VERSION 5.7 ;
BUSBITCHARS "[]" ;
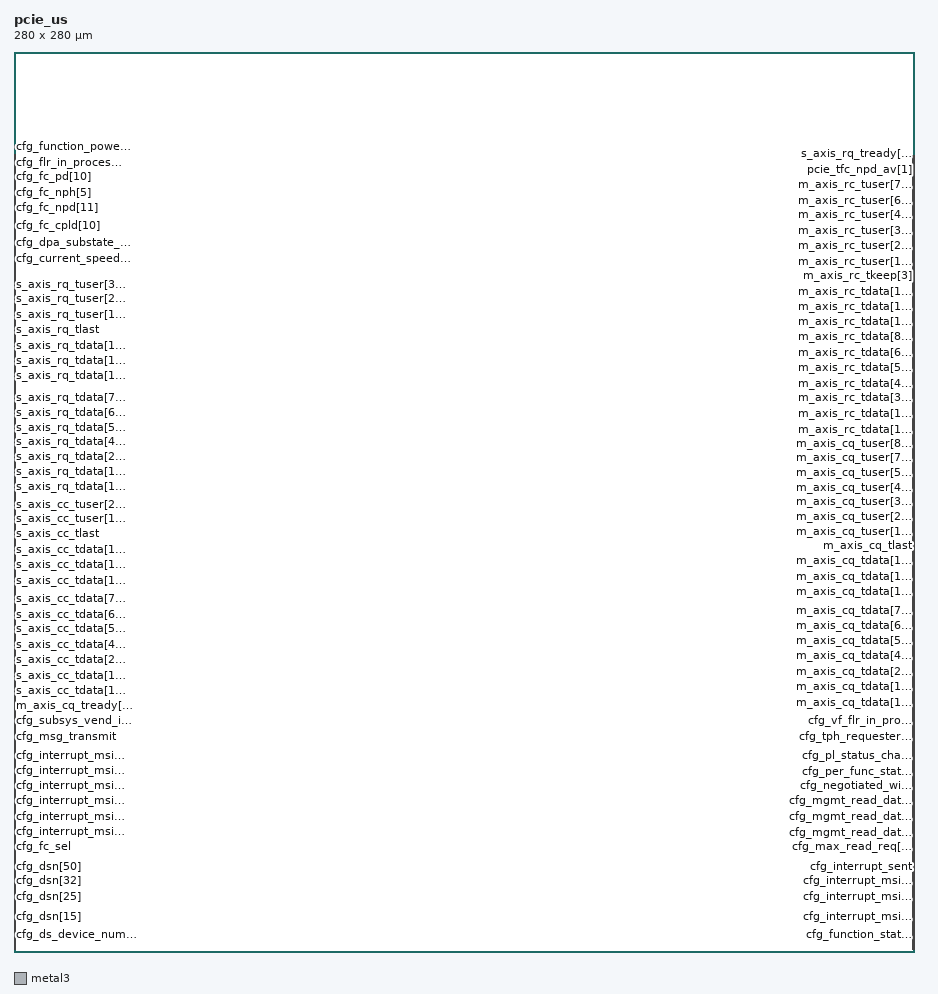
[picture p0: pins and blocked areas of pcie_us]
MACRO pcie_us
  CLASS BLOCK ;
  FOREIGN pcie_us 0 0 ;
  SYMMETRY X Y R90 ;
  SIZE 280.000 BY 280.000 ;
  PIN cfg_config_space_enable
    DIRECTION INPUT ;
    USE SIGNAL ;
    PORT
      LAYER metal3 ;
      RECT 0.000 0.795 0.380 0.865 ;
    END
  END cfg_config_space_enable
  PIN cfg_ds_bus_number[0]
    DIRECTION INPUT ;
    USE SIGNAL ;
    PORT
      LAYER metal3 ;
      RECT 0.000 1.175 0.380 1.245 ;
    END
  END cfg_ds_bus_number[0]
  PIN cfg_ds_bus_number[1]
    DIRECTION INPUT ;
    USE SIGNAL ;
    PORT
      LAYER metal3 ;
      RECT 0.000 1.555 0.380 1.625 ;
    END
  END cfg_ds_bus_number[1]
  PIN cfg_ds_bus_number[2]
    DIRECTION INPUT ;
    USE SIGNAL ;
    PORT
      LAYER metal3 ;
      RECT 0.000 1.935 0.380 2.005 ;
    END
  END cfg_ds_bus_number[2]
  PIN cfg_ds_bus_number[3]
    DIRECTION INPUT ;
    USE SIGNAL ;
    PORT
      LAYER metal3 ;
      RECT 0.000 2.315 0.380 2.385 ;
    END
  END cfg_ds_bus_number[3]
  PIN cfg_ds_bus_number[4]
    DIRECTION INPUT ;
    USE SIGNAL ;
    PORT
      LAYER metal3 ;
      RECT 0.000 2.695 0.380 2.765 ;
    END
  END cfg_ds_bus_number[4]
  PIN cfg_ds_bus_number[5]
    DIRECTION INPUT ;
    USE SIGNAL ;
    PORT
      LAYER metal3 ;
      RECT 0.000 3.075 0.380 3.145 ;
    END
  END cfg_ds_bus_number[5]
  PIN cfg_ds_bus_number[6]
    DIRECTION INPUT ;
    USE SIGNAL ;
    PORT
      LAYER metal3 ;
      RECT 0.000 3.455 0.380 3.525 ;
    END
  END cfg_ds_bus_number[6]
  PIN cfg_ds_bus_number[7]
    DIRECTION INPUT ;
    USE SIGNAL ;
    PORT
      LAYER metal3 ;
      RECT 0.000 3.835 0.380 3.905 ;
    END
  END cfg_ds_bus_number[7]
  PIN cfg_ds_device_number[0]
    DIRECTION INPUT ;
    USE SIGNAL ;
    PORT
      LAYER metal3 ;
      RECT 0.000 4.215 0.380 4.285 ;
    END
  END cfg_ds_device_number[0]
  PIN cfg_ds_device_number[1]
    DIRECTION INPUT ;
    USE SIGNAL ;
    PORT
      LAYER metal3 ;
      RECT 0.000 4.595 0.380 4.665 ;
    END
  END cfg_ds_device_number[1]
  PIN cfg_ds_device_number[2]
    DIRECTION INPUT ;
    USE SIGNAL ;
    PORT
      LAYER metal3 ;
      RECT 0.000 4.975 0.380 5.045 ;
    END
  END cfg_ds_device_number[2]
  PIN cfg_ds_device_number[3]
    DIRECTION INPUT ;
    USE SIGNAL ;
    PORT
      LAYER metal3 ;
      RECT 0.000 5.355 0.380 5.425 ;
    END
  END cfg_ds_device_number[3]
  PIN cfg_ds_device_number[4]
    DIRECTION INPUT ;
    USE SIGNAL ;
    PORT
      LAYER metal3 ;
      RECT 0.000 5.735 0.380 5.805 ;
    END
  END cfg_ds_device_number[4]
  PIN cfg_ds_function_number[0]
    DIRECTION INPUT ;
    USE SIGNAL ;
    PORT
      LAYER metal3 ;
      RECT 0.000 6.115 0.380 6.185 ;
    END
  END cfg_ds_function_number[0]
  PIN cfg_ds_function_number[1]
    DIRECTION INPUT ;
    USE SIGNAL ;
    PORT
      LAYER metal3 ;
      RECT 0.000 6.495 0.380 6.565 ;
    END
  END cfg_ds_function_number[1]
  PIN cfg_ds_function_number[2]
    DIRECTION INPUT ;
    USE SIGNAL ;
    PORT
      LAYER metal3 ;
      RECT 0.000 6.875 0.380 6.945 ;
    END
  END cfg_ds_function_number[2]
  PIN cfg_ds_port_number
    DIRECTION INPUT ;
    USE SIGNAL ;
    PORT
      LAYER metal3 ;
      RECT 0.000 7.255 0.380 7.325 ;
    END
  END cfg_ds_port_number
  PIN cfg_dsn[0]
    DIRECTION INPUT ;
    USE SIGNAL ;
    PORT
      LAYER metal3 ;
      RECT 0.000 7.635 0.380 7.705 ;
    END
  END cfg_dsn[0]
  PIN cfg_dsn[1]
    DIRECTION INPUT ;
    USE SIGNAL ;
    PORT
      LAYER metal3 ;
      RECT 0.000 8.015 0.380 8.085 ;
    END
  END cfg_dsn[1]
  PIN cfg_dsn[2]
    DIRECTION INPUT ;
    USE SIGNAL ;
    PORT
      LAYER metal3 ;
      RECT 0.000 8.395 0.380 8.465 ;
    END
  END cfg_dsn[2]
  PIN cfg_dsn[3]
    DIRECTION INPUT ;
    USE SIGNAL ;
    PORT
      LAYER metal3 ;
      RECT 0.000 8.775 0.380 8.845 ;
    END
  END cfg_dsn[3]
  PIN cfg_dsn[4]
    DIRECTION INPUT ;
    USE SIGNAL ;
    PORT
      LAYER metal3 ;
      RECT 0.000 9.155 0.380 9.225 ;
    END
  END cfg_dsn[4]
  PIN cfg_dsn[5]
    DIRECTION INPUT ;
    USE SIGNAL ;
    PORT
      LAYER metal3 ;
      RECT 0.000 9.535 0.380 9.605 ;
    END
  END cfg_dsn[5]
  PIN cfg_dsn[6]
    DIRECTION INPUT ;
    USE SIGNAL ;
    PORT
      LAYER metal3 ;
      RECT 0.000 9.915 0.380 9.985 ;
    END
  END cfg_dsn[6]
  PIN cfg_dsn[7]
    DIRECTION INPUT ;
    USE SIGNAL ;
    PORT
      LAYER metal3 ;
      RECT 0.000 10.295 0.380 10.365 ;
    END
  END cfg_dsn[7]
  PIN cfg_dsn[8]
    DIRECTION INPUT ;
    USE SIGNAL ;
    PORT
      LAYER metal3 ;
      RECT 0.000 10.675 0.380 10.745 ;
    END
  END cfg_dsn[8]
  PIN cfg_dsn[9]
    DIRECTION INPUT ;
    USE SIGNAL ;
    PORT
      LAYER metal3 ;
      RECT 0.000 11.055 0.380 11.125 ;
    END
  END cfg_dsn[9]
  PIN cfg_dsn[10]
    DIRECTION INPUT ;
    USE SIGNAL ;
    PORT
      LAYER metal3 ;
      RECT 0.000 11.435 0.380 11.505 ;
    END
  END cfg_dsn[10]
  PIN cfg_dsn[11]
    DIRECTION INPUT ;
    USE SIGNAL ;
    PORT
      LAYER metal3 ;
      RECT 0.000 11.815 0.380 11.885 ;
    END
  END cfg_dsn[11]
  PIN cfg_dsn[12]
    DIRECTION INPUT ;
    USE SIGNAL ;
    PORT
      LAYER metal3 ;
      RECT 0.000 12.195 0.380 12.265 ;
    END
  END cfg_dsn[12]
  PIN cfg_dsn[13]
    DIRECTION INPUT ;
    USE SIGNAL ;
    PORT
      LAYER metal3 ;
      RECT 0.000 12.575 0.380 12.645 ;
    END
  END cfg_dsn[13]
  PIN cfg_dsn[14]
    DIRECTION INPUT ;
    USE SIGNAL ;
    PORT
      LAYER metal3 ;
      RECT 0.000 12.955 0.380 13.025 ;
    END
  END cfg_dsn[14]
  PIN cfg_dsn[15]
    DIRECTION INPUT ;
    USE SIGNAL ;
    PORT
      LAYER metal3 ;
      RECT 0.000 13.335 0.380 13.405 ;
    END
  END cfg_dsn[15]
  PIN cfg_dsn[16]
    DIRECTION INPUT ;
    USE SIGNAL ;
    PORT
      LAYER metal3 ;
      RECT 0.000 13.715 0.380 13.785 ;
    END
  END cfg_dsn[16]
  PIN cfg_dsn[17]
    DIRECTION INPUT ;
    USE SIGNAL ;
    PORT
      LAYER metal3 ;
      RECT 0.000 14.095 0.380 14.165 ;
    END
  END cfg_dsn[17]
  PIN cfg_dsn[18]
    DIRECTION INPUT ;
    USE SIGNAL ;
    PORT
      LAYER metal3 ;
      RECT 0.000 14.475 0.380 14.545 ;
    END
  END cfg_dsn[18]
  PIN cfg_dsn[19]
    DIRECTION INPUT ;
    USE SIGNAL ;
    PORT
      LAYER metal3 ;
      RECT 0.000 14.855 0.380 14.925 ;
    END
  END cfg_dsn[19]
  PIN cfg_dsn[20]
    DIRECTION INPUT ;
    USE SIGNAL ;
    PORT
      LAYER metal3 ;
      RECT 0.000 15.235 0.380 15.305 ;
    END
  END cfg_dsn[20]
  PIN cfg_dsn[21]
    DIRECTION INPUT ;
    USE SIGNAL ;
    PORT
      LAYER metal3 ;
      RECT 0.000 15.615 0.380 15.685 ;
    END
  END cfg_dsn[21]
  PIN cfg_dsn[22]
    DIRECTION INPUT ;
    USE SIGNAL ;
    PORT
      LAYER metal3 ;
      RECT 0.000 15.995 0.380 16.065 ;
    END
  END cfg_dsn[22]
  PIN cfg_dsn[23]
    DIRECTION INPUT ;
    USE SIGNAL ;
    PORT
      LAYER metal3 ;
      RECT 0.000 16.375 0.380 16.445 ;
    END
  END cfg_dsn[23]
  PIN cfg_dsn[24]
    DIRECTION INPUT ;
    USE SIGNAL ;
    PORT
      LAYER metal3 ;
      RECT 0.000 16.755 0.380 16.825 ;
    END
  END cfg_dsn[24]
  PIN cfg_dsn[25]
    DIRECTION INPUT ;
    USE SIGNAL ;
    PORT
      LAYER metal3 ;
      RECT 0.000 17.135 0.380 17.205 ;
    END
  END cfg_dsn[25]
  PIN cfg_dsn[26]
    DIRECTION INPUT ;
    USE SIGNAL ;
    PORT
      LAYER metal3 ;
      RECT 0.000 17.515 0.380 17.585 ;
    END
  END cfg_dsn[26]
  PIN cfg_dsn[27]
    DIRECTION INPUT ;
    USE SIGNAL ;
    PORT
      LAYER metal3 ;
      RECT 0.000 17.895 0.380 17.965 ;
    END
  END cfg_dsn[27]
  PIN cfg_dsn[28]
    DIRECTION INPUT ;
    USE SIGNAL ;
    PORT
      LAYER metal3 ;
      RECT 0.000 18.275 0.380 18.345 ;
    END
  END cfg_dsn[28]
  PIN cfg_dsn[29]
    DIRECTION INPUT ;
    USE SIGNAL ;
    PORT
      LAYER metal3 ;
      RECT 0.000 18.655 0.380 18.725 ;
    END
  END cfg_dsn[29]
  PIN cfg_dsn[30]
    DIRECTION INPUT ;
    USE SIGNAL ;
    PORT
      LAYER metal3 ;
      RECT 0.000 19.035 0.380 19.105 ;
    END
  END cfg_dsn[30]
  PIN cfg_dsn[31]
    DIRECTION INPUT ;
    USE SIGNAL ;
    PORT
      LAYER metal3 ;
      RECT 0.000 19.415 0.380 19.485 ;
    END
  END cfg_dsn[31]
  PIN cfg_dsn[32]
    DIRECTION INPUT ;
    USE SIGNAL ;
    PORT
      LAYER metal3 ;
      RECT 0.000 19.795 0.380 19.865 ;
    END
  END cfg_dsn[32]
  PIN cfg_dsn[33]
    DIRECTION INPUT ;
    USE SIGNAL ;
    PORT
      LAYER metal3 ;
      RECT 0.000 20.175 0.380 20.245 ;
    END
  END cfg_dsn[33]
  PIN cfg_dsn[34]
    DIRECTION INPUT ;
    USE SIGNAL ;
    PORT
      LAYER metal3 ;
      RECT 0.000 20.555 0.380 20.625 ;
    END
  END cfg_dsn[34]
  PIN cfg_dsn[35]
    DIRECTION INPUT ;
    USE SIGNAL ;
    PORT
      LAYER metal3 ;
      RECT 0.000 20.935 0.380 21.005 ;
    END
  END cfg_dsn[35]
  PIN cfg_dsn[36]
    DIRECTION INPUT ;
    USE SIGNAL ;
    PORT
      LAYER metal3 ;
      RECT 0.000 21.315 0.380 21.385 ;
    END
  END cfg_dsn[36]
  PIN cfg_dsn[37]
    DIRECTION INPUT ;
    USE SIGNAL ;
    PORT
      LAYER metal3 ;
      RECT 0.000 21.695 0.380 21.765 ;
    END
  END cfg_dsn[37]
  PIN cfg_dsn[38]
    DIRECTION INPUT ;
    USE SIGNAL ;
    PORT
      LAYER metal3 ;
      RECT 0.000 22.075 0.380 22.145 ;
    END
  END cfg_dsn[38]
  PIN cfg_dsn[39]
    DIRECTION INPUT ;
    USE SIGNAL ;
    PORT
      LAYER metal3 ;
      RECT 0.000 22.455 0.380 22.525 ;
    END
  END cfg_dsn[39]
  PIN cfg_dsn[40]
    DIRECTION INPUT ;
    USE SIGNAL ;
    PORT
      LAYER metal3 ;
      RECT 0.000 22.835 0.380 22.905 ;
    END
  END cfg_dsn[40]
  PIN cfg_dsn[41]
    DIRECTION INPUT ;
    USE SIGNAL ;
    PORT
      LAYER metal3 ;
      RECT 0.000 23.215 0.380 23.285 ;
    END
  END cfg_dsn[41]
  PIN cfg_dsn[42]
    DIRECTION INPUT ;
    USE SIGNAL ;
    PORT
      LAYER metal3 ;
      RECT 0.000 23.595 0.380 23.665 ;
    END
  END cfg_dsn[42]
  PIN cfg_dsn[43]
    DIRECTION INPUT ;
    USE SIGNAL ;
    PORT
      LAYER metal3 ;
      RECT 0.000 23.975 0.380 24.045 ;
    END
  END cfg_dsn[43]
  PIN cfg_dsn[44]
    DIRECTION INPUT ;
    USE SIGNAL ;
    PORT
      LAYER metal3 ;
      RECT 0.000 24.355 0.380 24.425 ;
    END
  END cfg_dsn[44]
  PIN cfg_dsn[45]
    DIRECTION INPUT ;
    USE SIGNAL ;
    PORT
      LAYER metal3 ;
      RECT 0.000 24.735 0.380 24.805 ;
    END
  END cfg_dsn[45]
  PIN cfg_dsn[46]
    DIRECTION INPUT ;
    USE SIGNAL ;
    PORT
      LAYER metal3 ;
      RECT 0.000 25.115 0.380 25.185 ;
    END
  END cfg_dsn[46]
  PIN cfg_dsn[47]
    DIRECTION INPUT ;
    USE SIGNAL ;
    PORT
      LAYER metal3 ;
      RECT 0.000 25.495 0.380 25.565 ;
    END
  END cfg_dsn[47]
  PIN cfg_dsn[48]
    DIRECTION INPUT ;
    USE SIGNAL ;
    PORT
      LAYER metal3 ;
      RECT 0.000 25.875 0.380 25.945 ;
    END
  END cfg_dsn[48]
  PIN cfg_dsn[49]
    DIRECTION INPUT ;
    USE SIGNAL ;
    PORT
      LAYER metal3 ;
      RECT 0.000 26.255 0.380 26.325 ;
    END
  END cfg_dsn[49]
  PIN cfg_dsn[50]
    DIRECTION INPUT ;
    USE SIGNAL ;
    PORT
      LAYER metal3 ;
      RECT 0.000 26.635 0.380 26.705 ;
    END
  END cfg_dsn[50]
  PIN cfg_dsn[51]
    DIRECTION INPUT ;
    USE SIGNAL ;
    PORT
      LAYER metal3 ;
      RECT 0.000 27.015 0.380 27.085 ;
    END
  END cfg_dsn[51]
  PIN cfg_dsn[52]
    DIRECTION INPUT ;
    USE SIGNAL ;
    PORT
      LAYER metal3 ;
      RECT 0.000 27.395 0.380 27.465 ;
    END
  END cfg_dsn[52]
  PIN cfg_dsn[53]
    DIRECTION INPUT ;
    USE SIGNAL ;
    PORT
      LAYER metal3 ;
      RECT 0.000 27.775 0.380 27.845 ;
    END
  END cfg_dsn[53]
  PIN cfg_dsn[54]
    DIRECTION INPUT ;
    USE SIGNAL ;
    PORT
      LAYER metal3 ;
      RECT 0.000 28.155 0.380 28.225 ;
    END
  END cfg_dsn[54]
  PIN cfg_dsn[55]
    DIRECTION INPUT ;
    USE SIGNAL ;
    PORT
      LAYER metal3 ;
      RECT 0.000 28.535 0.380 28.605 ;
    END
  END cfg_dsn[55]
  PIN cfg_dsn[56]
    DIRECTION INPUT ;
    USE SIGNAL ;
    PORT
      LAYER metal3 ;
      RECT 0.000 28.915 0.380 28.985 ;
    END
  END cfg_dsn[56]
  PIN cfg_dsn[57]
    DIRECTION INPUT ;
    USE SIGNAL ;
    PORT
      LAYER metal3 ;
      RECT 0.000 29.295 0.380 29.365 ;
    END
  END cfg_dsn[57]
  PIN cfg_dsn[58]
    DIRECTION INPUT ;
    USE SIGNAL ;
    PORT
      LAYER metal3 ;
      RECT 0.000 29.675 0.380 29.745 ;
    END
  END cfg_dsn[58]
  PIN cfg_dsn[59]
    DIRECTION INPUT ;
    USE SIGNAL ;
    PORT
      LAYER metal3 ;
      RECT 0.000 30.055 0.380 30.125 ;
    END
  END cfg_dsn[59]
  PIN cfg_dsn[60]
    DIRECTION INPUT ;
    USE SIGNAL ;
    PORT
      LAYER metal3 ;
      RECT 0.000 30.435 0.380 30.505 ;
    END
  END cfg_dsn[60]
  PIN cfg_dsn[61]
    DIRECTION INPUT ;
    USE SIGNAL ;
    PORT
      LAYER metal3 ;
      RECT 0.000 30.815 0.380 30.885 ;
    END
  END cfg_dsn[61]
  PIN cfg_dsn[62]
    DIRECTION INPUT ;
    USE SIGNAL ;
    PORT
      LAYER metal3 ;
      RECT 0.000 31.195 0.380 31.265 ;
    END
  END cfg_dsn[62]
  PIN cfg_dsn[63]
    DIRECTION INPUT ;
    USE SIGNAL ;
    PORT
      LAYER metal3 ;
      RECT 0.000 31.575 0.380 31.645 ;
    END
  END cfg_dsn[63]
  PIN cfg_err_cor_in
    DIRECTION INPUT ;
    USE SIGNAL ;
    PORT
      LAYER metal3 ;
      RECT 0.000 31.955 0.380 32.025 ;
    END
  END cfg_err_cor_in
  PIN cfg_err_uncor_in
    DIRECTION INPUT ;
    USE SIGNAL ;
    PORT
      LAYER metal3 ;
      RECT 0.000 32.335 0.380 32.405 ;
    END
  END cfg_err_uncor_in
  PIN cfg_fc_sel
    DIRECTION INPUT ;
    USE SIGNAL ;
    PORT
      LAYER metal3 ;
      RECT 0.000 32.715 0.380 32.785 ;
    END
  END cfg_fc_sel
  PIN cfg_flr_done
    DIRECTION INPUT ;
    USE SIGNAL ;
    PORT
      LAYER metal3 ;
      RECT 0.000 33.095 0.380 33.165 ;
    END
  END cfg_flr_done
  PIN cfg_hot_reset_in
    DIRECTION INPUT ;
    USE SIGNAL ;
    PORT
      LAYER metal3 ;
      RECT 0.000 33.475 0.380 33.545 ;
    END
  END cfg_hot_reset_in
  PIN cfg_interrupt_int
    DIRECTION INPUT ;
    USE SIGNAL ;
    PORT
      LAYER metal3 ;
      RECT 0.000 33.855 0.380 33.925 ;
    END
  END cfg_interrupt_int
  PIN cfg_interrupt_msi_attr
    DIRECTION INPUT ;
    USE SIGNAL ;
    PORT
      LAYER metal3 ;
      RECT 0.000 34.235 0.380 34.305 ;
    END
  END cfg_interrupt_msi_attr
  PIN cfg_interrupt_msi_function_number
    DIRECTION INPUT ;
    USE SIGNAL ;
    PORT
      LAYER metal3 ;
      RECT 0.000 34.615 0.380 34.685 ;
    END
  END cfg_interrupt_msi_function_number
  PIN cfg_interrupt_msi_int[0]
    DIRECTION INPUT ;
    USE SIGNAL ;
    PORT
      LAYER metal3 ;
      RECT 0.000 34.995 0.380 35.065 ;
    END
  END cfg_interrupt_msi_int[0]
  PIN cfg_interrupt_msi_int[1]
    DIRECTION INPUT ;
    USE SIGNAL ;
    PORT
      LAYER metal3 ;
      RECT 0.000 35.375 0.380 35.445 ;
    END
  END cfg_interrupt_msi_int[1]
  PIN cfg_interrupt_msi_int[2]
    DIRECTION INPUT ;
    USE SIGNAL ;
    PORT
      LAYER metal3 ;
      RECT 0.000 35.755 0.380 35.825 ;
    END
  END cfg_interrupt_msi_int[2]
  PIN cfg_interrupt_msi_int[3]
    DIRECTION INPUT ;
    USE SIGNAL ;
    PORT
      LAYER metal3 ;
      RECT 0.000 36.135 0.380 36.205 ;
    END
  END cfg_interrupt_msi_int[3]
  PIN cfg_interrupt_msi_int[4]
    DIRECTION INPUT ;
    USE SIGNAL ;
    PORT
      LAYER metal3 ;
      RECT 0.000 36.515 0.380 36.585 ;
    END
  END cfg_interrupt_msi_int[4]
  PIN cfg_interrupt_msi_int[5]
    DIRECTION INPUT ;
    USE SIGNAL ;
    PORT
      LAYER metal3 ;
      RECT 0.000 36.895 0.380 36.965 ;
    END
  END cfg_interrupt_msi_int[5]
  PIN cfg_interrupt_msi_int[6]
    DIRECTION INPUT ;
    USE SIGNAL ;
    PORT
      LAYER metal3 ;
      RECT 0.000 37.275 0.380 37.345 ;
    END
  END cfg_interrupt_msi_int[6]
  PIN cfg_interrupt_msi_int[7]
    DIRECTION INPUT ;
    USE SIGNAL ;
    PORT
      LAYER metal3 ;
      RECT 0.000 37.655 0.380 37.725 ;
    END
  END cfg_interrupt_msi_int[7]
  PIN cfg_interrupt_msi_int[8]
    DIRECTION INPUT ;
    USE SIGNAL ;
    PORT
      LAYER metal3 ;
      RECT 0.000 38.035 0.380 38.105 ;
    END
  END cfg_interrupt_msi_int[8]
  PIN cfg_interrupt_msi_int[9]
    DIRECTION INPUT ;
    USE SIGNAL ;
    PORT
      LAYER metal3 ;
      RECT 0.000 38.415 0.380 38.485 ;
    END
  END cfg_interrupt_msi_int[9]
  PIN cfg_interrupt_msi_int[10]
    DIRECTION INPUT ;
    USE SIGNAL ;
    PORT
      LAYER metal3 ;
      RECT 0.000 38.795 0.380 38.865 ;
    END
  END cfg_interrupt_msi_int[10]
  PIN cfg_interrupt_msi_int[11]
    DIRECTION INPUT ;
    USE SIGNAL ;
    PORT
      LAYER metal3 ;
      RECT 0.000 39.175 0.380 39.245 ;
    END
  END cfg_interrupt_msi_int[11]
  PIN cfg_interrupt_msi_int[12]
    DIRECTION INPUT ;
    USE SIGNAL ;
    PORT
      LAYER metal3 ;
      RECT 0.000 39.555 0.380 39.625 ;
    END
  END cfg_interrupt_msi_int[12]
  PIN cfg_interrupt_msi_int[13]
    DIRECTION INPUT ;
    USE SIGNAL ;
    PORT
      LAYER metal3 ;
      RECT 0.000 39.935 0.380 40.005 ;
    END
  END cfg_interrupt_msi_int[13]
  PIN cfg_interrupt_msi_int[14]
    DIRECTION INPUT ;
    USE SIGNAL ;
    PORT
      LAYER metal3 ;
      RECT 0.000 40.315 0.380 40.385 ;
    END
  END cfg_interrupt_msi_int[14]
  PIN cfg_interrupt_msi_int[15]
    DIRECTION INPUT ;
    USE SIGNAL ;
    PORT
      LAYER metal3 ;
      RECT 0.000 40.695 0.380 40.765 ;
    END
  END cfg_interrupt_msi_int[15]
  PIN cfg_interrupt_msi_int[16]
    DIRECTION INPUT ;
    USE SIGNAL ;
    PORT
      LAYER metal3 ;
      RECT 0.000 41.075 0.380 41.145 ;
    END
  END cfg_interrupt_msi_int[16]
  PIN cfg_interrupt_msi_int[17]
    DIRECTION INPUT ;
    USE SIGNAL ;
    PORT
      LAYER metal3 ;
      RECT 0.000 41.455 0.380 41.525 ;
    END
  END cfg_interrupt_msi_int[17]
  PIN cfg_interrupt_msi_int[18]
    DIRECTION INPUT ;
    USE SIGNAL ;
    PORT
      LAYER metal3 ;
      RECT 0.000 41.835 0.380 41.905 ;
    END
  END cfg_interrupt_msi_int[18]
  PIN cfg_interrupt_msi_int[19]
    DIRECTION INPUT ;
    USE SIGNAL ;
    PORT
      LAYER metal3 ;
      RECT 0.000 42.215 0.380 42.285 ;
    END
  END cfg_interrupt_msi_int[19]
  PIN cfg_interrupt_msi_int[20]
    DIRECTION INPUT ;
    USE SIGNAL ;
    PORT
      LAYER metal3 ;
      RECT 0.000 42.595 0.380 42.665 ;
    END
  END cfg_interrupt_msi_int[20]
  PIN cfg_interrupt_msi_int[21]
    DIRECTION INPUT ;
    USE SIGNAL ;
    PORT
      LAYER metal3 ;
      RECT 0.000 42.975 0.380 43.045 ;
    END
  END cfg_interrupt_msi_int[21]
  PIN cfg_interrupt_msi_int[22]
    DIRECTION INPUT ;
    USE SIGNAL ;
    PORT
      LAYER metal3 ;
      RECT 0.000 43.355 0.380 43.425 ;
    END
  END cfg_interrupt_msi_int[22]
  PIN cfg_interrupt_msi_int[23]
    DIRECTION INPUT ;
    USE SIGNAL ;
    PORT
      LAYER metal3 ;
      RECT 0.000 43.735 0.380 43.805 ;
    END
  END cfg_interrupt_msi_int[23]
  PIN cfg_interrupt_msi_int[24]
    DIRECTION INPUT ;
    USE SIGNAL ;
    PORT
      LAYER metal3 ;
      RECT 0.000 44.115 0.380 44.185 ;
    END
  END cfg_interrupt_msi_int[24]
  PIN cfg_interrupt_msi_int[25]
    DIRECTION INPUT ;
    USE SIGNAL ;
    PORT
      LAYER metal3 ;
      RECT 0.000 44.495 0.380 44.565 ;
    END
  END cfg_interrupt_msi_int[25]
  PIN cfg_interrupt_msi_int[26]
    DIRECTION INPUT ;
    USE SIGNAL ;
    PORT
      LAYER metal3 ;
      RECT 0.000 44.875 0.380 44.945 ;
    END
  END cfg_interrupt_msi_int[26]
  PIN cfg_interrupt_msi_int[27]
    DIRECTION INPUT ;
    USE SIGNAL ;
    PORT
      LAYER metal3 ;
      RECT 0.000 45.255 0.380 45.325 ;
    END
  END cfg_interrupt_msi_int[27]
  PIN cfg_interrupt_msi_int[28]
    DIRECTION INPUT ;
    USE SIGNAL ;
    PORT
      LAYER metal3 ;
      RECT 0.000 45.635 0.380 45.705 ;
    END
  END cfg_interrupt_msi_int[28]
  PIN cfg_interrupt_msi_int[29]
    DIRECTION INPUT ;
    USE SIGNAL ;
    PORT
      LAYER metal3 ;
      RECT 0.000 46.015 0.380 46.085 ;
    END
  END cfg_interrupt_msi_int[29]
  PIN cfg_interrupt_msi_int[30]
    DIRECTION INPUT ;
    USE SIGNAL ;
    PORT
      LAYER metal3 ;
      RECT 0.000 46.395 0.380 46.465 ;
    END
  END cfg_interrupt_msi_int[30]
  PIN cfg_interrupt_msi_int[31]
    DIRECTION INPUT ;
    USE SIGNAL ;
    PORT
      LAYER metal3 ;
      RECT 0.000 46.775 0.380 46.845 ;
    END
  END cfg_interrupt_msi_int[31]
  PIN cfg_interrupt_msi_pending_status[0]
    DIRECTION INPUT ;
    USE SIGNAL ;
    PORT
      LAYER metal3 ;
      RECT 0.000 47.155 0.380 47.225 ;
    END
  END cfg_interrupt_msi_pending_status[0]
  PIN cfg_interrupt_msi_pending_status[1]
    DIRECTION INPUT ;
    USE SIGNAL ;
    PORT
      LAYER metal3 ;
      RECT 0.000 47.535 0.380 47.605 ;
    END
  END cfg_interrupt_msi_pending_status[1]
  PIN cfg_interrupt_msi_pending_status[2]
    DIRECTION INPUT ;
    USE SIGNAL ;
    PORT
      LAYER metal3 ;
      RECT 0.000 47.915 0.380 47.985 ;
    END
  END cfg_interrupt_msi_pending_status[2]
  PIN cfg_interrupt_msi_pending_status[3]
    DIRECTION INPUT ;
    USE SIGNAL ;
    PORT
      LAYER metal3 ;
      RECT 0.000 48.295 0.380 48.365 ;
    END
  END cfg_interrupt_msi_pending_status[3]
  PIN cfg_interrupt_msi_pending_status[4]
    DIRECTION INPUT ;
    USE SIGNAL ;
    PORT
      LAYER metal3 ;
      RECT 0.000 48.675 0.380 48.745 ;
    END
  END cfg_interrupt_msi_pending_status[4]
  PIN cfg_interrupt_msi_pending_status[5]
    DIRECTION INPUT ;
    USE SIGNAL ;
    PORT
      LAYER metal3 ;
      RECT 0.000 49.055 0.380 49.125 ;
    END
  END cfg_interrupt_msi_pending_status[5]
  PIN cfg_interrupt_msi_pending_status[6]
    DIRECTION INPUT ;
    USE SIGNAL ;
    PORT
      LAYER metal3 ;
      RECT 0.000 49.435 0.380 49.505 ;
    END
  END cfg_interrupt_msi_pending_status[6]
  PIN cfg_interrupt_msi_pending_status[7]
    DIRECTION INPUT ;
    USE SIGNAL ;
    PORT
      LAYER metal3 ;
      RECT 0.000 49.815 0.380 49.885 ;
    END
  END cfg_interrupt_msi_pending_status[7]
  PIN cfg_interrupt_msi_pending_status[8]
    DIRECTION INPUT ;
    USE SIGNAL ;
    PORT
      LAYER metal3 ;
      RECT 0.000 50.195 0.380 50.265 ;
    END
  END cfg_interrupt_msi_pending_status[8]
  PIN cfg_interrupt_msi_pending_status[9]
    DIRECTION INPUT ;
    USE SIGNAL ;
    PORT
      LAYER metal3 ;
      RECT 0.000 50.575 0.380 50.645 ;
    END
  END cfg_interrupt_msi_pending_status[9]
  PIN cfg_interrupt_msi_pending_status[10]
    DIRECTION INPUT ;
    USE SIGNAL ;
    PORT
      LAYER metal3 ;
      RECT 0.000 50.955 0.380 51.025 ;
    END
  END cfg_interrupt_msi_pending_status[10]
  PIN cfg_interrupt_msi_pending_status[11]
    DIRECTION INPUT ;
    USE SIGNAL ;
    PORT
      LAYER metal3 ;
      RECT 0.000 51.335 0.380 51.405 ;
    END
  END cfg_interrupt_msi_pending_status[11]
  PIN cfg_interrupt_msi_pending_status[12]
    DIRECTION INPUT ;
    USE SIGNAL ;
    PORT
      LAYER metal3 ;
      RECT 0.000 51.715 0.380 51.785 ;
    END
  END cfg_interrupt_msi_pending_status[12]
  PIN cfg_interrupt_msi_pending_status[13]
    DIRECTION INPUT ;
    USE SIGNAL ;
    PORT
      LAYER metal3 ;
      RECT 0.000 52.095 0.380 52.165 ;
    END
  END cfg_interrupt_msi_pending_status[13]
  PIN cfg_interrupt_msi_pending_status[14]
    DIRECTION INPUT ;
    USE SIGNAL ;
    PORT
      LAYER metal3 ;
      RECT 0.000 52.475 0.380 52.545 ;
    END
  END cfg_interrupt_msi_pending_status[14]
  PIN cfg_interrupt_msi_pending_status[15]
    DIRECTION INPUT ;
    USE SIGNAL ;
    PORT
      LAYER metal3 ;
      RECT 0.000 52.855 0.380 52.925 ;
    END
  END cfg_interrupt_msi_pending_status[15]
  PIN cfg_interrupt_msi_pending_status[16]
    DIRECTION INPUT ;
    USE SIGNAL ;
    PORT
      LAYER metal3 ;
      RECT 0.000 53.235 0.380 53.305 ;
    END
  END cfg_interrupt_msi_pending_status[16]
  PIN cfg_interrupt_msi_pending_status[17]
    DIRECTION INPUT ;
    USE SIGNAL ;
    PORT
      LAYER metal3 ;
      RECT 0.000 53.615 0.380 53.685 ;
    END
  END cfg_interrupt_msi_pending_status[17]
  PIN cfg_interrupt_msi_pending_status[18]
    DIRECTION INPUT ;
    USE SIGNAL ;
    PORT
      LAYER metal3 ;
      RECT 0.000 53.995 0.380 54.065 ;
    END
  END cfg_interrupt_msi_pending_status[18]
  PIN cfg_interrupt_msi_pending_status[19]
    DIRECTION INPUT ;
    USE SIGNAL ;
    PORT
      LAYER metal3 ;
      RECT 0.000 54.375 0.380 54.445 ;
    END
  END cfg_interrupt_msi_pending_status[19]
  PIN cfg_interrupt_msi_pending_status[20]
    DIRECTION INPUT ;
    USE SIGNAL ;
    PORT
      LAYER metal3 ;
      RECT 0.000 54.755 0.380 54.825 ;
    END
  END cfg_interrupt_msi_pending_status[20]
  PIN cfg_interrupt_msi_pending_status[21]
    DIRECTION INPUT ;
    USE SIGNAL ;
    PORT
      LAYER metal3 ;
      RECT 0.000 55.135 0.380 55.205 ;
    END
  END cfg_interrupt_msi_pending_status[21]
  PIN cfg_interrupt_msi_pending_status[22]
    DIRECTION INPUT ;
    USE SIGNAL ;
    PORT
      LAYER metal3 ;
      RECT 0.000 55.515 0.380 55.585 ;
    END
  END cfg_interrupt_msi_pending_status[22]
  PIN cfg_interrupt_msi_pending_status[23]
    DIRECTION INPUT ;
    USE SIGNAL ;
    PORT
      LAYER metal3 ;
      RECT 0.000 55.895 0.380 55.965 ;
    END
  END cfg_interrupt_msi_pending_status[23]
  PIN cfg_interrupt_msi_pending_status[24]
    DIRECTION INPUT ;
    USE SIGNAL ;
    PORT
      LAYER metal3 ;
      RECT 0.000 56.275 0.380 56.345 ;
    END
  END cfg_interrupt_msi_pending_status[24]
  PIN cfg_interrupt_msi_pending_status[25]
    DIRECTION INPUT ;
    USE SIGNAL ;
    PORT
      LAYER metal3 ;
      RECT 0.000 56.655 0.380 56.725 ;
    END
  END cfg_interrupt_msi_pending_status[25]
  PIN cfg_interrupt_msi_pending_status[26]
    DIRECTION INPUT ;
    USE SIGNAL ;
    PORT
      LAYER metal3 ;
      RECT 0.000 57.035 0.380 57.105 ;
    END
  END cfg_interrupt_msi_pending_status[26]
  PIN cfg_interrupt_msi_pending_status[27]
    DIRECTION INPUT ;
    USE SIGNAL ;
    PORT
      LAYER metal3 ;
      RECT 0.000 57.415 0.380 57.485 ;
    END
  END cfg_interrupt_msi_pending_status[27]
  PIN cfg_interrupt_msi_pending_status[28]
    DIRECTION INPUT ;
    USE SIGNAL ;
    PORT
      LAYER metal3 ;
      RECT 0.000 57.795 0.380 57.865 ;
    END
  END cfg_interrupt_msi_pending_status[28]
  PIN cfg_interrupt_msi_pending_status[29]
    DIRECTION INPUT ;
    USE SIGNAL ;
    PORT
      LAYER metal3 ;
      RECT 0.000 58.175 0.380 58.245 ;
    END
  END cfg_interrupt_msi_pending_status[29]
  PIN cfg_interrupt_msi_pending_status[30]
    DIRECTION INPUT ;
    USE SIGNAL ;
    PORT
      LAYER metal3 ;
      RECT 0.000 58.555 0.380 58.625 ;
    END
  END cfg_interrupt_msi_pending_status[30]
  PIN cfg_interrupt_msi_pending_status[31]
    DIRECTION INPUT ;
    USE SIGNAL ;
    PORT
      LAYER metal3 ;
      RECT 0.000 58.935 0.380 59.005 ;
    END
  END cfg_interrupt_msi_pending_status[31]
  PIN cfg_interrupt_msi_pending_status_data_enable
    DIRECTION INPUT ;
    USE SIGNAL ;
    PORT
      LAYER metal3 ;
      RECT 0.000 59.315 0.380 59.385 ;
    END
  END cfg_interrupt_msi_pending_status_data_enable
  PIN cfg_interrupt_msi_pending_status_function_num
    DIRECTION INPUT ;
    USE SIGNAL ;
    PORT
      LAYER metal3 ;
      RECT 0.000 59.695 0.380 59.765 ;
    END
  END cfg_interrupt_msi_pending_status_function_num
  PIN cfg_interrupt_msi_select
    DIRECTION INPUT ;
    USE SIGNAL ;
    PORT
      LAYER metal3 ;
      RECT 0.000 60.075 0.380 60.145 ;
    END
  END cfg_interrupt_msi_select
  PIN cfg_interrupt_msi_tph_present
    DIRECTION INPUT ;
    USE SIGNAL ;
    PORT
      LAYER metal3 ;
      RECT 0.000 60.455 0.380 60.525 ;
    END
  END cfg_interrupt_msi_tph_present
  PIN cfg_interrupt_msi_tph_st_tag
    DIRECTION INPUT ;
    USE SIGNAL ;
    PORT
      LAYER metal3 ;
      RECT 0.000 60.835 0.380 60.905 ;
    END
  END cfg_interrupt_msi_tph_st_tag
  PIN cfg_interrupt_msi_tph_type
    DIRECTION INPUT ;
    USE SIGNAL ;
    PORT
      LAYER metal3 ;
      RECT 0.000 61.215 0.380 61.285 ;
    END
  END cfg_interrupt_msi_tph_type
  PIN cfg_interrupt_pending
    DIRECTION INPUT ;
    USE SIGNAL ;
    PORT
      LAYER metal3 ;
      RECT 0.000 61.595 0.380 61.665 ;
    END
  END cfg_interrupt_pending
  PIN cfg_link_training_enable
    DIRECTION INPUT ;
    USE SIGNAL ;
    PORT
      LAYER metal3 ;
      RECT 0.000 61.975 0.380 62.045 ;
    END
  END cfg_link_training_enable
  PIN cfg_mgmt_addr
    DIRECTION INPUT ;
    USE SIGNAL ;
    PORT
      LAYER metal3 ;
      RECT 0.000 62.355 0.380 62.425 ;
    END
  END cfg_mgmt_addr
  PIN cfg_mgmt_byte_enable
    DIRECTION INPUT ;
    USE SIGNAL ;
    PORT
      LAYER metal3 ;
      RECT 0.000 62.735 0.380 62.805 ;
    END
  END cfg_mgmt_byte_enable
  PIN cfg_mgmt_read
    DIRECTION INPUT ;
    USE SIGNAL ;
    PORT
      LAYER metal3 ;
      RECT 0.000 63.115 0.380 63.185 ;
    END
  END cfg_mgmt_read
  PIN cfg_mgmt_type1_cfg_reg_access
    DIRECTION INPUT ;
    USE SIGNAL ;
    PORT
      LAYER metal3 ;
      RECT 0.000 63.495 0.380 63.565 ;
    END
  END cfg_mgmt_type1_cfg_reg_access
  PIN cfg_mgmt_write
    DIRECTION INPUT ;
    USE SIGNAL ;
    PORT
      LAYER metal3 ;
      RECT 0.000 63.875 0.380 63.945 ;
    END
  END cfg_mgmt_write
  PIN cfg_mgmt_write_data
    DIRECTION INPUT ;
    USE SIGNAL ;
    PORT
      LAYER metal3 ;
      RECT 0.000 64.255 0.380 64.325 ;
    END
  END cfg_mgmt_write_data
  PIN cfg_msg_transmit
    DIRECTION INPUT ;
    USE SIGNAL ;
    PORT
      LAYER metal3 ;
      RECT 0.000 64.635 0.380 64.705 ;
    END
  END cfg_msg_transmit
  PIN cfg_msg_transmit_data
    DIRECTION INPUT ;
    USE SIGNAL ;
    PORT
      LAYER metal3 ;
      RECT 0.000 65.015 0.380 65.085 ;
    END
  END cfg_msg_transmit_data
  PIN cfg_msg_transmit_type
    DIRECTION INPUT ;
    USE SIGNAL ;
    PORT
      LAYER metal3 ;
      RECT 0.000 65.395 0.380 65.465 ;
    END
  END cfg_msg_transmit_type
  PIN cfg_per_func_status_control
    DIRECTION INPUT ;
    USE SIGNAL ;
    PORT
      LAYER metal3 ;
      RECT 0.000 65.775 0.380 65.845 ;
    END
  END cfg_per_func_status_control
  PIN cfg_per_function_number
    DIRECTION INPUT ;
    USE SIGNAL ;
    PORT
      LAYER metal3 ;
      RECT 0.000 66.155 0.380 66.225 ;
    END
  END cfg_per_function_number
  PIN cfg_per_function_output_request
    DIRECTION INPUT ;
    USE SIGNAL ;
    PORT
      LAYER metal3 ;
      RECT 0.000 66.535 0.380 66.605 ;
    END
  END cfg_per_function_output_request
  PIN cfg_power_state_change_ack
    DIRECTION INPUT ;
    USE SIGNAL ;
    PORT
      LAYER metal3 ;
      RECT 0.000 66.915 0.380 66.985 ;
    END
  END cfg_power_state_change_ack
  PIN cfg_req_pm_transition_l23_ready
    DIRECTION INPUT ;
    USE SIGNAL ;
    PORT
      LAYER metal3 ;
      RECT 0.000 67.295 0.380 67.365 ;
    END
  END cfg_req_pm_transition_l23_ready
  PIN cfg_subsys_vend_id[0]
    DIRECTION INPUT ;
    USE SIGNAL ;
    PORT
      LAYER metal3 ;
      RECT 0.000 67.675 0.380 67.745 ;
    END
  END cfg_subsys_vend_id[0]
  PIN cfg_subsys_vend_id[1]
    DIRECTION INPUT ;
    USE SIGNAL ;
    PORT
      LAYER metal3 ;
      RECT 0.000 68.055 0.380 68.125 ;
    END
  END cfg_subsys_vend_id[1]
  PIN cfg_subsys_vend_id[2]
    DIRECTION INPUT ;
    USE SIGNAL ;
    PORT
      LAYER metal3 ;
      RECT 0.000 68.435 0.380 68.505 ;
    END
  END cfg_subsys_vend_id[2]
  PIN cfg_subsys_vend_id[3]
    DIRECTION INPUT ;
    USE SIGNAL ;
    PORT
      LAYER metal3 ;
      RECT 0.000 68.815 0.380 68.885 ;
    END
  END cfg_subsys_vend_id[3]
  PIN cfg_subsys_vend_id[4]
    DIRECTION INPUT ;
    USE SIGNAL ;
    PORT
      LAYER metal3 ;
      RECT 0.000 69.195 0.380 69.265 ;
    END
  END cfg_subsys_vend_id[4]
  PIN cfg_subsys_vend_id[5]
    DIRECTION INPUT ;
    USE SIGNAL ;
    PORT
      LAYER metal3 ;
      RECT 0.000 69.575 0.380 69.645 ;
    END
  END cfg_subsys_vend_id[5]
  PIN cfg_subsys_vend_id[6]
    DIRECTION INPUT ;
    USE SIGNAL ;
    PORT
      LAYER metal3 ;
      RECT 0.000 69.955 0.380 70.025 ;
    END
  END cfg_subsys_vend_id[6]
  PIN cfg_subsys_vend_id[7]
    DIRECTION INPUT ;
    USE SIGNAL ;
    PORT
      LAYER metal3 ;
      RECT 0.000 70.335 0.380 70.405 ;
    END
  END cfg_subsys_vend_id[7]
  PIN cfg_subsys_vend_id[8]
    DIRECTION INPUT ;
    USE SIGNAL ;
    PORT
      LAYER metal3 ;
      RECT 0.000 70.715 0.380 70.785 ;
    END
  END cfg_subsys_vend_id[8]
  PIN cfg_subsys_vend_id[9]
    DIRECTION INPUT ;
    USE SIGNAL ;
    PORT
      LAYER metal3 ;
      RECT 0.000 71.095 0.380 71.165 ;
    END
  END cfg_subsys_vend_id[9]
  PIN cfg_subsys_vend_id[10]
    DIRECTION INPUT ;
    USE SIGNAL ;
    PORT
      LAYER metal3 ;
      RECT 0.000 71.475 0.380 71.545 ;
    END
  END cfg_subsys_vend_id[10]
  PIN cfg_subsys_vend_id[11]
    DIRECTION INPUT ;
    USE SIGNAL ;
    PORT
      LAYER metal3 ;
      RECT 0.000 71.855 0.380 71.925 ;
    END
  END cfg_subsys_vend_id[11]
  PIN cfg_subsys_vend_id[12]
    DIRECTION INPUT ;
    USE SIGNAL ;
    PORT
      LAYER metal3 ;
      RECT 0.000 72.235 0.380 72.305 ;
    END
  END cfg_subsys_vend_id[12]
  PIN cfg_vf_flr_done
    DIRECTION INPUT ;
    USE SIGNAL ;
    PORT
      LAYER metal3 ;
      RECT 0.000 72.615 0.380 72.685 ;
    END
  END cfg_vf_flr_done
  PIN m_axis_cq_tready[0]
    DIRECTION INPUT ;
    USE SIGNAL ;
    PORT
      LAYER metal3 ;
      RECT 0.000 72.995 0.380 73.065 ;
    END
  END m_axis_cq_tready[0]
  PIN m_axis_cq_tready[1]
    DIRECTION INPUT ;
    USE SIGNAL ;
    PORT
      LAYER metal3 ;
      RECT 0.000 73.375 0.380 73.445 ;
    END
  END m_axis_cq_tready[1]
  PIN m_axis_cq_tready[2]
    DIRECTION INPUT ;
    USE SIGNAL ;
    PORT
      LAYER metal3 ;
      RECT 0.000 73.755 0.380 73.825 ;
    END
  END m_axis_cq_tready[2]
  PIN m_axis_cq_tready[3]
    DIRECTION INPUT ;
    USE SIGNAL ;
    PORT
      LAYER metal3 ;
      RECT 0.000 74.135 0.380 74.205 ;
    END
  END m_axis_cq_tready[3]
  PIN m_axis_rc_tready[0]
    DIRECTION INPUT ;
    USE SIGNAL ;
    PORT
      LAYER metal3 ;
      RECT 0.000 74.515 0.380 74.585 ;
    END
  END m_axis_rc_tready[0]
  PIN m_axis_rc_tready[1]
    DIRECTION INPUT ;
    USE SIGNAL ;
    PORT
      LAYER metal3 ;
      RECT 0.000 74.895 0.380 74.965 ;
    END
  END m_axis_rc_tready[1]
  PIN m_axis_rc_tready[2]
    DIRECTION INPUT ;
    USE SIGNAL ;
    PORT
      LAYER metal3 ;
      RECT 0.000 75.275 0.380 75.345 ;
    END
  END m_axis_rc_tready[2]
  PIN m_axis_rc_tready[3]
    DIRECTION INPUT ;
    USE SIGNAL ;
    PORT
      LAYER metal3 ;
      RECT 0.000 75.655 0.380 75.725 ;
    END
  END m_axis_rc_tready[3]
  PIN pci_exp_rxn
    DIRECTION INPUT ;
    USE SIGNAL ;
    PORT
      LAYER metal3 ;
      RECT 0.000 76.035 0.380 76.105 ;
    END
  END pci_exp_rxn
  PIN pci_exp_rxp
    DIRECTION INPUT ;
    USE SIGNAL ;
    PORT
      LAYER metal3 ;
      RECT 0.000 76.415 0.380 76.485 ;
    END
  END pci_exp_rxp
  PIN pcie_cq_np_req
    DIRECTION INPUT ;
    USE SIGNAL ;
    PORT
      LAYER metal3 ;
      RECT 0.000 76.795 0.380 76.865 ;
    END
  END pcie_cq_np_req
  PIN pcie_perstn1_in
    DIRECTION INPUT ;
    USE SIGNAL ;
    PORT
      LAYER metal3 ;
      RECT 0.000 77.175 0.380 77.245 ;
    END
  END pcie_perstn1_in
  PIN s_axis_cc_tdata[0]
    DIRECTION INPUT ;
    USE SIGNAL ;
    PORT
      LAYER metal3 ;
      RECT 0.000 77.555 0.380 77.625 ;
    END
  END s_axis_cc_tdata[0]
  PIN s_axis_cc_tdata[1]
    DIRECTION INPUT ;
    USE SIGNAL ;
    PORT
      LAYER metal3 ;
      RECT 0.000 77.935 0.380 78.005 ;
    END
  END s_axis_cc_tdata[1]
  PIN s_axis_cc_tdata[2]
    DIRECTION INPUT ;
    USE SIGNAL ;
    PORT
      LAYER metal3 ;
      RECT 0.000 78.315 0.380 78.385 ;
    END
  END s_axis_cc_tdata[2]
  PIN s_axis_cc_tdata[3]
    DIRECTION INPUT ;
    USE SIGNAL ;
    PORT
      LAYER metal3 ;
      RECT 0.000 78.695 0.380 78.765 ;
    END
  END s_axis_cc_tdata[3]
  PIN s_axis_cc_tdata[4]
    DIRECTION INPUT ;
    USE SIGNAL ;
    PORT
      LAYER metal3 ;
      RECT 0.000 79.075 0.380 79.145 ;
    END
  END s_axis_cc_tdata[4]
  PIN s_axis_cc_tdata[5]
    DIRECTION INPUT ;
    USE SIGNAL ;
    PORT
      LAYER metal3 ;
      RECT 0.000 79.455 0.380 79.525 ;
    END
  END s_axis_cc_tdata[5]
  PIN s_axis_cc_tdata[6]
    DIRECTION INPUT ;
    USE SIGNAL ;
    PORT
      LAYER metal3 ;
      RECT 0.000 79.835 0.380 79.905 ;
    END
  END s_axis_cc_tdata[6]
  PIN s_axis_cc_tdata[7]
    DIRECTION INPUT ;
    USE SIGNAL ;
    PORT
      LAYER metal3 ;
      RECT 0.000 80.215 0.380 80.285 ;
    END
  END s_axis_cc_tdata[7]
  PIN s_axis_cc_tdata[8]
    DIRECTION INPUT ;
    USE SIGNAL ;
    PORT
      LAYER metal3 ;
      RECT 0.000 80.595 0.380 80.665 ;
    END
  END s_axis_cc_tdata[8]
  PIN s_axis_cc_tdata[9]
    DIRECTION INPUT ;
    USE SIGNAL ;
    PORT
      LAYER metal3 ;
      RECT 0.000 80.975 0.380 81.045 ;
    END
  END s_axis_cc_tdata[9]
  PIN s_axis_cc_tdata[10]
    DIRECTION INPUT ;
    USE SIGNAL ;
    PORT
      LAYER metal3 ;
      RECT 0.000 81.355 0.380 81.425 ;
    END
  END s_axis_cc_tdata[10]
  PIN s_axis_cc_tdata[11]
    DIRECTION INPUT ;
    USE SIGNAL ;
    PORT
      LAYER metal3 ;
      RECT 0.000 81.735 0.380 81.805 ;
    END
  END s_axis_cc_tdata[11]
  PIN s_axis_cc_tdata[12]
    DIRECTION INPUT ;
    USE SIGNAL ;
    PORT
      LAYER metal3 ;
      RECT 0.000 82.115 0.380 82.185 ;
    END
  END s_axis_cc_tdata[12]
  PIN s_axis_cc_tdata[13]
    DIRECTION INPUT ;
    USE SIGNAL ;
    PORT
      LAYER metal3 ;
      RECT 0.000 82.495 0.380 82.565 ;
    END
  END s_axis_cc_tdata[13]
  PIN s_axis_cc_tdata[14]
    DIRECTION INPUT ;
    USE SIGNAL ;
    PORT
      LAYER metal3 ;
      RECT 0.000 82.875 0.380 82.945 ;
    END
  END s_axis_cc_tdata[14]
  PIN s_axis_cc_tdata[15]
    DIRECTION INPUT ;
    USE SIGNAL ;
    PORT
      LAYER metal3 ;
      RECT 0.000 83.255 0.380 83.325 ;
    END
  END s_axis_cc_tdata[15]
  PIN s_axis_cc_tdata[16]
    DIRECTION INPUT ;
    USE SIGNAL ;
    PORT
      LAYER metal3 ;
      RECT 0.000 83.635 0.380 83.705 ;
    END
  END s_axis_cc_tdata[16]
  PIN s_axis_cc_tdata[17]
    DIRECTION INPUT ;
    USE SIGNAL ;
    PORT
      LAYER metal3 ;
      RECT 0.000 84.015 0.380 84.085 ;
    END
  END s_axis_cc_tdata[17]
  PIN s_axis_cc_tdata[18]
    DIRECTION INPUT ;
    USE SIGNAL ;
    PORT
      LAYER metal3 ;
      RECT 0.000 84.395 0.380 84.465 ;
    END
  END s_axis_cc_tdata[18]
  PIN s_axis_cc_tdata[19]
    DIRECTION INPUT ;
    USE SIGNAL ;
    PORT
      LAYER metal3 ;
      RECT 0.000 84.775 0.380 84.845 ;
    END
  END s_axis_cc_tdata[19]
  PIN s_axis_cc_tdata[20]
    DIRECTION INPUT ;
    USE SIGNAL ;
    PORT
      LAYER metal3 ;
      RECT 0.000 85.155 0.380 85.225 ;
    END
  END s_axis_cc_tdata[20]
  PIN s_axis_cc_tdata[21]
    DIRECTION INPUT ;
    USE SIGNAL ;
    PORT
      LAYER metal3 ;
      RECT 0.000 85.535 0.380 85.605 ;
    END
  END s_axis_cc_tdata[21]
  PIN s_axis_cc_tdata[22]
    DIRECTION INPUT ;
    USE SIGNAL ;
    PORT
      LAYER metal3 ;
      RECT 0.000 85.915 0.380 85.985 ;
    END
  END s_axis_cc_tdata[22]
  PIN s_axis_cc_tdata[23]
    DIRECTION INPUT ;
    USE SIGNAL ;
    PORT
      LAYER metal3 ;
      RECT 0.000 86.295 0.380 86.365 ;
    END
  END s_axis_cc_tdata[23]
  PIN s_axis_cc_tdata[24]
    DIRECTION INPUT ;
    USE SIGNAL ;
    PORT
      LAYER metal3 ;
      RECT 0.000 86.675 0.380 86.745 ;
    END
  END s_axis_cc_tdata[24]
  PIN s_axis_cc_tdata[25]
    DIRECTION INPUT ;
    USE SIGNAL ;
    PORT
      LAYER metal3 ;
      RECT 0.000 87.055 0.380 87.125 ;
    END
  END s_axis_cc_tdata[25]
  PIN s_axis_cc_tdata[26]
    DIRECTION INPUT ;
    USE SIGNAL ;
    PORT
      LAYER metal3 ;
      RECT 0.000 87.435 0.380 87.505 ;
    END
  END s_axis_cc_tdata[26]
  PIN s_axis_cc_tdata[27]
    DIRECTION INPUT ;
    USE SIGNAL ;
    PORT
      LAYER metal3 ;
      RECT 0.000 87.815 0.380 87.885 ;
    END
  END s_axis_cc_tdata[27]
  PIN s_axis_cc_tdata[28]
    DIRECTION INPUT ;
    USE SIGNAL ;
    PORT
      LAYER metal3 ;
      RECT 0.000 88.195 0.380 88.265 ;
    END
  END s_axis_cc_tdata[28]
  PIN s_axis_cc_tdata[29]
    DIRECTION INPUT ;
    USE SIGNAL ;
    PORT
      LAYER metal3 ;
      RECT 0.000 88.575 0.380 88.645 ;
    END
  END s_axis_cc_tdata[29]
  PIN s_axis_cc_tdata[30]
    DIRECTION INPUT ;
    USE SIGNAL ;
    PORT
      LAYER metal3 ;
      RECT 0.000 88.955 0.380 89.025 ;
    END
  END s_axis_cc_tdata[30]
  PIN s_axis_cc_tdata[31]
    DIRECTION INPUT ;
    USE SIGNAL ;
    PORT
      LAYER metal3 ;
      RECT 0.000 89.335 0.380 89.405 ;
    END
  END s_axis_cc_tdata[31]
  PIN s_axis_cc_tdata[32]
    DIRECTION INPUT ;
    USE SIGNAL ;
    PORT
      LAYER metal3 ;
      RECT 0.000 89.715 0.380 89.785 ;
    END
  END s_axis_cc_tdata[32]
  PIN s_axis_cc_tdata[33]
    DIRECTION INPUT ;
    USE SIGNAL ;
    PORT
      LAYER metal3 ;
      RECT 0.000 90.095 0.380 90.165 ;
    END
  END s_axis_cc_tdata[33]
  PIN s_axis_cc_tdata[34]
    DIRECTION INPUT ;
    USE SIGNAL ;
    PORT
      LAYER metal3 ;
      RECT 0.000 90.475 0.380 90.545 ;
    END
  END s_axis_cc_tdata[34]
  PIN s_axis_cc_tdata[35]
    DIRECTION INPUT ;
    USE SIGNAL ;
    PORT
      LAYER metal3 ;
      RECT 0.000 90.855 0.380 90.925 ;
    END
  END s_axis_cc_tdata[35]
  PIN s_axis_cc_tdata[36]
    DIRECTION INPUT ;
    USE SIGNAL ;
    PORT
      LAYER metal3 ;
      RECT 0.000 91.235 0.380 91.305 ;
    END
  END s_axis_cc_tdata[36]
  PIN s_axis_cc_tdata[37]
    DIRECTION INPUT ;
    USE SIGNAL ;
    PORT
      LAYER metal3 ;
      RECT 0.000 91.615 0.380 91.685 ;
    END
  END s_axis_cc_tdata[37]
  PIN s_axis_cc_tdata[38]
    DIRECTION INPUT ;
    USE SIGNAL ;
    PORT
      LAYER metal3 ;
      RECT 0.000 91.995 0.380 92.065 ;
    END
  END s_axis_cc_tdata[38]
  PIN s_axis_cc_tdata[39]
    DIRECTION INPUT ;
    USE SIGNAL ;
    PORT
      LAYER metal3 ;
      RECT 0.000 92.375 0.380 92.445 ;
    END
  END s_axis_cc_tdata[39]
  PIN s_axis_cc_tdata[40]
    DIRECTION INPUT ;
    USE SIGNAL ;
    PORT
      LAYER metal3 ;
      RECT 0.000 92.755 0.380 92.825 ;
    END
  END s_axis_cc_tdata[40]
  PIN s_axis_cc_tdata[41]
    DIRECTION INPUT ;
    USE SIGNAL ;
    PORT
      LAYER metal3 ;
      RECT 0.000 93.135 0.380 93.205 ;
    END
  END s_axis_cc_tdata[41]
  PIN s_axis_cc_tdata[42]
    DIRECTION INPUT ;
    USE SIGNAL ;
    PORT
      LAYER metal3 ;
      RECT 0.000 93.515 0.380 93.585 ;
    END
  END s_axis_cc_tdata[42]
  PIN s_axis_cc_tdata[43]
    DIRECTION INPUT ;
    USE SIGNAL ;
    PORT
      LAYER metal3 ;
      RECT 0.000 93.895 0.380 93.965 ;
    END
  END s_axis_cc_tdata[43]
  PIN s_axis_cc_tdata[44]
    DIRECTION INPUT ;
    USE SIGNAL ;
    PORT
      LAYER metal3 ;
      RECT 0.000 94.275 0.380 94.345 ;
    END
  END s_axis_cc_tdata[44]
  PIN s_axis_cc_tdata[45]
    DIRECTION INPUT ;
    USE SIGNAL ;
    PORT
      LAYER metal3 ;
      RECT 0.000 94.655 0.380 94.725 ;
    END
  END s_axis_cc_tdata[45]
  PIN s_axis_cc_tdata[46]
    DIRECTION INPUT ;
    USE SIGNAL ;
    PORT
      LAYER metal3 ;
      RECT 0.000 95.035 0.380 95.105 ;
    END
  END s_axis_cc_tdata[46]
  PIN s_axis_cc_tdata[47]
    DIRECTION INPUT ;
    USE SIGNAL ;
    PORT
      LAYER metal3 ;
      RECT 0.000 95.415 0.380 95.485 ;
    END
  END s_axis_cc_tdata[47]
  PIN s_axis_cc_tdata[48]
    DIRECTION INPUT ;
    USE SIGNAL ;
    PORT
      LAYER metal3 ;
      RECT 0.000 95.795 0.380 95.865 ;
    END
  END s_axis_cc_tdata[48]
  PIN s_axis_cc_tdata[49]
    DIRECTION INPUT ;
    USE SIGNAL ;
    PORT
      LAYER metal3 ;
      RECT 0.000 96.175 0.380 96.245 ;
    END
  END s_axis_cc_tdata[49]
  PIN s_axis_cc_tdata[50]
    DIRECTION INPUT ;
    USE SIGNAL ;
    PORT
      LAYER metal3 ;
      RECT 0.000 96.555 0.380 96.625 ;
    END
  END s_axis_cc_tdata[50]
  PIN s_axis_cc_tdata[51]
    DIRECTION INPUT ;
    USE SIGNAL ;
    PORT
      LAYER metal3 ;
      RECT 0.000 96.935 0.380 97.005 ;
    END
  END s_axis_cc_tdata[51]
  PIN s_axis_cc_tdata[52]
    DIRECTION INPUT ;
    USE SIGNAL ;
    PORT
      LAYER metal3 ;
      RECT 0.000 97.315 0.380 97.385 ;
    END
  END s_axis_cc_tdata[52]
  PIN s_axis_cc_tdata[53]
    DIRECTION INPUT ;
    USE SIGNAL ;
    PORT
      LAYER metal3 ;
      RECT 0.000 97.695 0.380 97.765 ;
    END
  END s_axis_cc_tdata[53]
  PIN s_axis_cc_tdata[54]
    DIRECTION INPUT ;
    USE SIGNAL ;
    PORT
      LAYER metal3 ;
      RECT 0.000 98.075 0.380 98.145 ;
    END
  END s_axis_cc_tdata[54]
  PIN s_axis_cc_tdata[55]
    DIRECTION INPUT ;
    USE SIGNAL ;
    PORT
      LAYER metal3 ;
      RECT 0.000 98.455 0.380 98.525 ;
    END
  END s_axis_cc_tdata[55]
  PIN s_axis_cc_tdata[56]
    DIRECTION INPUT ;
    USE SIGNAL ;
    PORT
      LAYER metal3 ;
      RECT 0.000 98.835 0.380 98.905 ;
    END
  END s_axis_cc_tdata[56]
  PIN s_axis_cc_tdata[57]
    DIRECTION INPUT ;
    USE SIGNAL ;
    PORT
      LAYER metal3 ;
      RECT 0.000 99.215 0.380 99.285 ;
    END
  END s_axis_cc_tdata[57]
  PIN s_axis_cc_tdata[58]
    DIRECTION INPUT ;
    USE SIGNAL ;
    PORT
      LAYER metal3 ;
      RECT 0.000 99.595 0.380 99.665 ;
    END
  END s_axis_cc_tdata[58]
  PIN s_axis_cc_tdata[59]
    DIRECTION INPUT ;
    USE SIGNAL ;
    PORT
      LAYER metal3 ;
      RECT 0.000 99.975 0.380 100.045 ;
    END
  END s_axis_cc_tdata[59]
  PIN s_axis_cc_tdata[60]
    DIRECTION INPUT ;
    USE SIGNAL ;
    PORT
      LAYER metal3 ;
      RECT 0.000 100.355 0.380 100.425 ;
    END
  END s_axis_cc_tdata[60]
  PIN s_axis_cc_tdata[61]
    DIRECTION INPUT ;
    USE SIGNAL ;
    PORT
      LAYER metal3 ;
      RECT 0.000 100.735 0.380 100.805 ;
    END
  END s_axis_cc_tdata[61]
  PIN s_axis_cc_tdata[62]
    DIRECTION INPUT ;
    USE SIGNAL ;
    PORT
      LAYER metal3 ;
      RECT 0.000 101.115 0.380 101.185 ;
    END
  END s_axis_cc_tdata[62]
  PIN s_axis_cc_tdata[63]
    DIRECTION INPUT ;
    USE SIGNAL ;
    PORT
      LAYER metal3 ;
      RECT 0.000 101.495 0.380 101.565 ;
    END
  END s_axis_cc_tdata[63]
  PIN s_axis_cc_tdata[64]
    DIRECTION INPUT ;
    USE SIGNAL ;
    PORT
      LAYER metal3 ;
      RECT 0.000 101.875 0.380 101.945 ;
    END
  END s_axis_cc_tdata[64]
  PIN s_axis_cc_tdata[65]
    DIRECTION INPUT ;
    USE SIGNAL ;
    PORT
      LAYER metal3 ;
      RECT 0.000 102.255 0.380 102.325 ;
    END
  END s_axis_cc_tdata[65]
  PIN s_axis_cc_tdata[66]
    DIRECTION INPUT ;
    USE SIGNAL ;
    PORT
      LAYER metal3 ;
      RECT 0.000 102.635 0.380 102.705 ;
    END
  END s_axis_cc_tdata[66]
  PIN s_axis_cc_tdata[67]
    DIRECTION INPUT ;
    USE SIGNAL ;
    PORT
      LAYER metal3 ;
      RECT 0.000 103.015 0.380 103.085 ;
    END
  END s_axis_cc_tdata[67]
  PIN s_axis_cc_tdata[68]
    DIRECTION INPUT ;
    USE SIGNAL ;
    PORT
      LAYER metal3 ;
      RECT 0.000 103.395 0.380 103.465 ;
    END
  END s_axis_cc_tdata[68]
  PIN s_axis_cc_tdata[69]
    DIRECTION INPUT ;
    USE SIGNAL ;
    PORT
      LAYER metal3 ;
      RECT 0.000 103.775 0.380 103.845 ;
    END
  END s_axis_cc_tdata[69]
  PIN s_axis_cc_tdata[70]
    DIRECTION INPUT ;
    USE SIGNAL ;
    PORT
      LAYER metal3 ;
      RECT 0.000 104.155 0.380 104.225 ;
    END
  END s_axis_cc_tdata[70]
  PIN s_axis_cc_tdata[71]
    DIRECTION INPUT ;
    USE SIGNAL ;
    PORT
      LAYER metal3 ;
      RECT 0.000 104.535 0.380 104.605 ;
    END
  END s_axis_cc_tdata[71]
  PIN s_axis_cc_tdata[72]
    DIRECTION INPUT ;
    USE SIGNAL ;
    PORT
      LAYER metal3 ;
      RECT 0.000 104.915 0.380 104.985 ;
    END
  END s_axis_cc_tdata[72]
  PIN s_axis_cc_tdata[73]
    DIRECTION INPUT ;
    USE SIGNAL ;
    PORT
      LAYER metal3 ;
      RECT 0.000 105.295 0.380 105.365 ;
    END
  END s_axis_cc_tdata[73]
  PIN s_axis_cc_tdata[74]
    DIRECTION INPUT ;
    USE SIGNAL ;
    PORT
      LAYER metal3 ;
      RECT 0.000 105.675 0.380 105.745 ;
    END
  END s_axis_cc_tdata[74]
  PIN s_axis_cc_tdata[75]
    DIRECTION INPUT ;
    USE SIGNAL ;
    PORT
      LAYER metal3 ;
      RECT 0.000 106.055 0.380 106.125 ;
    END
  END s_axis_cc_tdata[75]
  PIN s_axis_cc_tdata[76]
    DIRECTION INPUT ;
    USE SIGNAL ;
    PORT
      LAYER metal3 ;
      RECT 0.000 106.435 0.380 106.505 ;
    END
  END s_axis_cc_tdata[76]
  PIN s_axis_cc_tdata[77]
    DIRECTION INPUT ;
    USE SIGNAL ;
    PORT
      LAYER metal3 ;
      RECT 0.000 106.815 0.380 106.885 ;
    END
  END s_axis_cc_tdata[77]
  PIN s_axis_cc_tdata[78]
    DIRECTION INPUT ;
    USE SIGNAL ;
    PORT
      LAYER metal3 ;
      RECT 0.000 107.195 0.380 107.265 ;
    END
  END s_axis_cc_tdata[78]
  PIN s_axis_cc_tdata[79]
    DIRECTION INPUT ;
    USE SIGNAL ;
    PORT
      LAYER metal3 ;
      RECT 0.000 107.575 0.380 107.645 ;
    END
  END s_axis_cc_tdata[79]
  PIN s_axis_cc_tdata[80]
    DIRECTION INPUT ;
    USE SIGNAL ;
    PORT
      LAYER metal3 ;
      RECT 0.000 107.955 0.380 108.025 ;
    END
  END s_axis_cc_tdata[80]
  PIN s_axis_cc_tdata[81]
    DIRECTION INPUT ;
    USE SIGNAL ;
    PORT
      LAYER metal3 ;
      RECT 0.000 108.335 0.380 108.405 ;
    END
  END s_axis_cc_tdata[81]
  PIN s_axis_cc_tdata[82]
    DIRECTION INPUT ;
    USE SIGNAL ;
    PORT
      LAYER metal3 ;
      RECT 0.000 108.715 0.380 108.785 ;
    END
  END s_axis_cc_tdata[82]
  PIN s_axis_cc_tdata[83]
    DIRECTION INPUT ;
    USE SIGNAL ;
    PORT
      LAYER metal3 ;
      RECT 0.000 109.095 0.380 109.165 ;
    END
  END s_axis_cc_tdata[83]
  PIN s_axis_cc_tdata[84]
    DIRECTION INPUT ;
    USE SIGNAL ;
    PORT
      LAYER metal3 ;
      RECT 0.000 109.475 0.380 109.545 ;
    END
  END s_axis_cc_tdata[84]
  PIN s_axis_cc_tdata[85]
    DIRECTION INPUT ;
    USE SIGNAL ;
    PORT
      LAYER metal3 ;
      RECT 0.000 109.855 0.380 109.925 ;
    END
  END s_axis_cc_tdata[85]
  PIN s_axis_cc_tdata[86]
    DIRECTION INPUT ;
    USE SIGNAL ;
    PORT
      LAYER metal3 ;
      RECT 0.000 110.235 0.380 110.305 ;
    END
  END s_axis_cc_tdata[86]
  PIN s_axis_cc_tdata[87]
    DIRECTION INPUT ;
    USE SIGNAL ;
    PORT
      LAYER metal3 ;
      RECT 0.000 110.615 0.380 110.685 ;
    END
  END s_axis_cc_tdata[87]
  PIN s_axis_cc_tdata[88]
    DIRECTION INPUT ;
    USE SIGNAL ;
    PORT
      LAYER metal3 ;
      RECT 0.000 110.995 0.380 111.065 ;
    END
  END s_axis_cc_tdata[88]
  PIN s_axis_cc_tdata[89]
    DIRECTION INPUT ;
    USE SIGNAL ;
    PORT
      LAYER metal3 ;
      RECT 0.000 111.375 0.380 111.445 ;
    END
  END s_axis_cc_tdata[89]
  PIN s_axis_cc_tdata[90]
    DIRECTION INPUT ;
    USE SIGNAL ;
    PORT
      LAYER metal3 ;
      RECT 0.000 111.755 0.380 111.825 ;
    END
  END s_axis_cc_tdata[90]
  PIN s_axis_cc_tdata[91]
    DIRECTION INPUT ;
    USE SIGNAL ;
    PORT
      LAYER metal3 ;
      RECT 0.000 112.135 0.380 112.205 ;
    END
  END s_axis_cc_tdata[91]
  PIN s_axis_cc_tdata[92]
    DIRECTION INPUT ;
    USE SIGNAL ;
    PORT
      LAYER metal3 ;
      RECT 0.000 112.515 0.380 112.585 ;
    END
  END s_axis_cc_tdata[92]
  PIN s_axis_cc_tdata[93]
    DIRECTION INPUT ;
    USE SIGNAL ;
    PORT
      LAYER metal3 ;
      RECT 0.000 112.895 0.380 112.965 ;
    END
  END s_axis_cc_tdata[93]
  PIN s_axis_cc_tdata[94]
    DIRECTION INPUT ;
    USE SIGNAL ;
    PORT
      LAYER metal3 ;
      RECT 0.000 113.275 0.380 113.345 ;
    END
  END s_axis_cc_tdata[94]
  PIN s_axis_cc_tdata[95]
    DIRECTION INPUT ;
    USE SIGNAL ;
    PORT
      LAYER metal3 ;
      RECT 0.000 113.655 0.380 113.725 ;
    END
  END s_axis_cc_tdata[95]
  PIN s_axis_cc_tdata[96]
    DIRECTION INPUT ;
    USE SIGNAL ;
    PORT
      LAYER metal3 ;
      RECT 0.000 114.035 0.380 114.105 ;
    END
  END s_axis_cc_tdata[96]
  PIN s_axis_cc_tdata[97]
    DIRECTION INPUT ;
    USE SIGNAL ;
    PORT
      LAYER metal3 ;
      RECT 0.000 114.415 0.380 114.485 ;
    END
  END s_axis_cc_tdata[97]
  PIN s_axis_cc_tdata[98]
    DIRECTION INPUT ;
    USE SIGNAL ;
    PORT
      LAYER metal3 ;
      RECT 0.000 114.795 0.380 114.865 ;
    END
  END s_axis_cc_tdata[98]
  PIN s_axis_cc_tdata[99]
    DIRECTION INPUT ;
    USE SIGNAL ;
    PORT
      LAYER metal3 ;
      RECT 0.000 115.175 0.380 115.245 ;
    END
  END s_axis_cc_tdata[99]
  PIN s_axis_cc_tdata[100]
    DIRECTION INPUT ;
    USE SIGNAL ;
    PORT
      LAYER metal3 ;
      RECT 0.000 115.555 0.380 115.625 ;
    END
  END s_axis_cc_tdata[100]
  PIN s_axis_cc_tdata[101]
    DIRECTION INPUT ;
    USE SIGNAL ;
    PORT
      LAYER metal3 ;
      RECT 0.000 115.935 0.380 116.005 ;
    END
  END s_axis_cc_tdata[101]
  PIN s_axis_cc_tdata[102]
    DIRECTION INPUT ;
    USE SIGNAL ;
    PORT
      LAYER metal3 ;
      RECT 0.000 116.315 0.380 116.385 ;
    END
  END s_axis_cc_tdata[102]
  PIN s_axis_cc_tdata[103]
    DIRECTION INPUT ;
    USE SIGNAL ;
    PORT
      LAYER metal3 ;
      RECT 0.000 116.695 0.380 116.765 ;
    END
  END s_axis_cc_tdata[103]
  PIN s_axis_cc_tdata[104]
    DIRECTION INPUT ;
    USE SIGNAL ;
    PORT
      LAYER metal3 ;
      RECT 0.000 117.075 0.380 117.145 ;
    END
  END s_axis_cc_tdata[104]
  PIN s_axis_cc_tdata[105]
    DIRECTION INPUT ;
    USE SIGNAL ;
    PORT
      LAYER metal3 ;
      RECT 0.000 117.455 0.380 117.525 ;
    END
  END s_axis_cc_tdata[105]
  PIN s_axis_cc_tdata[106]
    DIRECTION INPUT ;
    USE SIGNAL ;
    PORT
      LAYER metal3 ;
      RECT 0.000 117.835 0.380 117.905 ;
    END
  END s_axis_cc_tdata[106]
  PIN s_axis_cc_tdata[107]
    DIRECTION INPUT ;
    USE SIGNAL ;
    PORT
      LAYER metal3 ;
      RECT 0.000 118.215 0.380 118.285 ;
    END
  END s_axis_cc_tdata[107]
  PIN s_axis_cc_tdata[108]
    DIRECTION INPUT ;
    USE SIGNAL ;
    PORT
      LAYER metal3 ;
      RECT 0.000 118.595 0.380 118.665 ;
    END
  END s_axis_cc_tdata[108]
  PIN s_axis_cc_tdata[109]
    DIRECTION INPUT ;
    USE SIGNAL ;
    PORT
      LAYER metal3 ;
      RECT 0.000 118.975 0.380 119.045 ;
    END
  END s_axis_cc_tdata[109]
  PIN s_axis_cc_tdata[110]
    DIRECTION INPUT ;
    USE SIGNAL ;
    PORT
      LAYER metal3 ;
      RECT 0.000 119.355 0.380 119.425 ;
    END
  END s_axis_cc_tdata[110]
  PIN s_axis_cc_tdata[111]
    DIRECTION INPUT ;
    USE SIGNAL ;
    PORT
      LAYER metal3 ;
      RECT 0.000 119.735 0.380 119.805 ;
    END
  END s_axis_cc_tdata[111]
  PIN s_axis_cc_tdata[112]
    DIRECTION INPUT ;
    USE SIGNAL ;
    PORT
      LAYER metal3 ;
      RECT 0.000 120.115 0.380 120.185 ;
    END
  END s_axis_cc_tdata[112]
  PIN s_axis_cc_tdata[113]
    DIRECTION INPUT ;
    USE SIGNAL ;
    PORT
      LAYER metal3 ;
      RECT 0.000 120.495 0.380 120.565 ;
    END
  END s_axis_cc_tdata[113]
  PIN s_axis_cc_tdata[114]
    DIRECTION INPUT ;
    USE SIGNAL ;
    PORT
      LAYER metal3 ;
      RECT 0.000 120.875 0.380 120.945 ;
    END
  END s_axis_cc_tdata[114]
  PIN s_axis_cc_tdata[115]
    DIRECTION INPUT ;
    USE SIGNAL ;
    PORT
      LAYER metal3 ;
      RECT 0.000 121.255 0.380 121.325 ;
    END
  END s_axis_cc_tdata[115]
  PIN s_axis_cc_tdata[116]
    DIRECTION INPUT ;
    USE SIGNAL ;
    PORT
      LAYER metal3 ;
      RECT 0.000 121.635 0.380 121.705 ;
    END
  END s_axis_cc_tdata[116]
  PIN s_axis_cc_tdata[117]
    DIRECTION INPUT ;
    USE SIGNAL ;
    PORT
      LAYER metal3 ;
      RECT 0.000 122.015 0.380 122.085 ;
    END
  END s_axis_cc_tdata[117]
  PIN s_axis_cc_tdata[118]
    DIRECTION INPUT ;
    USE SIGNAL ;
    PORT
      LAYER metal3 ;
      RECT 0.000 122.395 0.380 122.465 ;
    END
  END s_axis_cc_tdata[118]
  PIN s_axis_cc_tdata[119]
    DIRECTION INPUT ;
    USE SIGNAL ;
    PORT
      LAYER metal3 ;
      RECT 0.000 122.775 0.380 122.845 ;
    END
  END s_axis_cc_tdata[119]
  PIN s_axis_cc_tdata[120]
    DIRECTION INPUT ;
    USE SIGNAL ;
    PORT
      LAYER metal3 ;
      RECT 0.000 123.155 0.380 123.225 ;
    END
  END s_axis_cc_tdata[120]
  PIN s_axis_cc_tdata[121]
    DIRECTION INPUT ;
    USE SIGNAL ;
    PORT
      LAYER metal3 ;
      RECT 0.000 123.535 0.380 123.605 ;
    END
  END s_axis_cc_tdata[121]
  PIN s_axis_cc_tdata[122]
    DIRECTION INPUT ;
    USE SIGNAL ;
    PORT
      LAYER metal3 ;
      RECT 0.000 123.915 0.380 123.985 ;
    END
  END s_axis_cc_tdata[122]
  PIN s_axis_cc_tdata[123]
    DIRECTION INPUT ;
    USE SIGNAL ;
    PORT
      LAYER metal3 ;
      RECT 0.000 124.295 0.380 124.365 ;
    END
  END s_axis_cc_tdata[123]
  PIN s_axis_cc_tdata[124]
    DIRECTION INPUT ;
    USE SIGNAL ;
    PORT
      LAYER metal3 ;
      RECT 0.000 124.675 0.380 124.745 ;
    END
  END s_axis_cc_tdata[124]
  PIN s_axis_cc_tdata[125]
    DIRECTION INPUT ;
    USE SIGNAL ;
    PORT
      LAYER metal3 ;
      RECT 0.000 125.055 0.380 125.125 ;
    END
  END s_axis_cc_tdata[125]
  PIN s_axis_cc_tdata[126]
    DIRECTION INPUT ;
    USE SIGNAL ;
    PORT
      LAYER metal3 ;
      RECT 0.000 125.435 0.380 125.505 ;
    END
  END s_axis_cc_tdata[126]
  PIN s_axis_cc_tdata[127]
    DIRECTION INPUT ;
    USE SIGNAL ;
    PORT
      LAYER metal3 ;
      RECT 0.000 125.815 0.380 125.885 ;
    END
  END s_axis_cc_tdata[127]
  PIN s_axis_cc_tkeep[0]
    DIRECTION INPUT ;
    USE SIGNAL ;
    PORT
      LAYER metal3 ;
      RECT 0.000 126.195 0.380 126.265 ;
    END
  END s_axis_cc_tkeep[0]
  PIN s_axis_cc_tkeep[1]
    DIRECTION INPUT ;
    USE SIGNAL ;
    PORT
      LAYER metal3 ;
      RECT 0.000 126.575 0.380 126.645 ;
    END
  END s_axis_cc_tkeep[1]
  PIN s_axis_cc_tkeep[2]
    DIRECTION INPUT ;
    USE SIGNAL ;
    PORT
      LAYER metal3 ;
      RECT 0.000 126.955 0.380 127.025 ;
    END
  END s_axis_cc_tkeep[2]
  PIN s_axis_cc_tkeep[3]
    DIRECTION INPUT ;
    USE SIGNAL ;
    PORT
      LAYER metal3 ;
      RECT 0.000 127.335 0.380 127.405 ;
    END
  END s_axis_cc_tkeep[3]
  PIN s_axis_cc_tlast
    DIRECTION INPUT ;
    USE SIGNAL ;
    PORT
      LAYER metal3 ;
      RECT 0.000 127.715 0.380 127.785 ;
    END
  END s_axis_cc_tlast
  PIN s_axis_cc_tuser[0]
    DIRECTION INPUT ;
    USE SIGNAL ;
    PORT
      LAYER metal3 ;
      RECT 0.000 128.095 0.380 128.165 ;
    END
  END s_axis_cc_tuser[0]
  PIN s_axis_cc_tuser[1]
    DIRECTION INPUT ;
    USE SIGNAL ;
    PORT
      LAYER metal3 ;
      RECT 0.000 128.475 0.380 128.545 ;
    END
  END s_axis_cc_tuser[1]
  PIN s_axis_cc_tuser[2]
    DIRECTION INPUT ;
    USE SIGNAL ;
    PORT
      LAYER metal3 ;
      RECT 0.000 128.855 0.380 128.925 ;
    END
  END s_axis_cc_tuser[2]
  PIN s_axis_cc_tuser[3]
    DIRECTION INPUT ;
    USE SIGNAL ;
    PORT
      LAYER metal3 ;
      RECT 0.000 129.235 0.380 129.305 ;
    END
  END s_axis_cc_tuser[3]
  PIN s_axis_cc_tuser[4]
    DIRECTION INPUT ;
    USE SIGNAL ;
    PORT
      LAYER metal3 ;
      RECT 0.000 129.615 0.380 129.685 ;
    END
  END s_axis_cc_tuser[4]
  PIN s_axis_cc_tuser[5]
    DIRECTION INPUT ;
    USE SIGNAL ;
    PORT
      LAYER metal3 ;
      RECT 0.000 129.995 0.380 130.065 ;
    END
  END s_axis_cc_tuser[5]
  PIN s_axis_cc_tuser[6]
    DIRECTION INPUT ;
    USE SIGNAL ;
    PORT
      LAYER metal3 ;
      RECT 0.000 130.375 0.380 130.445 ;
    END
  END s_axis_cc_tuser[6]
  PIN s_axis_cc_tuser[7]
    DIRECTION INPUT ;
    USE SIGNAL ;
    PORT
      LAYER metal3 ;
      RECT 0.000 130.755 0.380 130.825 ;
    END
  END s_axis_cc_tuser[7]
  PIN s_axis_cc_tuser[8]
    DIRECTION INPUT ;
    USE SIGNAL ;
    PORT
      LAYER metal3 ;
      RECT 0.000 131.135 0.380 131.205 ;
    END
  END s_axis_cc_tuser[8]
  PIN s_axis_cc_tuser[9]
    DIRECTION INPUT ;
    USE SIGNAL ;
    PORT
      LAYER metal3 ;
      RECT 0.000 131.515 0.380 131.585 ;
    END
  END s_axis_cc_tuser[9]
  PIN s_axis_cc_tuser[10]
    DIRECTION INPUT ;
    USE SIGNAL ;
    PORT
      LAYER metal3 ;
      RECT 0.000 131.895 0.380 131.965 ;
    END
  END s_axis_cc_tuser[10]
  PIN s_axis_cc_tuser[11]
    DIRECTION INPUT ;
    USE SIGNAL ;
    PORT
      LAYER metal3 ;
      RECT 0.000 132.275 0.380 132.345 ;
    END
  END s_axis_cc_tuser[11]
  PIN s_axis_cc_tuser[12]
    DIRECTION INPUT ;
    USE SIGNAL ;
    PORT
      LAYER metal3 ;
      RECT 0.000 132.655 0.380 132.725 ;
    END
  END s_axis_cc_tuser[12]
  PIN s_axis_cc_tuser[13]
    DIRECTION INPUT ;
    USE SIGNAL ;
    PORT
      LAYER metal3 ;
      RECT 0.000 133.035 0.380 133.105 ;
    END
  END s_axis_cc_tuser[13]
  PIN s_axis_cc_tuser[14]
    DIRECTION INPUT ;
    USE SIGNAL ;
    PORT
      LAYER metal3 ;
      RECT 0.000 133.415 0.380 133.485 ;
    END
  END s_axis_cc_tuser[14]
  PIN s_axis_cc_tuser[15]
    DIRECTION INPUT ;
    USE SIGNAL ;
    PORT
      LAYER metal3 ;
      RECT 0.000 133.795 0.380 133.865 ;
    END
  END s_axis_cc_tuser[15]
  PIN s_axis_cc_tuser[16]
    DIRECTION INPUT ;
    USE SIGNAL ;
    PORT
      LAYER metal3 ;
      RECT 0.000 134.175 0.380 134.245 ;
    END
  END s_axis_cc_tuser[16]
  PIN s_axis_cc_tuser[17]
    DIRECTION INPUT ;
    USE SIGNAL ;
    PORT
      LAYER metal3 ;
      RECT 0.000 134.555 0.380 134.625 ;
    END
  END s_axis_cc_tuser[17]
  PIN s_axis_cc_tuser[18]
    DIRECTION INPUT ;
    USE SIGNAL ;
    PORT
      LAYER metal3 ;
      RECT 0.000 134.935 0.380 135.005 ;
    END
  END s_axis_cc_tuser[18]
  PIN s_axis_cc_tuser[19]
    DIRECTION INPUT ;
    USE SIGNAL ;
    PORT
      LAYER metal3 ;
      RECT 0.000 135.315 0.380 135.385 ;
    END
  END s_axis_cc_tuser[19]
  PIN s_axis_cc_tuser[20]
    DIRECTION INPUT ;
    USE SIGNAL ;
    PORT
      LAYER metal3 ;
      RECT 0.000 135.695 0.380 135.765 ;
    END
  END s_axis_cc_tuser[20]
  PIN s_axis_cc_tuser[21]
    DIRECTION INPUT ;
    USE SIGNAL ;
    PORT
      LAYER metal3 ;
      RECT 0.000 136.075 0.380 136.145 ;
    END
  END s_axis_cc_tuser[21]
  PIN s_axis_cc_tuser[22]
    DIRECTION INPUT ;
    USE SIGNAL ;
    PORT
      LAYER metal3 ;
      RECT 0.000 136.455 0.380 136.525 ;
    END
  END s_axis_cc_tuser[22]
  PIN s_axis_cc_tuser[23]
    DIRECTION INPUT ;
    USE SIGNAL ;
    PORT
      LAYER metal3 ;
      RECT 0.000 136.835 0.380 136.905 ;
    END
  END s_axis_cc_tuser[23]
  PIN s_axis_cc_tuser[24]
    DIRECTION INPUT ;
    USE SIGNAL ;
    PORT
      LAYER metal3 ;
      RECT 0.000 137.215 0.380 137.285 ;
    END
  END s_axis_cc_tuser[24]
  PIN s_axis_cc_tuser[25]
    DIRECTION INPUT ;
    USE SIGNAL ;
    PORT
      LAYER metal3 ;
      RECT 0.000 137.595 0.380 137.665 ;
    END
  END s_axis_cc_tuser[25]
  PIN s_axis_cc_tuser[26]
    DIRECTION INPUT ;
    USE SIGNAL ;
    PORT
      LAYER metal3 ;
      RECT 0.000 137.975 0.380 138.045 ;
    END
  END s_axis_cc_tuser[26]
  PIN s_axis_cc_tuser[27]
    DIRECTION INPUT ;
    USE SIGNAL ;
    PORT
      LAYER metal3 ;
      RECT 0.000 138.355 0.380 138.425 ;
    END
  END s_axis_cc_tuser[27]
  PIN s_axis_cc_tuser[28]
    DIRECTION INPUT ;
    USE SIGNAL ;
    PORT
      LAYER metal3 ;
      RECT 0.000 138.735 0.380 138.805 ;
    END
  END s_axis_cc_tuser[28]
  PIN s_axis_cc_tuser[29]
    DIRECTION INPUT ;
    USE SIGNAL ;
    PORT
      LAYER metal3 ;
      RECT 0.000 139.115 0.380 139.185 ;
    END
  END s_axis_cc_tuser[29]
  PIN s_axis_cc_tuser[30]
    DIRECTION INPUT ;
    USE SIGNAL ;
    PORT
      LAYER metal3 ;
      RECT 0.000 139.495 0.380 139.565 ;
    END
  END s_axis_cc_tuser[30]
  PIN s_axis_cc_tuser[31]
    DIRECTION INPUT ;
    USE SIGNAL ;
    PORT
      LAYER metal3 ;
      RECT 0.000 139.875 0.380 139.945 ;
    END
  END s_axis_cc_tuser[31]
  PIN s_axis_cc_tuser[32]
    DIRECTION INPUT ;
    USE SIGNAL ;
    PORT
      LAYER metal3 ;
      RECT 0.000 140.255 0.380 140.325 ;
    END
  END s_axis_cc_tuser[32]
  PIN s_axis_cc_tvalid
    DIRECTION INPUT ;
    USE SIGNAL ;
    PORT
      LAYER metal3 ;
      RECT 0.000 140.635 0.380 140.705 ;
    END
  END s_axis_cc_tvalid
  PIN s_axis_rq_tdata[0]
    DIRECTION INPUT ;
    USE SIGNAL ;
    PORT
      LAYER metal3 ;
      RECT 0.000 141.015 0.380 141.085 ;
    END
  END s_axis_rq_tdata[0]
  PIN s_axis_rq_tdata[1]
    DIRECTION INPUT ;
    USE SIGNAL ;
    PORT
      LAYER metal3 ;
      RECT 0.000 141.395 0.380 141.465 ;
    END
  END s_axis_rq_tdata[1]
  PIN s_axis_rq_tdata[2]
    DIRECTION INPUT ;
    USE SIGNAL ;
    PORT
      LAYER metal3 ;
      RECT 0.000 141.775 0.380 141.845 ;
    END
  END s_axis_rq_tdata[2]
  PIN s_axis_rq_tdata[3]
    DIRECTION INPUT ;
    USE SIGNAL ;
    PORT
      LAYER metal3 ;
      RECT 0.000 142.155 0.380 142.225 ;
    END
  END s_axis_rq_tdata[3]
  PIN s_axis_rq_tdata[4]
    DIRECTION INPUT ;
    USE SIGNAL ;
    PORT
      LAYER metal3 ;
      RECT 0.000 142.535 0.380 142.605 ;
    END
  END s_axis_rq_tdata[4]
  PIN s_axis_rq_tdata[5]
    DIRECTION INPUT ;
    USE SIGNAL ;
    PORT
      LAYER metal3 ;
      RECT 0.000 142.915 0.380 142.985 ;
    END
  END s_axis_rq_tdata[5]
  PIN s_axis_rq_tdata[6]
    DIRECTION INPUT ;
    USE SIGNAL ;
    PORT
      LAYER metal3 ;
      RECT 0.000 143.295 0.380 143.365 ;
    END
  END s_axis_rq_tdata[6]
  PIN s_axis_rq_tdata[7]
    DIRECTION INPUT ;
    USE SIGNAL ;
    PORT
      LAYER metal3 ;
      RECT 0.000 143.675 0.380 143.745 ;
    END
  END s_axis_rq_tdata[7]
  PIN s_axis_rq_tdata[8]
    DIRECTION INPUT ;
    USE SIGNAL ;
    PORT
      LAYER metal3 ;
      RECT 0.000 144.055 0.380 144.125 ;
    END
  END s_axis_rq_tdata[8]
  PIN s_axis_rq_tdata[9]
    DIRECTION INPUT ;
    USE SIGNAL ;
    PORT
      LAYER metal3 ;
      RECT 0.000 144.435 0.380 144.505 ;
    END
  END s_axis_rq_tdata[9]
  PIN s_axis_rq_tdata[10]
    DIRECTION INPUT ;
    USE SIGNAL ;
    PORT
      LAYER metal3 ;
      RECT 0.000 144.815 0.380 144.885 ;
    END
  END s_axis_rq_tdata[10]
  PIN s_axis_rq_tdata[11]
    DIRECTION INPUT ;
    USE SIGNAL ;
    PORT
      LAYER metal3 ;
      RECT 0.000 145.195 0.380 145.265 ;
    END
  END s_axis_rq_tdata[11]
  PIN s_axis_rq_tdata[12]
    DIRECTION INPUT ;
    USE SIGNAL ;
    PORT
      LAYER metal3 ;
      RECT 0.000 145.575 0.380 145.645 ;
    END
  END s_axis_rq_tdata[12]
  PIN s_axis_rq_tdata[13]
    DIRECTION INPUT ;
    USE SIGNAL ;
    PORT
      LAYER metal3 ;
      RECT 0.000 145.955 0.380 146.025 ;
    END
  END s_axis_rq_tdata[13]
  PIN s_axis_rq_tdata[14]
    DIRECTION INPUT ;
    USE SIGNAL ;
    PORT
      LAYER metal3 ;
      RECT 0.000 146.335 0.380 146.405 ;
    END
  END s_axis_rq_tdata[14]
  PIN s_axis_rq_tdata[15]
    DIRECTION INPUT ;
    USE SIGNAL ;
    PORT
      LAYER metal3 ;
      RECT 0.000 146.715 0.380 146.785 ;
    END
  END s_axis_rq_tdata[15]
  PIN s_axis_rq_tdata[16]
    DIRECTION INPUT ;
    USE SIGNAL ;
    PORT
      LAYER metal3 ;
      RECT 0.000 147.095 0.380 147.165 ;
    END
  END s_axis_rq_tdata[16]
  PIN s_axis_rq_tdata[17]
    DIRECTION INPUT ;
    USE SIGNAL ;
    PORT
      LAYER metal3 ;
      RECT 0.000 147.475 0.380 147.545 ;
    END
  END s_axis_rq_tdata[17]
  PIN s_axis_rq_tdata[18]
    DIRECTION INPUT ;
    USE SIGNAL ;
    PORT
      LAYER metal3 ;
      RECT 0.000 147.855 0.380 147.925 ;
    END
  END s_axis_rq_tdata[18]
  PIN s_axis_rq_tdata[19]
    DIRECTION INPUT ;
    USE SIGNAL ;
    PORT
      LAYER metal3 ;
      RECT 0.000 148.235 0.380 148.305 ;
    END
  END s_axis_rq_tdata[19]
  PIN s_axis_rq_tdata[20]
    DIRECTION INPUT ;
    USE SIGNAL ;
    PORT
      LAYER metal3 ;
      RECT 0.000 148.615 0.380 148.685 ;
    END
  END s_axis_rq_tdata[20]
  PIN s_axis_rq_tdata[21]
    DIRECTION INPUT ;
    USE SIGNAL ;
    PORT
      LAYER metal3 ;
      RECT 0.000 148.995 0.380 149.065 ;
    END
  END s_axis_rq_tdata[21]
  PIN s_axis_rq_tdata[22]
    DIRECTION INPUT ;
    USE SIGNAL ;
    PORT
      LAYER metal3 ;
      RECT 0.000 149.375 0.380 149.445 ;
    END
  END s_axis_rq_tdata[22]
  PIN s_axis_rq_tdata[23]
    DIRECTION INPUT ;
    USE SIGNAL ;
    PORT
      LAYER metal3 ;
      RECT 0.000 149.755 0.380 149.825 ;
    END
  END s_axis_rq_tdata[23]
  PIN s_axis_rq_tdata[24]
    DIRECTION INPUT ;
    USE SIGNAL ;
    PORT
      LAYER metal3 ;
      RECT 0.000 150.135 0.380 150.205 ;
    END
  END s_axis_rq_tdata[24]
  PIN s_axis_rq_tdata[25]
    DIRECTION INPUT ;
    USE SIGNAL ;
    PORT
      LAYER metal3 ;
      RECT 0.000 150.515 0.380 150.585 ;
    END
  END s_axis_rq_tdata[25]
  PIN s_axis_rq_tdata[26]
    DIRECTION INPUT ;
    USE SIGNAL ;
    PORT
      LAYER metal3 ;
      RECT 0.000 150.895 0.380 150.965 ;
    END
  END s_axis_rq_tdata[26]
  PIN s_axis_rq_tdata[27]
    DIRECTION INPUT ;
    USE SIGNAL ;
    PORT
      LAYER metal3 ;
      RECT 0.000 151.275 0.380 151.345 ;
    END
  END s_axis_rq_tdata[27]
  PIN s_axis_rq_tdata[28]
    DIRECTION INPUT ;
    USE SIGNAL ;
    PORT
      LAYER metal3 ;
      RECT 0.000 151.655 0.380 151.725 ;
    END
  END s_axis_rq_tdata[28]
  PIN s_axis_rq_tdata[29]
    DIRECTION INPUT ;
    USE SIGNAL ;
    PORT
      LAYER metal3 ;
      RECT 0.000 152.035 0.380 152.105 ;
    END
  END s_axis_rq_tdata[29]
  PIN s_axis_rq_tdata[30]
    DIRECTION INPUT ;
    USE SIGNAL ;
    PORT
      LAYER metal3 ;
      RECT 0.000 152.415 0.380 152.485 ;
    END
  END s_axis_rq_tdata[30]
  PIN s_axis_rq_tdata[31]
    DIRECTION INPUT ;
    USE SIGNAL ;
    PORT
      LAYER metal3 ;
      RECT 0.000 152.795 0.380 152.865 ;
    END
  END s_axis_rq_tdata[31]
  PIN s_axis_rq_tdata[32]
    DIRECTION INPUT ;
    USE SIGNAL ;
    PORT
      LAYER metal3 ;
      RECT 0.000 153.175 0.380 153.245 ;
    END
  END s_axis_rq_tdata[32]
  PIN s_axis_rq_tdata[33]
    DIRECTION INPUT ;
    USE SIGNAL ;
    PORT
      LAYER metal3 ;
      RECT 0.000 153.555 0.380 153.625 ;
    END
  END s_axis_rq_tdata[33]
  PIN s_axis_rq_tdata[34]
    DIRECTION INPUT ;
    USE SIGNAL ;
    PORT
      LAYER metal3 ;
      RECT 0.000 153.935 0.380 154.005 ;
    END
  END s_axis_rq_tdata[34]
  PIN s_axis_rq_tdata[35]
    DIRECTION INPUT ;
    USE SIGNAL ;
    PORT
      LAYER metal3 ;
      RECT 0.000 154.315 0.380 154.385 ;
    END
  END s_axis_rq_tdata[35]
  PIN s_axis_rq_tdata[36]
    DIRECTION INPUT ;
    USE SIGNAL ;
    PORT
      LAYER metal3 ;
      RECT 0.000 154.695 0.380 154.765 ;
    END
  END s_axis_rq_tdata[36]
  PIN s_axis_rq_tdata[37]
    DIRECTION INPUT ;
    USE SIGNAL ;
    PORT
      LAYER metal3 ;
      RECT 0.000 155.075 0.380 155.145 ;
    END
  END s_axis_rq_tdata[37]
  PIN s_axis_rq_tdata[38]
    DIRECTION INPUT ;
    USE SIGNAL ;
    PORT
      LAYER metal3 ;
      RECT 0.000 155.455 0.380 155.525 ;
    END
  END s_axis_rq_tdata[38]
  PIN s_axis_rq_tdata[39]
    DIRECTION INPUT ;
    USE SIGNAL ;
    PORT
      LAYER metal3 ;
      RECT 0.000 155.835 0.380 155.905 ;
    END
  END s_axis_rq_tdata[39]
  PIN s_axis_rq_tdata[40]
    DIRECTION INPUT ;
    USE SIGNAL ;
    PORT
      LAYER metal3 ;
      RECT 0.000 156.215 0.380 156.285 ;
    END
  END s_axis_rq_tdata[40]
  PIN s_axis_rq_tdata[41]
    DIRECTION INPUT ;
    USE SIGNAL ;
    PORT
      LAYER metal3 ;
      RECT 0.000 156.595 0.380 156.665 ;
    END
  END s_axis_rq_tdata[41]
  PIN s_axis_rq_tdata[42]
    DIRECTION INPUT ;
    USE SIGNAL ;
    PORT
      LAYER metal3 ;
      RECT 0.000 156.975 0.380 157.045 ;
    END
  END s_axis_rq_tdata[42]
  PIN s_axis_rq_tdata[43]
    DIRECTION INPUT ;
    USE SIGNAL ;
    PORT
      LAYER metal3 ;
      RECT 0.000 157.355 0.380 157.425 ;
    END
  END s_axis_rq_tdata[43]
  PIN s_axis_rq_tdata[44]
    DIRECTION INPUT ;
    USE SIGNAL ;
    PORT
      LAYER metal3 ;
      RECT 0.000 157.735 0.380 157.805 ;
    END
  END s_axis_rq_tdata[44]
  PIN s_axis_rq_tdata[45]
    DIRECTION INPUT ;
    USE SIGNAL ;
    PORT
      LAYER metal3 ;
      RECT 0.000 158.115 0.380 158.185 ;
    END
  END s_axis_rq_tdata[45]
  PIN s_axis_rq_tdata[46]
    DIRECTION INPUT ;
    USE SIGNAL ;
    PORT
      LAYER metal3 ;
      RECT 0.000 158.495 0.380 158.565 ;
    END
  END s_axis_rq_tdata[46]
  PIN s_axis_rq_tdata[47]
    DIRECTION INPUT ;
    USE SIGNAL ;
    PORT
      LAYER metal3 ;
      RECT 0.000 158.875 0.380 158.945 ;
    END
  END s_axis_rq_tdata[47]
  PIN s_axis_rq_tdata[48]
    DIRECTION INPUT ;
    USE SIGNAL ;
    PORT
      LAYER metal3 ;
      RECT 0.000 159.255 0.380 159.325 ;
    END
  END s_axis_rq_tdata[48]
  PIN s_axis_rq_tdata[49]
    DIRECTION INPUT ;
    USE SIGNAL ;
    PORT
      LAYER metal3 ;
      RECT 0.000 159.635 0.380 159.705 ;
    END
  END s_axis_rq_tdata[49]
  PIN s_axis_rq_tdata[50]
    DIRECTION INPUT ;
    USE SIGNAL ;
    PORT
      LAYER metal3 ;
      RECT 0.000 160.015 0.380 160.085 ;
    END
  END s_axis_rq_tdata[50]
  PIN s_axis_rq_tdata[51]
    DIRECTION INPUT ;
    USE SIGNAL ;
    PORT
      LAYER metal3 ;
      RECT 0.000 160.395 0.380 160.465 ;
    END
  END s_axis_rq_tdata[51]
  PIN s_axis_rq_tdata[52]
    DIRECTION INPUT ;
    USE SIGNAL ;
    PORT
      LAYER metal3 ;
      RECT 0.000 160.775 0.380 160.845 ;
    END
  END s_axis_rq_tdata[52]
  PIN s_axis_rq_tdata[53]
    DIRECTION INPUT ;
    USE SIGNAL ;
    PORT
      LAYER metal3 ;
      RECT 0.000 161.155 0.380 161.225 ;
    END
  END s_axis_rq_tdata[53]
  PIN s_axis_rq_tdata[54]
    DIRECTION INPUT ;
    USE SIGNAL ;
    PORT
      LAYER metal3 ;
      RECT 0.000 161.535 0.380 161.605 ;
    END
  END s_axis_rq_tdata[54]
  PIN s_axis_rq_tdata[55]
    DIRECTION INPUT ;
    USE SIGNAL ;
    PORT
      LAYER metal3 ;
      RECT 0.000 161.915 0.380 161.985 ;
    END
  END s_axis_rq_tdata[55]
  PIN s_axis_rq_tdata[56]
    DIRECTION INPUT ;
    USE SIGNAL ;
    PORT
      LAYER metal3 ;
      RECT 0.000 162.295 0.380 162.365 ;
    END
  END s_axis_rq_tdata[56]
  PIN s_axis_rq_tdata[57]
    DIRECTION INPUT ;
    USE SIGNAL ;
    PORT
      LAYER metal3 ;
      RECT 0.000 162.675 0.380 162.745 ;
    END
  END s_axis_rq_tdata[57]
  PIN s_axis_rq_tdata[58]
    DIRECTION INPUT ;
    USE SIGNAL ;
    PORT
      LAYER metal3 ;
      RECT 0.000 163.055 0.380 163.125 ;
    END
  END s_axis_rq_tdata[58]
  PIN s_axis_rq_tdata[59]
    DIRECTION INPUT ;
    USE SIGNAL ;
    PORT
      LAYER metal3 ;
      RECT 0.000 163.435 0.380 163.505 ;
    END
  END s_axis_rq_tdata[59]
  PIN s_axis_rq_tdata[60]
    DIRECTION INPUT ;
    USE SIGNAL ;
    PORT
      LAYER metal3 ;
      RECT 0.000 163.815 0.380 163.885 ;
    END
  END s_axis_rq_tdata[60]
  PIN s_axis_rq_tdata[61]
    DIRECTION INPUT ;
    USE SIGNAL ;
    PORT
      LAYER metal3 ;
      RECT 0.000 164.195 0.380 164.265 ;
    END
  END s_axis_rq_tdata[61]
  PIN s_axis_rq_tdata[62]
    DIRECTION INPUT ;
    USE SIGNAL ;
    PORT
      LAYER metal3 ;
      RECT 0.000 164.575 0.380 164.645 ;
    END
  END s_axis_rq_tdata[62]
  PIN s_axis_rq_tdata[63]
    DIRECTION INPUT ;
    USE SIGNAL ;
    PORT
      LAYER metal3 ;
      RECT 0.000 164.955 0.380 165.025 ;
    END
  END s_axis_rq_tdata[63]
  PIN s_axis_rq_tdata[64]
    DIRECTION INPUT ;
    USE SIGNAL ;
    PORT
      LAYER metal3 ;
      RECT 0.000 165.335 0.380 165.405 ;
    END
  END s_axis_rq_tdata[64]
  PIN s_axis_rq_tdata[65]
    DIRECTION INPUT ;
    USE SIGNAL ;
    PORT
      LAYER metal3 ;
      RECT 0.000 165.715 0.380 165.785 ;
    END
  END s_axis_rq_tdata[65]
  PIN s_axis_rq_tdata[66]
    DIRECTION INPUT ;
    USE SIGNAL ;
    PORT
      LAYER metal3 ;
      RECT 0.000 166.095 0.380 166.165 ;
    END
  END s_axis_rq_tdata[66]
  PIN s_axis_rq_tdata[67]
    DIRECTION INPUT ;
    USE SIGNAL ;
    PORT
      LAYER metal3 ;
      RECT 0.000 166.475 0.380 166.545 ;
    END
  END s_axis_rq_tdata[67]
  PIN s_axis_rq_tdata[68]
    DIRECTION INPUT ;
    USE SIGNAL ;
    PORT
      LAYER metal3 ;
      RECT 0.000 166.855 0.380 166.925 ;
    END
  END s_axis_rq_tdata[68]
  PIN s_axis_rq_tdata[69]
    DIRECTION INPUT ;
    USE SIGNAL ;
    PORT
      LAYER metal3 ;
      RECT 0.000 167.235 0.380 167.305 ;
    END
  END s_axis_rq_tdata[69]
  PIN s_axis_rq_tdata[70]
    DIRECTION INPUT ;
    USE SIGNAL ;
    PORT
      LAYER metal3 ;
      RECT 0.000 167.615 0.380 167.685 ;
    END
  END s_axis_rq_tdata[70]
  PIN s_axis_rq_tdata[71]
    DIRECTION INPUT ;
    USE SIGNAL ;
    PORT
      LAYER metal3 ;
      RECT 0.000 167.995 0.380 168.065 ;
    END
  END s_axis_rq_tdata[71]
  PIN s_axis_rq_tdata[72]
    DIRECTION INPUT ;
    USE SIGNAL ;
    PORT
      LAYER metal3 ;
      RECT 0.000 168.375 0.380 168.445 ;
    END
  END s_axis_rq_tdata[72]
  PIN s_axis_rq_tdata[73]
    DIRECTION INPUT ;
    USE SIGNAL ;
    PORT
      LAYER metal3 ;
      RECT 0.000 168.755 0.380 168.825 ;
    END
  END s_axis_rq_tdata[73]
  PIN s_axis_rq_tdata[74]
    DIRECTION INPUT ;
    USE SIGNAL ;
    PORT
      LAYER metal3 ;
      RECT 0.000 169.135 0.380 169.205 ;
    END
  END s_axis_rq_tdata[74]
  PIN s_axis_rq_tdata[75]
    DIRECTION INPUT ;
    USE SIGNAL ;
    PORT
      LAYER metal3 ;
      RECT 0.000 169.515 0.380 169.585 ;
    END
  END s_axis_rq_tdata[75]
  PIN s_axis_rq_tdata[76]
    DIRECTION INPUT ;
    USE SIGNAL ;
    PORT
      LAYER metal3 ;
      RECT 0.000 169.895 0.380 169.965 ;
    END
  END s_axis_rq_tdata[76]
  PIN s_axis_rq_tdata[77]
    DIRECTION INPUT ;
    USE SIGNAL ;
    PORT
      LAYER metal3 ;
      RECT 0.000 170.275 0.380 170.345 ;
    END
  END s_axis_rq_tdata[77]
  PIN s_axis_rq_tdata[78]
    DIRECTION INPUT ;
    USE SIGNAL ;
    PORT
      LAYER metal3 ;
      RECT 0.000 170.655 0.380 170.725 ;
    END
  END s_axis_rq_tdata[78]
  PIN s_axis_rq_tdata[79]
    DIRECTION INPUT ;
    USE SIGNAL ;
    PORT
      LAYER metal3 ;
      RECT 0.000 171.035 0.380 171.105 ;
    END
  END s_axis_rq_tdata[79]
  PIN s_axis_rq_tdata[80]
    DIRECTION INPUT ;
    USE SIGNAL ;
    PORT
      LAYER metal3 ;
      RECT 0.000 171.415 0.380 171.485 ;
    END
  END s_axis_rq_tdata[80]
  PIN s_axis_rq_tdata[81]
    DIRECTION INPUT ;
    USE SIGNAL ;
    PORT
      LAYER metal3 ;
      RECT 0.000 171.795 0.380 171.865 ;
    END
  END s_axis_rq_tdata[81]
  PIN s_axis_rq_tdata[82]
    DIRECTION INPUT ;
    USE SIGNAL ;
    PORT
      LAYER metal3 ;
      RECT 0.000 172.175 0.380 172.245 ;
    END
  END s_axis_rq_tdata[82]
  PIN s_axis_rq_tdata[83]
    DIRECTION INPUT ;
    USE SIGNAL ;
    PORT
      LAYER metal3 ;
      RECT 0.000 172.555 0.380 172.625 ;
    END
  END s_axis_rq_tdata[83]
  PIN s_axis_rq_tdata[84]
    DIRECTION INPUT ;
    USE SIGNAL ;
    PORT
      LAYER metal3 ;
      RECT 0.000 172.935 0.380 173.005 ;
    END
  END s_axis_rq_tdata[84]
  PIN s_axis_rq_tdata[85]
    DIRECTION INPUT ;
    USE SIGNAL ;
    PORT
      LAYER metal3 ;
      RECT 0.000 173.315 0.380 173.385 ;
    END
  END s_axis_rq_tdata[85]
  PIN s_axis_rq_tdata[86]
    DIRECTION INPUT ;
    USE SIGNAL ;
    PORT
      LAYER metal3 ;
      RECT 0.000 173.695 0.380 173.765 ;
    END
  END s_axis_rq_tdata[86]
  PIN s_axis_rq_tdata[87]
    DIRECTION INPUT ;
    USE SIGNAL ;
    PORT
      LAYER metal3 ;
      RECT 0.000 174.075 0.380 174.145 ;
    END
  END s_axis_rq_tdata[87]
  PIN s_axis_rq_tdata[88]
    DIRECTION INPUT ;
    USE SIGNAL ;
    PORT
      LAYER metal3 ;
      RECT 0.000 174.455 0.380 174.525 ;
    END
  END s_axis_rq_tdata[88]
  PIN s_axis_rq_tdata[89]
    DIRECTION INPUT ;
    USE SIGNAL ;
    PORT
      LAYER metal3 ;
      RECT 0.000 174.835 0.380 174.905 ;
    END
  END s_axis_rq_tdata[89]
  PIN s_axis_rq_tdata[90]
    DIRECTION INPUT ;
    USE SIGNAL ;
    PORT
      LAYER metal3 ;
      RECT 0.000 175.215 0.380 175.285 ;
    END
  END s_axis_rq_tdata[90]
  PIN s_axis_rq_tdata[91]
    DIRECTION INPUT ;
    USE SIGNAL ;
    PORT
      LAYER metal3 ;
      RECT 0.000 175.595 0.380 175.665 ;
    END
  END s_axis_rq_tdata[91]
  PIN s_axis_rq_tdata[92]
    DIRECTION INPUT ;
    USE SIGNAL ;
    PORT
      LAYER metal3 ;
      RECT 0.000 175.975 0.380 176.045 ;
    END
  END s_axis_rq_tdata[92]
  PIN s_axis_rq_tdata[93]
    DIRECTION INPUT ;
    USE SIGNAL ;
    PORT
      LAYER metal3 ;
      RECT 0.000 176.355 0.380 176.425 ;
    END
  END s_axis_rq_tdata[93]
  PIN s_axis_rq_tdata[94]
    DIRECTION INPUT ;
    USE SIGNAL ;
    PORT
      LAYER metal3 ;
      RECT 0.000 176.735 0.380 176.805 ;
    END
  END s_axis_rq_tdata[94]
  PIN s_axis_rq_tdata[95]
    DIRECTION INPUT ;
    USE SIGNAL ;
    PORT
      LAYER metal3 ;
      RECT 0.000 177.115 0.380 177.185 ;
    END
  END s_axis_rq_tdata[95]
  PIN s_axis_rq_tdata[96]
    DIRECTION INPUT ;
    USE SIGNAL ;
    PORT
      LAYER metal3 ;
      RECT 0.000 177.495 0.380 177.565 ;
    END
  END s_axis_rq_tdata[96]
  PIN s_axis_rq_tdata[97]
    DIRECTION INPUT ;
    USE SIGNAL ;
    PORT
      LAYER metal3 ;
      RECT 0.000 177.875 0.380 177.945 ;
    END
  END s_axis_rq_tdata[97]
  PIN s_axis_rq_tdata[98]
    DIRECTION INPUT ;
    USE SIGNAL ;
    PORT
      LAYER metal3 ;
      RECT 0.000 178.255 0.380 178.325 ;
    END
  END s_axis_rq_tdata[98]
  PIN s_axis_rq_tdata[99]
    DIRECTION INPUT ;
    USE SIGNAL ;
    PORT
      LAYER metal3 ;
      RECT 0.000 178.635 0.380 178.705 ;
    END
  END s_axis_rq_tdata[99]
  PIN s_axis_rq_tdata[100]
    DIRECTION INPUT ;
    USE SIGNAL ;
    PORT
      LAYER metal3 ;
      RECT 0.000 179.015 0.380 179.085 ;
    END
  END s_axis_rq_tdata[100]
  PIN s_axis_rq_tdata[101]
    DIRECTION INPUT ;
    USE SIGNAL ;
    PORT
      LAYER metal3 ;
      RECT 0.000 179.395 0.380 179.465 ;
    END
  END s_axis_rq_tdata[101]
  PIN s_axis_rq_tdata[102]
    DIRECTION INPUT ;
    USE SIGNAL ;
    PORT
      LAYER metal3 ;
      RECT 0.000 179.775 0.380 179.845 ;
    END
  END s_axis_rq_tdata[102]
  PIN s_axis_rq_tdata[103]
    DIRECTION INPUT ;
    USE SIGNAL ;
    PORT
      LAYER metal3 ;
      RECT 0.000 180.155 0.380 180.225 ;
    END
  END s_axis_rq_tdata[103]
  PIN s_axis_rq_tdata[104]
    DIRECTION INPUT ;
    USE SIGNAL ;
    PORT
      LAYER metal3 ;
      RECT 0.000 180.535 0.380 180.605 ;
    END
  END s_axis_rq_tdata[104]
  PIN s_axis_rq_tdata[105]
    DIRECTION INPUT ;
    USE SIGNAL ;
    PORT
      LAYER metal3 ;
      RECT 0.000 180.915 0.380 180.985 ;
    END
  END s_axis_rq_tdata[105]
  PIN s_axis_rq_tdata[106]
    DIRECTION INPUT ;
    USE SIGNAL ;
    PORT
      LAYER metal3 ;
      RECT 0.000 181.295 0.380 181.365 ;
    END
  END s_axis_rq_tdata[106]
  PIN s_axis_rq_tdata[107]
    DIRECTION INPUT ;
    USE SIGNAL ;
    PORT
      LAYER metal3 ;
      RECT 0.000 181.675 0.380 181.745 ;
    END
  END s_axis_rq_tdata[107]
  PIN s_axis_rq_tdata[108]
    DIRECTION INPUT ;
    USE SIGNAL ;
    PORT
      LAYER metal3 ;
      RECT 0.000 182.055 0.380 182.125 ;
    END
  END s_axis_rq_tdata[108]
  PIN s_axis_rq_tdata[109]
    DIRECTION INPUT ;
    USE SIGNAL ;
    PORT
      LAYER metal3 ;
      RECT 0.000 182.435 0.380 182.505 ;
    END
  END s_axis_rq_tdata[109]
  PIN s_axis_rq_tdata[110]
    DIRECTION INPUT ;
    USE SIGNAL ;
    PORT
      LAYER metal3 ;
      RECT 0.000 182.815 0.380 182.885 ;
    END
  END s_axis_rq_tdata[110]
  PIN s_axis_rq_tdata[111]
    DIRECTION INPUT ;
    USE SIGNAL ;
    PORT
      LAYER metal3 ;
      RECT 0.000 183.195 0.380 183.265 ;
    END
  END s_axis_rq_tdata[111]
  PIN s_axis_rq_tdata[112]
    DIRECTION INPUT ;
    USE SIGNAL ;
    PORT
      LAYER metal3 ;
      RECT 0.000 183.575 0.380 183.645 ;
    END
  END s_axis_rq_tdata[112]
  PIN s_axis_rq_tdata[113]
    DIRECTION INPUT ;
    USE SIGNAL ;
    PORT
      LAYER metal3 ;
      RECT 0.000 183.955 0.380 184.025 ;
    END
  END s_axis_rq_tdata[113]
  PIN s_axis_rq_tdata[114]
    DIRECTION INPUT ;
    USE SIGNAL ;
    PORT
      LAYER metal3 ;
      RECT 0.000 184.335 0.380 184.405 ;
    END
  END s_axis_rq_tdata[114]
  PIN s_axis_rq_tdata[115]
    DIRECTION INPUT ;
    USE SIGNAL ;
    PORT
      LAYER metal3 ;
      RECT 0.000 184.715 0.380 184.785 ;
    END
  END s_axis_rq_tdata[115]
  PIN s_axis_rq_tdata[116]
    DIRECTION INPUT ;
    USE SIGNAL ;
    PORT
      LAYER metal3 ;
      RECT 0.000 185.095 0.380 185.165 ;
    END
  END s_axis_rq_tdata[116]
  PIN s_axis_rq_tdata[117]
    DIRECTION INPUT ;
    USE SIGNAL ;
    PORT
      LAYER metal3 ;
      RECT 0.000 185.475 0.380 185.545 ;
    END
  END s_axis_rq_tdata[117]
  PIN s_axis_rq_tdata[118]
    DIRECTION INPUT ;
    USE SIGNAL ;
    PORT
      LAYER metal3 ;
      RECT 0.000 185.855 0.380 185.925 ;
    END
  END s_axis_rq_tdata[118]
  PIN s_axis_rq_tdata[119]
    DIRECTION INPUT ;
    USE SIGNAL ;
    PORT
      LAYER metal3 ;
      RECT 0.000 186.235 0.380 186.305 ;
    END
  END s_axis_rq_tdata[119]
  PIN s_axis_rq_tdata[120]
    DIRECTION INPUT ;
    USE SIGNAL ;
    PORT
      LAYER metal3 ;
      RECT 0.000 186.615 0.380 186.685 ;
    END
  END s_axis_rq_tdata[120]
  PIN s_axis_rq_tdata[121]
    DIRECTION INPUT ;
    USE SIGNAL ;
    PORT
      LAYER metal3 ;
      RECT 0.000 186.995 0.380 187.065 ;
    END
  END s_axis_rq_tdata[121]
  PIN s_axis_rq_tdata[122]
    DIRECTION INPUT ;
    USE SIGNAL ;
    PORT
      LAYER metal3 ;
      RECT 0.000 187.375 0.380 187.445 ;
    END
  END s_axis_rq_tdata[122]
  PIN s_axis_rq_tdata[123]
    DIRECTION INPUT ;
    USE SIGNAL ;
    PORT
      LAYER metal3 ;
      RECT 0.000 187.755 0.380 187.825 ;
    END
  END s_axis_rq_tdata[123]
  PIN s_axis_rq_tdata[124]
    DIRECTION INPUT ;
    USE SIGNAL ;
    PORT
      LAYER metal3 ;
      RECT 0.000 188.135 0.380 188.205 ;
    END
  END s_axis_rq_tdata[124]
  PIN s_axis_rq_tdata[125]
    DIRECTION INPUT ;
    USE SIGNAL ;
    PORT
      LAYER metal3 ;
      RECT 0.000 188.515 0.380 188.585 ;
    END
  END s_axis_rq_tdata[125]
  PIN s_axis_rq_tdata[126]
    DIRECTION INPUT ;
    USE SIGNAL ;
    PORT
      LAYER metal3 ;
      RECT 0.000 188.895 0.380 188.965 ;
    END
  END s_axis_rq_tdata[126]
  PIN s_axis_rq_tdata[127]
    DIRECTION INPUT ;
    USE SIGNAL ;
    PORT
      LAYER metal3 ;
      RECT 0.000 189.275 0.380 189.345 ;
    END
  END s_axis_rq_tdata[127]
  PIN s_axis_rq_tkeep[0]
    DIRECTION INPUT ;
    USE SIGNAL ;
    PORT
      LAYER metal3 ;
      RECT 0.000 189.655 0.380 189.725 ;
    END
  END s_axis_rq_tkeep[0]
  PIN s_axis_rq_tkeep[1]
    DIRECTION INPUT ;
    USE SIGNAL ;
    PORT
      LAYER metal3 ;
      RECT 0.000 190.035 0.380 190.105 ;
    END
  END s_axis_rq_tkeep[1]
  PIN s_axis_rq_tkeep[2]
    DIRECTION INPUT ;
    USE SIGNAL ;
    PORT
      LAYER metal3 ;
      RECT 0.000 190.415 0.380 190.485 ;
    END
  END s_axis_rq_tkeep[2]
  PIN s_axis_rq_tkeep[3]
    DIRECTION INPUT ;
    USE SIGNAL ;
    PORT
      LAYER metal3 ;
      RECT 0.000 190.795 0.380 190.865 ;
    END
  END s_axis_rq_tkeep[3]
  PIN s_axis_rq_tlast
    DIRECTION INPUT ;
    USE SIGNAL ;
    PORT
      LAYER metal3 ;
      RECT 0.000 191.175 0.380 191.245 ;
    END
  END s_axis_rq_tlast
  PIN s_axis_rq_tuser[0]
    DIRECTION INPUT ;
    USE SIGNAL ;
    PORT
      LAYER metal3 ;
      RECT 0.000 191.555 0.380 191.625 ;
    END
  END s_axis_rq_tuser[0]
  PIN s_axis_rq_tuser[1]
    DIRECTION INPUT ;
    USE SIGNAL ;
    PORT
      LAYER metal3 ;
      RECT 0.000 191.935 0.380 192.005 ;
    END
  END s_axis_rq_tuser[1]
  PIN s_axis_rq_tuser[2]
    DIRECTION INPUT ;
    USE SIGNAL ;
    PORT
      LAYER metal3 ;
      RECT 0.000 192.315 0.380 192.385 ;
    END
  END s_axis_rq_tuser[2]
  PIN s_axis_rq_tuser[3]
    DIRECTION INPUT ;
    USE SIGNAL ;
    PORT
      LAYER metal3 ;
      RECT 0.000 192.695 0.380 192.765 ;
    END
  END s_axis_rq_tuser[3]
  PIN s_axis_rq_tuser[4]
    DIRECTION INPUT ;
    USE SIGNAL ;
    PORT
      LAYER metal3 ;
      RECT 0.000 193.075 0.380 193.145 ;
    END
  END s_axis_rq_tuser[4]
  PIN s_axis_rq_tuser[5]
    DIRECTION INPUT ;
    USE SIGNAL ;
    PORT
      LAYER metal3 ;
      RECT 0.000 193.455 0.380 193.525 ;
    END
  END s_axis_rq_tuser[5]
  PIN s_axis_rq_tuser[6]
    DIRECTION INPUT ;
    USE SIGNAL ;
    PORT
      LAYER metal3 ;
      RECT 0.000 193.835 0.380 193.905 ;
    END
  END s_axis_rq_tuser[6]
  PIN s_axis_rq_tuser[7]
    DIRECTION INPUT ;
    USE SIGNAL ;
    PORT
      LAYER metal3 ;
      RECT 0.000 194.215 0.380 194.285 ;
    END
  END s_axis_rq_tuser[7]
  PIN s_axis_rq_tuser[8]
    DIRECTION INPUT ;
    USE SIGNAL ;
    PORT
      LAYER metal3 ;
      RECT 0.000 194.595 0.380 194.665 ;
    END
  END s_axis_rq_tuser[8]
  PIN s_axis_rq_tuser[9]
    DIRECTION INPUT ;
    USE SIGNAL ;
    PORT
      LAYER metal3 ;
      RECT 0.000 194.975 0.380 195.045 ;
    END
  END s_axis_rq_tuser[9]
  PIN s_axis_rq_tuser[10]
    DIRECTION INPUT ;
    USE SIGNAL ;
    PORT
      LAYER metal3 ;
      RECT 0.000 195.355 0.380 195.425 ;
    END
  END s_axis_rq_tuser[10]
  PIN s_axis_rq_tuser[11]
    DIRECTION INPUT ;
    USE SIGNAL ;
    PORT
      LAYER metal3 ;
      RECT 0.000 195.735 0.380 195.805 ;
    END
  END s_axis_rq_tuser[11]
  PIN s_axis_rq_tuser[12]
    DIRECTION INPUT ;
    USE SIGNAL ;
    PORT
      LAYER metal3 ;
      RECT 0.000 196.115 0.380 196.185 ;
    END
  END s_axis_rq_tuser[12]
  PIN s_axis_rq_tuser[13]
    DIRECTION INPUT ;
    USE SIGNAL ;
    PORT
      LAYER metal3 ;
      RECT 0.000 196.495 0.380 196.565 ;
    END
  END s_axis_rq_tuser[13]
  PIN s_axis_rq_tuser[14]
    DIRECTION INPUT ;
    USE SIGNAL ;
    PORT
      LAYER metal3 ;
      RECT 0.000 196.875 0.380 196.945 ;
    END
  END s_axis_rq_tuser[14]
  PIN s_axis_rq_tuser[15]
    DIRECTION INPUT ;
    USE SIGNAL ;
    PORT
      LAYER metal3 ;
      RECT 0.000 197.255 0.380 197.325 ;
    END
  END s_axis_rq_tuser[15]
  PIN s_axis_rq_tuser[16]
    DIRECTION INPUT ;
    USE SIGNAL ;
    PORT
      LAYER metal3 ;
      RECT 0.000 197.635 0.380 197.705 ;
    END
  END s_axis_rq_tuser[16]
  PIN s_axis_rq_tuser[17]
    DIRECTION INPUT ;
    USE SIGNAL ;
    PORT
      LAYER metal3 ;
      RECT 0.000 198.015 0.380 198.085 ;
    END
  END s_axis_rq_tuser[17]
  PIN s_axis_rq_tuser[18]
    DIRECTION INPUT ;
    USE SIGNAL ;
    PORT
      LAYER metal3 ;
      RECT 0.000 198.395 0.380 198.465 ;
    END
  END s_axis_rq_tuser[18]
  PIN s_axis_rq_tuser[19]
    DIRECTION INPUT ;
    USE SIGNAL ;
    PORT
      LAYER metal3 ;
      RECT 0.000 198.775 0.380 198.845 ;
    END
  END s_axis_rq_tuser[19]
  PIN s_axis_rq_tuser[20]
    DIRECTION INPUT ;
    USE SIGNAL ;
    PORT
      LAYER metal3 ;
      RECT 0.000 199.155 0.380 199.225 ;
    END
  END s_axis_rq_tuser[20]
  PIN s_axis_rq_tuser[21]
    DIRECTION INPUT ;
    USE SIGNAL ;
    PORT
      LAYER metal3 ;
      RECT 0.000 199.535 0.380 199.605 ;
    END
  END s_axis_rq_tuser[21]
  PIN s_axis_rq_tuser[22]
    DIRECTION INPUT ;
    USE SIGNAL ;
    PORT
      LAYER metal3 ;
      RECT 0.000 199.915 0.380 199.985 ;
    END
  END s_axis_rq_tuser[22]
  PIN s_axis_rq_tuser[23]
    DIRECTION INPUT ;
    USE SIGNAL ;
    PORT
      LAYER metal3 ;
      RECT 0.000 200.295 0.380 200.365 ;
    END
  END s_axis_rq_tuser[23]
  PIN s_axis_rq_tuser[24]
    DIRECTION INPUT ;
    USE SIGNAL ;
    PORT
      LAYER metal3 ;
      RECT 0.000 200.675 0.380 200.745 ;
    END
  END s_axis_rq_tuser[24]
  PIN s_axis_rq_tuser[25]
    DIRECTION INPUT ;
    USE SIGNAL ;
    PORT
      LAYER metal3 ;
      RECT 0.000 201.055 0.380 201.125 ;
    END
  END s_axis_rq_tuser[25]
  PIN s_axis_rq_tuser[26]
    DIRECTION INPUT ;
    USE SIGNAL ;
    PORT
      LAYER metal3 ;
      RECT 0.000 201.435 0.380 201.505 ;
    END
  END s_axis_rq_tuser[26]
  PIN s_axis_rq_tuser[27]
    DIRECTION INPUT ;
    USE SIGNAL ;
    PORT
      LAYER metal3 ;
      RECT 0.000 201.815 0.380 201.885 ;
    END
  END s_axis_rq_tuser[27]
  PIN s_axis_rq_tuser[28]
    DIRECTION INPUT ;
    USE SIGNAL ;
    PORT
      LAYER metal3 ;
      RECT 0.000 202.195 0.380 202.265 ;
    END
  END s_axis_rq_tuser[28]
  PIN s_axis_rq_tuser[29]
    DIRECTION INPUT ;
    USE SIGNAL ;
    PORT
      LAYER metal3 ;
      RECT 0.000 202.575 0.380 202.645 ;
    END
  END s_axis_rq_tuser[29]
  PIN s_axis_rq_tuser[30]
    DIRECTION INPUT ;
    USE SIGNAL ;
    PORT
      LAYER metal3 ;
      RECT 0.000 202.955 0.380 203.025 ;
    END
  END s_axis_rq_tuser[30]
  PIN s_axis_rq_tuser[31]
    DIRECTION INPUT ;
    USE SIGNAL ;
    PORT
      LAYER metal3 ;
      RECT 0.000 203.335 0.380 203.405 ;
    END
  END s_axis_rq_tuser[31]
  PIN s_axis_rq_tuser[32]
    DIRECTION INPUT ;
    USE SIGNAL ;
    PORT
      LAYER metal3 ;
      RECT 0.000 203.715 0.380 203.785 ;
    END
  END s_axis_rq_tuser[32]
  PIN s_axis_rq_tuser[33]
    DIRECTION INPUT ;
    USE SIGNAL ;
    PORT
      LAYER metal3 ;
      RECT 0.000 204.095 0.380 204.165 ;
    END
  END s_axis_rq_tuser[33]
  PIN s_axis_rq_tuser[34]
    DIRECTION INPUT ;
    USE SIGNAL ;
    PORT
      LAYER metal3 ;
      RECT 0.000 204.475 0.380 204.545 ;
    END
  END s_axis_rq_tuser[34]
  PIN s_axis_rq_tuser[35]
    DIRECTION INPUT ;
    USE SIGNAL ;
    PORT
      LAYER metal3 ;
      RECT 0.000 204.855 0.380 204.925 ;
    END
  END s_axis_rq_tuser[35]
  PIN s_axis_rq_tuser[36]
    DIRECTION INPUT ;
    USE SIGNAL ;
    PORT
      LAYER metal3 ;
      RECT 0.000 205.235 0.380 205.305 ;
    END
  END s_axis_rq_tuser[36]
  PIN s_axis_rq_tuser[37]
    DIRECTION INPUT ;
    USE SIGNAL ;
    PORT
      LAYER metal3 ;
      RECT 0.000 205.615 0.380 205.685 ;
    END
  END s_axis_rq_tuser[37]
  PIN s_axis_rq_tuser[38]
    DIRECTION INPUT ;
    USE SIGNAL ;
    PORT
      LAYER metal3 ;
      RECT 0.000 205.995 0.380 206.065 ;
    END
  END s_axis_rq_tuser[38]
  PIN s_axis_rq_tuser[39]
    DIRECTION INPUT ;
    USE SIGNAL ;
    PORT
      LAYER metal3 ;
      RECT 0.000 206.375 0.380 206.445 ;
    END
  END s_axis_rq_tuser[39]
  PIN s_axis_rq_tuser[40]
    DIRECTION INPUT ;
    USE SIGNAL ;
    PORT
      LAYER metal3 ;
      RECT 0.000 206.755 0.380 206.825 ;
    END
  END s_axis_rq_tuser[40]
  PIN s_axis_rq_tuser[41]
    DIRECTION INPUT ;
    USE SIGNAL ;
    PORT
      LAYER metal3 ;
      RECT 0.000 207.135 0.380 207.205 ;
    END
  END s_axis_rq_tuser[41]
  PIN s_axis_rq_tuser[42]
    DIRECTION INPUT ;
    USE SIGNAL ;
    PORT
      LAYER metal3 ;
      RECT 0.000 207.515 0.380 207.585 ;
    END
  END s_axis_rq_tuser[42]
  PIN s_axis_rq_tuser[43]
    DIRECTION INPUT ;
    USE SIGNAL ;
    PORT
      LAYER metal3 ;
      RECT 0.000 207.895 0.380 207.965 ;
    END
  END s_axis_rq_tuser[43]
  PIN s_axis_rq_tuser[44]
    DIRECTION INPUT ;
    USE SIGNAL ;
    PORT
      LAYER metal3 ;
      RECT 0.000 208.275 0.380 208.345 ;
    END
  END s_axis_rq_tuser[44]
  PIN s_axis_rq_tuser[45]
    DIRECTION INPUT ;
    USE SIGNAL ;
    PORT
      LAYER metal3 ;
      RECT 0.000 208.655 0.380 208.725 ;
    END
  END s_axis_rq_tuser[45]
  PIN s_axis_rq_tuser[46]
    DIRECTION INPUT ;
    USE SIGNAL ;
    PORT
      LAYER metal3 ;
      RECT 0.000 209.035 0.380 209.105 ;
    END
  END s_axis_rq_tuser[46]
  PIN s_axis_rq_tuser[47]
    DIRECTION INPUT ;
    USE SIGNAL ;
    PORT
      LAYER metal3 ;
      RECT 0.000 209.415 0.380 209.485 ;
    END
  END s_axis_rq_tuser[47]
  PIN s_axis_rq_tuser[48]
    DIRECTION INPUT ;
    USE SIGNAL ;
    PORT
      LAYER metal3 ;
      RECT 0.000 209.795 0.380 209.865 ;
    END
  END s_axis_rq_tuser[48]
  PIN s_axis_rq_tuser[49]
    DIRECTION INPUT ;
    USE SIGNAL ;
    PORT
      LAYER metal3 ;
      RECT 0.000 210.175 0.380 210.245 ;
    END
  END s_axis_rq_tuser[49]
  PIN s_axis_rq_tuser[50]
    DIRECTION INPUT ;
    USE SIGNAL ;
    PORT
      LAYER metal3 ;
      RECT 0.000 210.555 0.380 210.625 ;
    END
  END s_axis_rq_tuser[50]
  PIN s_axis_rq_tuser[51]
    DIRECTION INPUT ;
    USE SIGNAL ;
    PORT
      LAYER metal3 ;
      RECT 0.000 210.935 0.380 211.005 ;
    END
  END s_axis_rq_tuser[51]
  PIN s_axis_rq_tuser[52]
    DIRECTION INPUT ;
    USE SIGNAL ;
    PORT
      LAYER metal3 ;
      RECT 0.000 211.315 0.380 211.385 ;
    END
  END s_axis_rq_tuser[52]
  PIN s_axis_rq_tuser[53]
    DIRECTION INPUT ;
    USE SIGNAL ;
    PORT
      LAYER metal3 ;
      RECT 0.000 211.695 0.380 211.765 ;
    END
  END s_axis_rq_tuser[53]
  PIN s_axis_rq_tuser[54]
    DIRECTION INPUT ;
    USE SIGNAL ;
    PORT
      LAYER metal3 ;
      RECT 0.000 212.075 0.380 212.145 ;
    END
  END s_axis_rq_tuser[54]
  PIN s_axis_rq_tuser[55]
    DIRECTION INPUT ;
    USE SIGNAL ;
    PORT
      LAYER metal3 ;
      RECT 0.000 212.455 0.380 212.525 ;
    END
  END s_axis_rq_tuser[55]
  PIN s_axis_rq_tuser[56]
    DIRECTION INPUT ;
    USE SIGNAL ;
    PORT
      LAYER metal3 ;
      RECT 0.000 212.835 0.380 212.905 ;
    END
  END s_axis_rq_tuser[56]
  PIN s_axis_rq_tuser[57]
    DIRECTION INPUT ;
    USE SIGNAL ;
    PORT
      LAYER metal3 ;
      RECT 0.000 213.215 0.380 213.285 ;
    END
  END s_axis_rq_tuser[57]
  PIN s_axis_rq_tuser[58]
    DIRECTION INPUT ;
    USE SIGNAL ;
    PORT
      LAYER metal3 ;
      RECT 0.000 213.595 0.380 213.665 ;
    END
  END s_axis_rq_tuser[58]
  PIN s_axis_rq_tuser[59]
    DIRECTION INPUT ;
    USE SIGNAL ;
    PORT
      LAYER metal3 ;
      RECT 0.000 213.975 0.380 214.045 ;
    END
  END s_axis_rq_tuser[59]
  PIN s_axis_rq_tvalid
    DIRECTION INPUT ;
    USE SIGNAL ;
    PORT
      LAYER metal3 ;
      RECT 0.000 214.355 0.380 214.425 ;
    END
  END s_axis_rq_tvalid
  PIN sys_clk
    DIRECTION INPUT ;
    USE SIGNAL ;
    PORT
      LAYER metal3 ;
      RECT 0.000 214.735 0.380 214.805 ;
    END
  END sys_clk
  PIN sys_clk_gt
    DIRECTION INPUT ;
    USE SIGNAL ;
    PORT
      LAYER metal3 ;
      RECT 0.000 215.115 0.380 215.185 ;
    END
  END sys_clk_gt
  PIN sys_reset
    DIRECTION INPUT ;
    USE SIGNAL ;
    PORT
      LAYER metal3 ;
      RECT 0.000 215.495 0.380 215.565 ;
    END
  END sys_reset
  PIN cfg_current_speed[0]
    DIRECTION OUTPUT ;
    USE SIGNAL ;
    PORT
      LAYER metal3 ;
      RECT 0.000 215.875 0.380 215.945 ;
    END
  END cfg_current_speed[0]
  PIN cfg_current_speed[1]
    DIRECTION OUTPUT ;
    USE SIGNAL ;
    PORT
      LAYER metal3 ;
      RECT 0.000 216.255 0.380 216.325 ;
    END
  END cfg_current_speed[1]
  PIN cfg_current_speed[2]
    DIRECTION OUTPUT ;
    USE SIGNAL ;
    PORT
      LAYER metal3 ;
      RECT 0.000 216.635 0.380 216.705 ;
    END
  END cfg_current_speed[2]
  PIN cfg_dpa_substate_change[0]
    DIRECTION OUTPUT ;
    USE SIGNAL ;
    PORT
      LAYER metal3 ;
      RECT 0.000 217.015 0.380 217.085 ;
    END
  END cfg_dpa_substate_change[0]
  PIN cfg_dpa_substate_change[1]
    DIRECTION OUTPUT ;
    USE SIGNAL ;
    PORT
      LAYER metal3 ;
      RECT 0.000 217.395 0.380 217.465 ;
    END
  END cfg_dpa_substate_change[1]
  PIN cfg_dpa_substate_change[2]
    DIRECTION OUTPUT ;
    USE SIGNAL ;
    PORT
      LAYER metal3 ;
      RECT 0.000 217.775 0.380 217.845 ;
    END
  END cfg_dpa_substate_change[2]
  PIN cfg_dpa_substate_change[3]
    DIRECTION OUTPUT ;
    USE SIGNAL ;
    PORT
      LAYER metal3 ;
      RECT 0.000 218.155 0.380 218.225 ;
    END
  END cfg_dpa_substate_change[3]
  PIN cfg_err_cor_out
    DIRECTION OUTPUT ;
    USE SIGNAL ;
    PORT
      LAYER metal3 ;
      RECT 0.000 218.535 0.380 218.605 ;
    END
  END cfg_err_cor_out
  PIN cfg_err_fatal_out
    DIRECTION OUTPUT ;
    USE SIGNAL ;
    PORT
      LAYER metal3 ;
      RECT 0.000 218.915 0.380 218.985 ;
    END
  END cfg_err_fatal_out
  PIN cfg_err_nonfatal_out
    DIRECTION OUTPUT ;
    USE SIGNAL ;
    PORT
      LAYER metal3 ;
      RECT 0.000 219.295 0.380 219.365 ;
    END
  END cfg_err_nonfatal_out
  PIN cfg_fc_cpld[0]
    DIRECTION OUTPUT ;
    USE SIGNAL ;
    PORT
      LAYER metal3 ;
      RECT 0.000 219.675 0.380 219.745 ;
    END
  END cfg_fc_cpld[0]
  PIN cfg_fc_cpld[1]
    DIRECTION OUTPUT ;
    USE SIGNAL ;
    PORT
      LAYER metal3 ;
      RECT 0.000 220.055 0.380 220.125 ;
    END
  END cfg_fc_cpld[1]
  PIN cfg_fc_cpld[2]
    DIRECTION OUTPUT ;
    USE SIGNAL ;
    PORT
      LAYER metal3 ;
      RECT 0.000 220.435 0.380 220.505 ;
    END
  END cfg_fc_cpld[2]
  PIN cfg_fc_cpld[3]
    DIRECTION OUTPUT ;
    USE SIGNAL ;
    PORT
      LAYER metal3 ;
      RECT 0.000 220.815 0.380 220.885 ;
    END
  END cfg_fc_cpld[3]
  PIN cfg_fc_cpld[4]
    DIRECTION OUTPUT ;
    USE SIGNAL ;
    PORT
      LAYER metal3 ;
      RECT 0.000 221.195 0.380 221.265 ;
    END
  END cfg_fc_cpld[4]
  PIN cfg_fc_cpld[5]
    DIRECTION OUTPUT ;
    USE SIGNAL ;
    PORT
      LAYER metal3 ;
      RECT 0.000 221.575 0.380 221.645 ;
    END
  END cfg_fc_cpld[5]
  PIN cfg_fc_cpld[6]
    DIRECTION OUTPUT ;
    USE SIGNAL ;
    PORT
      LAYER metal3 ;
      RECT 0.000 221.955 0.380 222.025 ;
    END
  END cfg_fc_cpld[6]
  PIN cfg_fc_cpld[7]
    DIRECTION OUTPUT ;
    USE SIGNAL ;
    PORT
      LAYER metal3 ;
      RECT 0.000 222.335 0.380 222.405 ;
    END
  END cfg_fc_cpld[7]
  PIN cfg_fc_cpld[8]
    DIRECTION OUTPUT ;
    USE SIGNAL ;
    PORT
      LAYER metal3 ;
      RECT 0.000 222.715 0.380 222.785 ;
    END
  END cfg_fc_cpld[8]
  PIN cfg_fc_cpld[9]
    DIRECTION OUTPUT ;
    USE SIGNAL ;
    PORT
      LAYER metal3 ;
      RECT 0.000 223.095 0.380 223.165 ;
    END
  END cfg_fc_cpld[9]
  PIN cfg_fc_cpld[10]
    DIRECTION OUTPUT ;
    USE SIGNAL ;
    PORT
      LAYER metal3 ;
      RECT 0.000 223.475 0.380 223.545 ;
    END
  END cfg_fc_cpld[10]
  PIN cfg_fc_cpld[11]
    DIRECTION OUTPUT ;
    USE SIGNAL ;
    PORT
      LAYER metal3 ;
      RECT 0.000 223.855 0.380 223.925 ;
    END
  END cfg_fc_cpld[11]
  PIN cfg_fc_cplh[0]
    DIRECTION OUTPUT ;
    USE SIGNAL ;
    PORT
      LAYER metal3 ;
      RECT 0.000 224.235 0.380 224.305 ;
    END
  END cfg_fc_cplh[0]
  PIN cfg_fc_cplh[1]
    DIRECTION OUTPUT ;
    USE SIGNAL ;
    PORT
      LAYER metal3 ;
      RECT 0.000 224.615 0.380 224.685 ;
    END
  END cfg_fc_cplh[1]
  PIN cfg_fc_cplh[2]
    DIRECTION OUTPUT ;
    USE SIGNAL ;
    PORT
      LAYER metal3 ;
      RECT 0.000 224.995 0.380 225.065 ;
    END
  END cfg_fc_cplh[2]
  PIN cfg_fc_cplh[3]
    DIRECTION OUTPUT ;
    USE SIGNAL ;
    PORT
      LAYER metal3 ;
      RECT 0.000 225.375 0.380 225.445 ;
    END
  END cfg_fc_cplh[3]
  PIN cfg_fc_cplh[4]
    DIRECTION OUTPUT ;
    USE SIGNAL ;
    PORT
      LAYER metal3 ;
      RECT 0.000 225.755 0.380 225.825 ;
    END
  END cfg_fc_cplh[4]
  PIN cfg_fc_cplh[5]
    DIRECTION OUTPUT ;
    USE SIGNAL ;
    PORT
      LAYER metal3 ;
      RECT 0.000 226.135 0.380 226.205 ;
    END
  END cfg_fc_cplh[5]
  PIN cfg_fc_cplh[6]
    DIRECTION OUTPUT ;
    USE SIGNAL ;
    PORT
      LAYER metal3 ;
      RECT 0.000 226.515 0.380 226.585 ;
    END
  END cfg_fc_cplh[6]
  PIN cfg_fc_cplh[7]
    DIRECTION OUTPUT ;
    USE SIGNAL ;
    PORT
      LAYER metal3 ;
      RECT 0.000 226.895 0.380 226.965 ;
    END
  END cfg_fc_cplh[7]
  PIN cfg_fc_npd[0]
    DIRECTION OUTPUT ;
    USE SIGNAL ;
    PORT
      LAYER metal3 ;
      RECT 0.000 227.275 0.380 227.345 ;
    END
  END cfg_fc_npd[0]
  PIN cfg_fc_npd[1]
    DIRECTION OUTPUT ;
    USE SIGNAL ;
    PORT
      LAYER metal3 ;
      RECT 0.000 227.655 0.380 227.725 ;
    END
  END cfg_fc_npd[1]
  PIN cfg_fc_npd[2]
    DIRECTION OUTPUT ;
    USE SIGNAL ;
    PORT
      LAYER metal3 ;
      RECT 0.000 228.035 0.380 228.105 ;
    END
  END cfg_fc_npd[2]
  PIN cfg_fc_npd[3]
    DIRECTION OUTPUT ;
    USE SIGNAL ;
    PORT
      LAYER metal3 ;
      RECT 0.000 228.415 0.380 228.485 ;
    END
  END cfg_fc_npd[3]
  PIN cfg_fc_npd[4]
    DIRECTION OUTPUT ;
    USE SIGNAL ;
    PORT
      LAYER metal3 ;
      RECT 0.000 228.795 0.380 228.865 ;
    END
  END cfg_fc_npd[4]
  PIN cfg_fc_npd[5]
    DIRECTION OUTPUT ;
    USE SIGNAL ;
    PORT
      LAYER metal3 ;
      RECT 0.000 229.175 0.380 229.245 ;
    END
  END cfg_fc_npd[5]
  PIN cfg_fc_npd[6]
    DIRECTION OUTPUT ;
    USE SIGNAL ;
    PORT
      LAYER metal3 ;
      RECT 0.000 229.555 0.380 229.625 ;
    END
  END cfg_fc_npd[6]
  PIN cfg_fc_npd[7]
    DIRECTION OUTPUT ;
    USE SIGNAL ;
    PORT
      LAYER metal3 ;
      RECT 0.000 229.935 0.380 230.005 ;
    END
  END cfg_fc_npd[7]
  PIN cfg_fc_npd[8]
    DIRECTION OUTPUT ;
    USE SIGNAL ;
    PORT
      LAYER metal3 ;
      RECT 0.000 230.315 0.380 230.385 ;
    END
  END cfg_fc_npd[8]
  PIN cfg_fc_npd[9]
    DIRECTION OUTPUT ;
    USE SIGNAL ;
    PORT
      LAYER metal3 ;
      RECT 0.000 230.695 0.380 230.765 ;
    END
  END cfg_fc_npd[9]
  PIN cfg_fc_npd[10]
    DIRECTION OUTPUT ;
    USE SIGNAL ;
    PORT
      LAYER metal3 ;
      RECT 0.000 231.075 0.380 231.145 ;
    END
  END cfg_fc_npd[10]
  PIN cfg_fc_npd[11]
    DIRECTION OUTPUT ;
    USE SIGNAL ;
    PORT
      LAYER metal3 ;
      RECT 0.000 231.455 0.380 231.525 ;
    END
  END cfg_fc_npd[11]
  PIN cfg_fc_nph[0]
    DIRECTION OUTPUT ;
    USE SIGNAL ;
    PORT
      LAYER metal3 ;
      RECT 0.000 231.835 0.380 231.905 ;
    END
  END cfg_fc_nph[0]
  PIN cfg_fc_nph[1]
    DIRECTION OUTPUT ;
    USE SIGNAL ;
    PORT
      LAYER metal3 ;
      RECT 0.000 232.215 0.380 232.285 ;
    END
  END cfg_fc_nph[1]
  PIN cfg_fc_nph[2]
    DIRECTION OUTPUT ;
    USE SIGNAL ;
    PORT
      LAYER metal3 ;
      RECT 0.000 232.595 0.380 232.665 ;
    END
  END cfg_fc_nph[2]
  PIN cfg_fc_nph[3]
    DIRECTION OUTPUT ;
    USE SIGNAL ;
    PORT
      LAYER metal3 ;
      RECT 0.000 232.975 0.380 233.045 ;
    END
  END cfg_fc_nph[3]
  PIN cfg_fc_nph[4]
    DIRECTION OUTPUT ;
    USE SIGNAL ;
    PORT
      LAYER metal3 ;
      RECT 0.000 233.355 0.380 233.425 ;
    END
  END cfg_fc_nph[4]
  PIN cfg_fc_nph[5]
    DIRECTION OUTPUT ;
    USE SIGNAL ;
    PORT
      LAYER metal3 ;
      RECT 0.000 233.735 0.380 233.805 ;
    END
  END cfg_fc_nph[5]
  PIN cfg_fc_nph[6]
    DIRECTION OUTPUT ;
    USE SIGNAL ;
    PORT
      LAYER metal3 ;
      RECT 0.000 234.115 0.380 234.185 ;
    END
  END cfg_fc_nph[6]
  PIN cfg_fc_nph[7]
    DIRECTION OUTPUT ;
    USE SIGNAL ;
    PORT
      LAYER metal3 ;
      RECT 0.000 234.495 0.380 234.565 ;
    END
  END cfg_fc_nph[7]
  PIN cfg_fc_pd[0]
    DIRECTION OUTPUT ;
    USE SIGNAL ;
    PORT
      LAYER metal3 ;
      RECT 0.000 234.875 0.380 234.945 ;
    END
  END cfg_fc_pd[0]
  PIN cfg_fc_pd[1]
    DIRECTION OUTPUT ;
    USE SIGNAL ;
    PORT
      LAYER metal3 ;
      RECT 0.000 235.255 0.380 235.325 ;
    END
  END cfg_fc_pd[1]
  PIN cfg_fc_pd[2]
    DIRECTION OUTPUT ;
    USE SIGNAL ;
    PORT
      LAYER metal3 ;
      RECT 0.000 235.635 0.380 235.705 ;
    END
  END cfg_fc_pd[2]
  PIN cfg_fc_pd[3]
    DIRECTION OUTPUT ;
    USE SIGNAL ;
    PORT
      LAYER metal3 ;
      RECT 0.000 236.015 0.380 236.085 ;
    END
  END cfg_fc_pd[3]
  PIN cfg_fc_pd[4]
    DIRECTION OUTPUT ;
    USE SIGNAL ;
    PORT
      LAYER metal3 ;
      RECT 0.000 236.395 0.380 236.465 ;
    END
  END cfg_fc_pd[4]
  PIN cfg_fc_pd[5]
    DIRECTION OUTPUT ;
    USE SIGNAL ;
    PORT
      LAYER metal3 ;
      RECT 0.000 236.775 0.380 236.845 ;
    END
  END cfg_fc_pd[5]
  PIN cfg_fc_pd[6]
    DIRECTION OUTPUT ;
    USE SIGNAL ;
    PORT
      LAYER metal3 ;
      RECT 0.000 237.155 0.380 237.225 ;
    END
  END cfg_fc_pd[6]
  PIN cfg_fc_pd[7]
    DIRECTION OUTPUT ;
    USE SIGNAL ;
    PORT
      LAYER metal3 ;
      RECT 0.000 237.535 0.380 237.605 ;
    END
  END cfg_fc_pd[7]
  PIN cfg_fc_pd[8]
    DIRECTION OUTPUT ;
    USE SIGNAL ;
    PORT
      LAYER metal3 ;
      RECT 0.000 237.915 0.380 237.985 ;
    END
  END cfg_fc_pd[8]
  PIN cfg_fc_pd[9]
    DIRECTION OUTPUT ;
    USE SIGNAL ;
    PORT
      LAYER metal3 ;
      RECT 0.000 238.295 0.380 238.365 ;
    END
  END cfg_fc_pd[9]
  PIN cfg_fc_pd[10]
    DIRECTION OUTPUT ;
    USE SIGNAL ;
    PORT
      LAYER metal3 ;
      RECT 0.000 238.675 0.380 238.745 ;
    END
  END cfg_fc_pd[10]
  PIN cfg_fc_pd[11]
    DIRECTION OUTPUT ;
    USE SIGNAL ;
    PORT
      LAYER metal3 ;
      RECT 0.000 239.055 0.380 239.125 ;
    END
  END cfg_fc_pd[11]
  PIN cfg_fc_ph[0]
    DIRECTION OUTPUT ;
    USE SIGNAL ;
    PORT
      LAYER metal3 ;
      RECT 0.000 239.435 0.380 239.505 ;
    END
  END cfg_fc_ph[0]
  PIN cfg_fc_ph[1]
    DIRECTION OUTPUT ;
    USE SIGNAL ;
    PORT
      LAYER metal3 ;
      RECT 0.000 239.815 0.380 239.885 ;
    END
  END cfg_fc_ph[1]
  PIN cfg_fc_ph[2]
    DIRECTION OUTPUT ;
    USE SIGNAL ;
    PORT
      LAYER metal3 ;
      RECT 0.000 240.195 0.380 240.265 ;
    END
  END cfg_fc_ph[2]
  PIN cfg_fc_ph[3]
    DIRECTION OUTPUT ;
    USE SIGNAL ;
    PORT
      LAYER metal3 ;
      RECT 0.000 240.575 0.380 240.645 ;
    END
  END cfg_fc_ph[3]
  PIN cfg_fc_ph[4]
    DIRECTION OUTPUT ;
    USE SIGNAL ;
    PORT
      LAYER metal3 ;
      RECT 0.000 240.955 0.380 241.025 ;
    END
  END cfg_fc_ph[4]
  PIN cfg_fc_ph[5]
    DIRECTION OUTPUT ;
    USE SIGNAL ;
    PORT
      LAYER metal3 ;
      RECT 0.000 241.335 0.380 241.405 ;
    END
  END cfg_fc_ph[5]
  PIN cfg_fc_ph[6]
    DIRECTION OUTPUT ;
    USE SIGNAL ;
    PORT
      LAYER metal3 ;
      RECT 0.000 241.715 0.380 241.785 ;
    END
  END cfg_fc_ph[6]
  PIN cfg_fc_ph[7]
    DIRECTION OUTPUT ;
    USE SIGNAL ;
    PORT
      LAYER metal3 ;
      RECT 0.000 242.095 0.380 242.165 ;
    END
  END cfg_fc_ph[7]
  PIN cfg_flr_in_process[0]
    DIRECTION OUTPUT ;
    USE SIGNAL ;
    PORT
      LAYER metal3 ;
      RECT 0.000 242.475 0.380 242.545 ;
    END
  END cfg_flr_in_process[0]
  PIN cfg_flr_in_process[1]
    DIRECTION OUTPUT ;
    USE SIGNAL ;
    PORT
      LAYER metal3 ;
      RECT 0.000 242.855 0.380 242.925 ;
    END
  END cfg_flr_in_process[1]
  PIN cfg_flr_in_process[2]
    DIRECTION OUTPUT ;
    USE SIGNAL ;
    PORT
      LAYER metal3 ;
      RECT 0.000 243.235 0.380 243.305 ;
    END
  END cfg_flr_in_process[2]
  PIN cfg_flr_in_process[3]
    DIRECTION OUTPUT ;
    USE SIGNAL ;
    PORT
      LAYER metal3 ;
      RECT 0.000 243.615 0.380 243.685 ;
    END
  END cfg_flr_in_process[3]
  PIN cfg_function_power_state[0]
    DIRECTION OUTPUT ;
    USE SIGNAL ;
    PORT
      LAYER metal3 ;
      RECT 0.000 243.995 0.380 244.065 ;
    END
  END cfg_function_power_state[0]
  PIN cfg_function_power_state[1]
    DIRECTION OUTPUT ;
    USE SIGNAL ;
    PORT
      LAYER metal3 ;
      RECT 0.000 244.375 0.380 244.445 ;
    END
  END cfg_function_power_state[1]
  PIN cfg_function_power_state[2]
    DIRECTION OUTPUT ;
    USE SIGNAL ;
    PORT
      LAYER metal3 ;
      RECT 0.000 244.755 0.380 244.825 ;
    END
  END cfg_function_power_state[2]
  PIN cfg_function_power_state[3]
    DIRECTION OUTPUT ;
    USE SIGNAL ;
    PORT
      LAYER metal3 ;
      RECT 0.000 245.135 0.380 245.205 ;
    END
  END cfg_function_power_state[3]
  PIN cfg_function_power_state[4]
    DIRECTION OUTPUT ;
    USE SIGNAL ;
    PORT
      LAYER metal3 ;
      RECT 0.000 245.515 0.380 245.585 ;
    END
  END cfg_function_power_state[4]
  PIN cfg_function_power_state[5]
    DIRECTION OUTPUT ;
    USE SIGNAL ;
    PORT
      LAYER metal3 ;
      RECT 0.000 245.895 0.380 245.965 ;
    END
  END cfg_function_power_state[5]
  PIN cfg_function_power_state[6]
    DIRECTION OUTPUT ;
    USE SIGNAL ;
    PORT
      LAYER metal3 ;
      RECT 0.000 246.275 0.380 246.345 ;
    END
  END cfg_function_power_state[6]
  PIN cfg_function_power_state[7]
    DIRECTION OUTPUT ;
    USE SIGNAL ;
    PORT
      LAYER metal3 ;
      RECT 0.000 246.655 0.380 246.725 ;
    END
  END cfg_function_power_state[7]
  PIN cfg_function_power_state[8]
    DIRECTION OUTPUT ;
    USE SIGNAL ;
    PORT
      LAYER metal3 ;
      RECT 0.000 247.035 0.380 247.105 ;
    END
  END cfg_function_power_state[8]
  PIN cfg_function_power_state[9]
    DIRECTION OUTPUT ;
    USE SIGNAL ;
    PORT
      LAYER metal3 ;
      RECT 0.000 247.415 0.380 247.485 ;
    END
  END cfg_function_power_state[9]
  PIN cfg_function_power_state[10]
    DIRECTION OUTPUT ;
    USE SIGNAL ;
    PORT
      LAYER metal3 ;
      RECT 0.000 247.795 0.380 247.865 ;
    END
  END cfg_function_power_state[10]
  PIN cfg_function_power_state[11]
    DIRECTION OUTPUT ;
    USE SIGNAL ;
    PORT
      LAYER metal3 ;
      RECT 0.000 248.175 0.380 248.245 ;
    END
  END cfg_function_power_state[11]
  PIN cfg_function_status[0]
    DIRECTION OUTPUT ;
    USE SIGNAL ;
    PORT
      LAYER metal3 ;
      RECT 279.620 0.795 280.000 0.865 ;
    END
  END cfg_function_status[0]
  PIN cfg_function_status[1]
    DIRECTION OUTPUT ;
    USE SIGNAL ;
    PORT
      LAYER metal3 ;
      RECT 279.620 1.175 280.000 1.245 ;
    END
  END cfg_function_status[1]
  PIN cfg_function_status[2]
    DIRECTION OUTPUT ;
    USE SIGNAL ;
    PORT
      LAYER metal3 ;
      RECT 279.620 1.555 280.000 1.625 ;
    END
  END cfg_function_status[2]
  PIN cfg_function_status[3]
    DIRECTION OUTPUT ;
    USE SIGNAL ;
    PORT
      LAYER metal3 ;
      RECT 279.620 1.935 280.000 2.005 ;
    END
  END cfg_function_status[3]
  PIN cfg_function_status[4]
    DIRECTION OUTPUT ;
    USE SIGNAL ;
    PORT
      LAYER metal3 ;
      RECT 279.620 2.315 280.000 2.385 ;
    END
  END cfg_function_status[4]
  PIN cfg_function_status[5]
    DIRECTION OUTPUT ;
    USE SIGNAL ;
    PORT
      LAYER metal3 ;
      RECT 279.620 2.695 280.000 2.765 ;
    END
  END cfg_function_status[5]
  PIN cfg_function_status[6]
    DIRECTION OUTPUT ;
    USE SIGNAL ;
    PORT
      LAYER metal3 ;
      RECT 279.620 3.075 280.000 3.145 ;
    END
  END cfg_function_status[6]
  PIN cfg_function_status[7]
    DIRECTION OUTPUT ;
    USE SIGNAL ;
    PORT
      LAYER metal3 ;
      RECT 279.620 3.455 280.000 3.525 ;
    END
  END cfg_function_status[7]
  PIN cfg_function_status[8]
    DIRECTION OUTPUT ;
    USE SIGNAL ;
    PORT
      LAYER metal3 ;
      RECT 279.620 3.835 280.000 3.905 ;
    END
  END cfg_function_status[8]
  PIN cfg_function_status[9]
    DIRECTION OUTPUT ;
    USE SIGNAL ;
    PORT
      LAYER metal3 ;
      RECT 279.620 4.215 280.000 4.285 ;
    END
  END cfg_function_status[9]
  PIN cfg_function_status[10]
    DIRECTION OUTPUT ;
    USE SIGNAL ;
    PORT
      LAYER metal3 ;
      RECT 279.620 4.595 280.000 4.665 ;
    END
  END cfg_function_status[10]
  PIN cfg_function_status[11]
    DIRECTION OUTPUT ;
    USE SIGNAL ;
    PORT
      LAYER metal3 ;
      RECT 279.620 4.975 280.000 5.045 ;
    END
  END cfg_function_status[11]
  PIN cfg_function_status[12]
    DIRECTION OUTPUT ;
    USE SIGNAL ;
    PORT
      LAYER metal3 ;
      RECT 279.620 5.355 280.000 5.425 ;
    END
  END cfg_function_status[12]
  PIN cfg_function_status[13]
    DIRECTION OUTPUT ;
    USE SIGNAL ;
    PORT
      LAYER metal3 ;
      RECT 279.620 5.735 280.000 5.805 ;
    END
  END cfg_function_status[13]
  PIN cfg_function_status[14]
    DIRECTION OUTPUT ;
    USE SIGNAL ;
    PORT
      LAYER metal3 ;
      RECT 279.620 6.115 280.000 6.185 ;
    END
  END cfg_function_status[14]
  PIN cfg_function_status[15]
    DIRECTION OUTPUT ;
    USE SIGNAL ;
    PORT
      LAYER metal3 ;
      RECT 279.620 6.495 280.000 6.565 ;
    END
  END cfg_function_status[15]
  PIN cfg_hot_reset_out
    DIRECTION OUTPUT ;
    USE SIGNAL ;
    PORT
      LAYER metal3 ;
      RECT 279.620 6.875 280.000 6.945 ;
    END
  END cfg_hot_reset_out
  PIN cfg_interrupt_msi_data[0]
    DIRECTION OUTPUT ;
    USE SIGNAL ;
    PORT
      LAYER metal3 ;
      RECT 279.620 7.255 280.000 7.325 ;
    END
  END cfg_interrupt_msi_data[0]
  PIN cfg_interrupt_msi_data[1]
    DIRECTION OUTPUT ;
    USE SIGNAL ;
    PORT
      LAYER metal3 ;
      RECT 279.620 7.635 280.000 7.705 ;
    END
  END cfg_interrupt_msi_data[1]
  PIN cfg_interrupt_msi_data[2]
    DIRECTION OUTPUT ;
    USE SIGNAL ;
    PORT
      LAYER metal3 ;
      RECT 279.620 8.015 280.000 8.085 ;
    END
  END cfg_interrupt_msi_data[2]
  PIN cfg_interrupt_msi_data[3]
    DIRECTION OUTPUT ;
    USE SIGNAL ;
    PORT
      LAYER metal3 ;
      RECT 279.620 8.395 280.000 8.465 ;
    END
  END cfg_interrupt_msi_data[3]
  PIN cfg_interrupt_msi_data[4]
    DIRECTION OUTPUT ;
    USE SIGNAL ;
    PORT
      LAYER metal3 ;
      RECT 279.620 8.775 280.000 8.845 ;
    END
  END cfg_interrupt_msi_data[4]
  PIN cfg_interrupt_msi_data[5]
    DIRECTION OUTPUT ;
    USE SIGNAL ;
    PORT
      LAYER metal3 ;
      RECT 279.620 9.155 280.000 9.225 ;
    END
  END cfg_interrupt_msi_data[5]
  PIN cfg_interrupt_msi_data[6]
    DIRECTION OUTPUT ;
    USE SIGNAL ;
    PORT
      LAYER metal3 ;
      RECT 279.620 9.535 280.000 9.605 ;
    END
  END cfg_interrupt_msi_data[6]
  PIN cfg_interrupt_msi_data[7]
    DIRECTION OUTPUT ;
    USE SIGNAL ;
    PORT
      LAYER metal3 ;
      RECT 279.620 9.915 280.000 9.985 ;
    END
  END cfg_interrupt_msi_data[7]
  PIN cfg_interrupt_msi_data[8]
    DIRECTION OUTPUT ;
    USE SIGNAL ;
    PORT
      LAYER metal3 ;
      RECT 279.620 10.295 280.000 10.365 ;
    END
  END cfg_interrupt_msi_data[8]
  PIN cfg_interrupt_msi_data[9]
    DIRECTION OUTPUT ;
    USE SIGNAL ;
    PORT
      LAYER metal3 ;
      RECT 279.620 10.675 280.000 10.745 ;
    END
  END cfg_interrupt_msi_data[9]
  PIN cfg_interrupt_msi_data[10]
    DIRECTION OUTPUT ;
    USE SIGNAL ;
    PORT
      LAYER metal3 ;
      RECT 279.620 11.055 280.000 11.125 ;
    END
  END cfg_interrupt_msi_data[10]
  PIN cfg_interrupt_msi_data[11]
    DIRECTION OUTPUT ;
    USE SIGNAL ;
    PORT
      LAYER metal3 ;
      RECT 279.620 11.435 280.000 11.505 ;
    END
  END cfg_interrupt_msi_data[11]
  PIN cfg_interrupt_msi_data[12]
    DIRECTION OUTPUT ;
    USE SIGNAL ;
    PORT
      LAYER metal3 ;
      RECT 279.620 11.815 280.000 11.885 ;
    END
  END cfg_interrupt_msi_data[12]
  PIN cfg_interrupt_msi_data[13]
    DIRECTION OUTPUT ;
    USE SIGNAL ;
    PORT
      LAYER metal3 ;
      RECT 279.620 12.195 280.000 12.265 ;
    END
  END cfg_interrupt_msi_data[13]
  PIN cfg_interrupt_msi_data[14]
    DIRECTION OUTPUT ;
    USE SIGNAL ;
    PORT
      LAYER metal3 ;
      RECT 279.620 12.575 280.000 12.645 ;
    END
  END cfg_interrupt_msi_data[14]
  PIN cfg_interrupt_msi_data[15]
    DIRECTION OUTPUT ;
    USE SIGNAL ;
    PORT
      LAYER metal3 ;
      RECT 279.620 12.955 280.000 13.025 ;
    END
  END cfg_interrupt_msi_data[15]
  PIN cfg_interrupt_msi_data[16]
    DIRECTION OUTPUT ;
    USE SIGNAL ;
    PORT
      LAYER metal3 ;
      RECT 279.620 13.335 280.000 13.405 ;
    END
  END cfg_interrupt_msi_data[16]
  PIN cfg_interrupt_msi_data[17]
    DIRECTION OUTPUT ;
    USE SIGNAL ;
    PORT
      LAYER metal3 ;
      RECT 279.620 13.715 280.000 13.785 ;
    END
  END cfg_interrupt_msi_data[17]
  PIN cfg_interrupt_msi_data[18]
    DIRECTION OUTPUT ;
    USE SIGNAL ;
    PORT
      LAYER metal3 ;
      RECT 279.620 14.095 280.000 14.165 ;
    END
  END cfg_interrupt_msi_data[18]
  PIN cfg_interrupt_msi_data[19]
    DIRECTION OUTPUT ;
    USE SIGNAL ;
    PORT
      LAYER metal3 ;
      RECT 279.620 14.475 280.000 14.545 ;
    END
  END cfg_interrupt_msi_data[19]
  PIN cfg_interrupt_msi_data[20]
    DIRECTION OUTPUT ;
    USE SIGNAL ;
    PORT
      LAYER metal3 ;
      RECT 279.620 14.855 280.000 14.925 ;
    END
  END cfg_interrupt_msi_data[20]
  PIN cfg_interrupt_msi_data[21]
    DIRECTION OUTPUT ;
    USE SIGNAL ;
    PORT
      LAYER metal3 ;
      RECT 279.620 15.235 280.000 15.305 ;
    END
  END cfg_interrupt_msi_data[21]
  PIN cfg_interrupt_msi_data[22]
    DIRECTION OUTPUT ;
    USE SIGNAL ;
    PORT
      LAYER metal3 ;
      RECT 279.620 15.615 280.000 15.685 ;
    END
  END cfg_interrupt_msi_data[22]
  PIN cfg_interrupt_msi_data[23]
    DIRECTION OUTPUT ;
    USE SIGNAL ;
    PORT
      LAYER metal3 ;
      RECT 279.620 15.995 280.000 16.065 ;
    END
  END cfg_interrupt_msi_data[23]
  PIN cfg_interrupt_msi_data[24]
    DIRECTION OUTPUT ;
    USE SIGNAL ;
    PORT
      LAYER metal3 ;
      RECT 279.620 16.375 280.000 16.445 ;
    END
  END cfg_interrupt_msi_data[24]
  PIN cfg_interrupt_msi_data[25]
    DIRECTION OUTPUT ;
    USE SIGNAL ;
    PORT
      LAYER metal3 ;
      RECT 279.620 16.755 280.000 16.825 ;
    END
  END cfg_interrupt_msi_data[25]
  PIN cfg_interrupt_msi_data[26]
    DIRECTION OUTPUT ;
    USE SIGNAL ;
    PORT
      LAYER metal3 ;
      RECT 279.620 17.135 280.000 17.205 ;
    END
  END cfg_interrupt_msi_data[26]
  PIN cfg_interrupt_msi_data[27]
    DIRECTION OUTPUT ;
    USE SIGNAL ;
    PORT
      LAYER metal3 ;
      RECT 279.620 17.515 280.000 17.585 ;
    END
  END cfg_interrupt_msi_data[27]
  PIN cfg_interrupt_msi_data[28]
    DIRECTION OUTPUT ;
    USE SIGNAL ;
    PORT
      LAYER metal3 ;
      RECT 279.620 17.895 280.000 17.965 ;
    END
  END cfg_interrupt_msi_data[28]
  PIN cfg_interrupt_msi_data[29]
    DIRECTION OUTPUT ;
    USE SIGNAL ;
    PORT
      LAYER metal3 ;
      RECT 279.620 18.275 280.000 18.345 ;
    END
  END cfg_interrupt_msi_data[29]
  PIN cfg_interrupt_msi_data[30]
    DIRECTION OUTPUT ;
    USE SIGNAL ;
    PORT
      LAYER metal3 ;
      RECT 279.620 18.655 280.000 18.725 ;
    END
  END cfg_interrupt_msi_data[30]
  PIN cfg_interrupt_msi_data[31]
    DIRECTION OUTPUT ;
    USE SIGNAL ;
    PORT
      LAYER metal3 ;
      RECT 279.620 19.035 280.000 19.105 ;
    END
  END cfg_interrupt_msi_data[31]
  PIN cfg_interrupt_msi_enable[0]
    DIRECTION OUTPUT ;
    USE SIGNAL ;
    PORT
      LAYER metal3 ;
      RECT 279.620 19.415 280.000 19.485 ;
    END
  END cfg_interrupt_msi_enable[0]
  PIN cfg_interrupt_msi_enable[1]
    DIRECTION OUTPUT ;
    USE SIGNAL ;
    PORT
      LAYER metal3 ;
      RECT 279.620 19.795 280.000 19.865 ;
    END
  END cfg_interrupt_msi_enable[1]
  PIN cfg_interrupt_msi_enable[2]
    DIRECTION OUTPUT ;
    USE SIGNAL ;
    PORT
      LAYER metal3 ;
      RECT 279.620 20.175 280.000 20.245 ;
    END
  END cfg_interrupt_msi_enable[2]
  PIN cfg_interrupt_msi_enable[3]
    DIRECTION OUTPUT ;
    USE SIGNAL ;
    PORT
      LAYER metal3 ;
      RECT 279.620 20.555 280.000 20.625 ;
    END
  END cfg_interrupt_msi_enable[3]
  PIN cfg_interrupt_msi_fail
    DIRECTION OUTPUT ;
    USE SIGNAL ;
    PORT
      LAYER metal3 ;
      RECT 279.620 20.935 280.000 21.005 ;
    END
  END cfg_interrupt_msi_fail
  PIN cfg_interrupt_msi_mask_update
    DIRECTION OUTPUT ;
    USE SIGNAL ;
    PORT
      LAYER metal3 ;
      RECT 279.620 21.315 280.000 21.385 ;
    END
  END cfg_interrupt_msi_mask_update
  PIN cfg_interrupt_msi_mmenable[0]
    DIRECTION OUTPUT ;
    USE SIGNAL ;
    PORT
      LAYER metal3 ;
      RECT 279.620 21.695 280.000 21.765 ;
    END
  END cfg_interrupt_msi_mmenable[0]
  PIN cfg_interrupt_msi_mmenable[1]
    DIRECTION OUTPUT ;
    USE SIGNAL ;
    PORT
      LAYER metal3 ;
      RECT 279.620 22.075 280.000 22.145 ;
    END
  END cfg_interrupt_msi_mmenable[1]
  PIN cfg_interrupt_msi_mmenable[2]
    DIRECTION OUTPUT ;
    USE SIGNAL ;
    PORT
      LAYER metal3 ;
      RECT 279.620 22.455 280.000 22.525 ;
    END
  END cfg_interrupt_msi_mmenable[2]
  PIN cfg_interrupt_msi_mmenable[3]
    DIRECTION OUTPUT ;
    USE SIGNAL ;
    PORT
      LAYER metal3 ;
      RECT 279.620 22.835 280.000 22.905 ;
    END
  END cfg_interrupt_msi_mmenable[3]
  PIN cfg_interrupt_msi_mmenable[4]
    DIRECTION OUTPUT ;
    USE SIGNAL ;
    PORT
      LAYER metal3 ;
      RECT 279.620 23.215 280.000 23.285 ;
    END
  END cfg_interrupt_msi_mmenable[4]
  PIN cfg_interrupt_msi_mmenable[5]
    DIRECTION OUTPUT ;
    USE SIGNAL ;
    PORT
      LAYER metal3 ;
      RECT 279.620 23.595 280.000 23.665 ;
    END
  END cfg_interrupt_msi_mmenable[5]
  PIN cfg_interrupt_msi_mmenable[6]
    DIRECTION OUTPUT ;
    USE SIGNAL ;
    PORT
      LAYER metal3 ;
      RECT 279.620 23.975 280.000 24.045 ;
    END
  END cfg_interrupt_msi_mmenable[6]
  PIN cfg_interrupt_msi_mmenable[7]
    DIRECTION OUTPUT ;
    USE SIGNAL ;
    PORT
      LAYER metal3 ;
      RECT 279.620 24.355 280.000 24.425 ;
    END
  END cfg_interrupt_msi_mmenable[7]
  PIN cfg_interrupt_msi_mmenable[8]
    DIRECTION OUTPUT ;
    USE SIGNAL ;
    PORT
      LAYER metal3 ;
      RECT 279.620 24.735 280.000 24.805 ;
    END
  END cfg_interrupt_msi_mmenable[8]
  PIN cfg_interrupt_msi_mmenable[9]
    DIRECTION OUTPUT ;
    USE SIGNAL ;
    PORT
      LAYER metal3 ;
      RECT 279.620 25.115 280.000 25.185 ;
    END
  END cfg_interrupt_msi_mmenable[9]
  PIN cfg_interrupt_msi_mmenable[10]
    DIRECTION OUTPUT ;
    USE SIGNAL ;
    PORT
      LAYER metal3 ;
      RECT 279.620 25.495 280.000 25.565 ;
    END
  END cfg_interrupt_msi_mmenable[10]
  PIN cfg_interrupt_msi_mmenable[11]
    DIRECTION OUTPUT ;
    USE SIGNAL ;
    PORT
      LAYER metal3 ;
      RECT 279.620 25.875 280.000 25.945 ;
    END
  END cfg_interrupt_msi_mmenable[11]
  PIN cfg_interrupt_msi_sent
    DIRECTION OUTPUT ;
    USE SIGNAL ;
    PORT
      LAYER metal3 ;
      RECT 279.620 26.255 280.000 26.325 ;
    END
  END cfg_interrupt_msi_sent
  PIN cfg_interrupt_sent
    DIRECTION OUTPUT ;
    USE SIGNAL ;
    PORT
      LAYER metal3 ;
      RECT 279.620 26.635 280.000 26.705 ;
    END
  END cfg_interrupt_sent
  PIN cfg_link_power_state[0]
    DIRECTION OUTPUT ;
    USE SIGNAL ;
    PORT
      LAYER metal3 ;
      RECT 279.620 27.015 280.000 27.085 ;
    END
  END cfg_link_power_state[0]
  PIN cfg_link_power_state[1]
    DIRECTION OUTPUT ;
    USE SIGNAL ;
    PORT
      LAYER metal3 ;
      RECT 279.620 27.395 280.000 27.465 ;
    END
  END cfg_link_power_state[1]
  PIN cfg_local_error
    DIRECTION OUTPUT ;
    USE SIGNAL ;
    PORT
      LAYER metal3 ;
      RECT 279.620 27.775 280.000 27.845 ;
    END
  END cfg_local_error
  PIN cfg_ltr_enable
    DIRECTION OUTPUT ;
    USE SIGNAL ;
    PORT
      LAYER metal3 ;
      RECT 279.620 28.155 280.000 28.225 ;
    END
  END cfg_ltr_enable
  PIN cfg_ltssm_state[0]
    DIRECTION OUTPUT ;
    USE SIGNAL ;
    PORT
      LAYER metal3 ;
      RECT 279.620 28.535 280.000 28.605 ;
    END
  END cfg_ltssm_state[0]
  PIN cfg_ltssm_state[1]
    DIRECTION OUTPUT ;
    USE SIGNAL ;
    PORT
      LAYER metal3 ;
      RECT 279.620 28.915 280.000 28.985 ;
    END
  END cfg_ltssm_state[1]
  PIN cfg_ltssm_state[2]
    DIRECTION OUTPUT ;
    USE SIGNAL ;
    PORT
      LAYER metal3 ;
      RECT 279.620 29.295 280.000 29.365 ;
    END
  END cfg_ltssm_state[2]
  PIN cfg_ltssm_state[3]
    DIRECTION OUTPUT ;
    USE SIGNAL ;
    PORT
      LAYER metal3 ;
      RECT 279.620 29.675 280.000 29.745 ;
    END
  END cfg_ltssm_state[3]
  PIN cfg_ltssm_state[4]
    DIRECTION OUTPUT ;
    USE SIGNAL ;
    PORT
      LAYER metal3 ;
      RECT 279.620 30.055 280.000 30.125 ;
    END
  END cfg_ltssm_state[4]
  PIN cfg_ltssm_state[5]
    DIRECTION OUTPUT ;
    USE SIGNAL ;
    PORT
      LAYER metal3 ;
      RECT 279.620 30.435 280.000 30.505 ;
    END
  END cfg_ltssm_state[5]
  PIN cfg_max_payload[0]
    DIRECTION OUTPUT ;
    USE SIGNAL ;
    PORT
      LAYER metal3 ;
      RECT 279.620 30.815 280.000 30.885 ;
    END
  END cfg_max_payload[0]
  PIN cfg_max_payload[1]
    DIRECTION OUTPUT ;
    USE SIGNAL ;
    PORT
      LAYER metal3 ;
      RECT 279.620 31.195 280.000 31.265 ;
    END
  END cfg_max_payload[1]
  PIN cfg_max_payload[2]
    DIRECTION OUTPUT ;
    USE SIGNAL ;
    PORT
      LAYER metal3 ;
      RECT 279.620 31.575 280.000 31.645 ;
    END
  END cfg_max_payload[2]
  PIN cfg_max_read_req[0]
    DIRECTION OUTPUT ;
    USE SIGNAL ;
    PORT
      LAYER metal3 ;
      RECT 279.620 31.955 280.000 32.025 ;
    END
  END cfg_max_read_req[0]
  PIN cfg_max_read_req[1]
    DIRECTION OUTPUT ;
    USE SIGNAL ;
    PORT
      LAYER metal3 ;
      RECT 279.620 32.335 280.000 32.405 ;
    END
  END cfg_max_read_req[1]
  PIN cfg_max_read_req[2]
    DIRECTION OUTPUT ;
    USE SIGNAL ;
    PORT
      LAYER metal3 ;
      RECT 279.620 32.715 280.000 32.785 ;
    END
  END cfg_max_read_req[2]
  PIN cfg_mgmt_read_data[0]
    DIRECTION OUTPUT ;
    USE SIGNAL ;
    PORT
      LAYER metal3 ;
      RECT 279.620 33.095 280.000 33.165 ;
    END
  END cfg_mgmt_read_data[0]
  PIN cfg_mgmt_read_data[1]
    DIRECTION OUTPUT ;
    USE SIGNAL ;
    PORT
      LAYER metal3 ;
      RECT 279.620 33.475 280.000 33.545 ;
    END
  END cfg_mgmt_read_data[1]
  PIN cfg_mgmt_read_data[2]
    DIRECTION OUTPUT ;
    USE SIGNAL ;
    PORT
      LAYER metal3 ;
      RECT 279.620 33.855 280.000 33.925 ;
    END
  END cfg_mgmt_read_data[2]
  PIN cfg_mgmt_read_data[3]
    DIRECTION OUTPUT ;
    USE SIGNAL ;
    PORT
      LAYER metal3 ;
      RECT 279.620 34.235 280.000 34.305 ;
    END
  END cfg_mgmt_read_data[3]
  PIN cfg_mgmt_read_data[4]
    DIRECTION OUTPUT ;
    USE SIGNAL ;
    PORT
      LAYER metal3 ;
      RECT 279.620 34.615 280.000 34.685 ;
    END
  END cfg_mgmt_read_data[4]
  PIN cfg_mgmt_read_data[5]
    DIRECTION OUTPUT ;
    USE SIGNAL ;
    PORT
      LAYER metal3 ;
      RECT 279.620 34.995 280.000 35.065 ;
    END
  END cfg_mgmt_read_data[5]
  PIN cfg_mgmt_read_data[6]
    DIRECTION OUTPUT ;
    USE SIGNAL ;
    PORT
      LAYER metal3 ;
      RECT 279.620 35.375 280.000 35.445 ;
    END
  END cfg_mgmt_read_data[6]
  PIN cfg_mgmt_read_data[7]
    DIRECTION OUTPUT ;
    USE SIGNAL ;
    PORT
      LAYER metal3 ;
      RECT 279.620 35.755 280.000 35.825 ;
    END
  END cfg_mgmt_read_data[7]
  PIN cfg_mgmt_read_data[8]
    DIRECTION OUTPUT ;
    USE SIGNAL ;
    PORT
      LAYER metal3 ;
      RECT 279.620 36.135 280.000 36.205 ;
    END
  END cfg_mgmt_read_data[8]
  PIN cfg_mgmt_read_data[9]
    DIRECTION OUTPUT ;
    USE SIGNAL ;
    PORT
      LAYER metal3 ;
      RECT 279.620 36.515 280.000 36.585 ;
    END
  END cfg_mgmt_read_data[9]
  PIN cfg_mgmt_read_data[10]
    DIRECTION OUTPUT ;
    USE SIGNAL ;
    PORT
      LAYER metal3 ;
      RECT 279.620 36.895 280.000 36.965 ;
    END
  END cfg_mgmt_read_data[10]
  PIN cfg_mgmt_read_data[11]
    DIRECTION OUTPUT ;
    USE SIGNAL ;
    PORT
      LAYER metal3 ;
      RECT 279.620 37.275 280.000 37.345 ;
    END
  END cfg_mgmt_read_data[11]
  PIN cfg_mgmt_read_data[12]
    DIRECTION OUTPUT ;
    USE SIGNAL ;
    PORT
      LAYER metal3 ;
      RECT 279.620 37.655 280.000 37.725 ;
    END
  END cfg_mgmt_read_data[12]
  PIN cfg_mgmt_read_data[13]
    DIRECTION OUTPUT ;
    USE SIGNAL ;
    PORT
      LAYER metal3 ;
      RECT 279.620 38.035 280.000 38.105 ;
    END
  END cfg_mgmt_read_data[13]
  PIN cfg_mgmt_read_data[14]
    DIRECTION OUTPUT ;
    USE SIGNAL ;
    PORT
      LAYER metal3 ;
      RECT 279.620 38.415 280.000 38.485 ;
    END
  END cfg_mgmt_read_data[14]
  PIN cfg_mgmt_read_data[15]
    DIRECTION OUTPUT ;
    USE SIGNAL ;
    PORT
      LAYER metal3 ;
      RECT 279.620 38.795 280.000 38.865 ;
    END
  END cfg_mgmt_read_data[15]
  PIN cfg_mgmt_read_data[16]
    DIRECTION OUTPUT ;
    USE SIGNAL ;
    PORT
      LAYER metal3 ;
      RECT 279.620 39.175 280.000 39.245 ;
    END
  END cfg_mgmt_read_data[16]
  PIN cfg_mgmt_read_data[17]
    DIRECTION OUTPUT ;
    USE SIGNAL ;
    PORT
      LAYER metal3 ;
      RECT 279.620 39.555 280.000 39.625 ;
    END
  END cfg_mgmt_read_data[17]
  PIN cfg_mgmt_read_data[18]
    DIRECTION OUTPUT ;
    USE SIGNAL ;
    PORT
      LAYER metal3 ;
      RECT 279.620 39.935 280.000 40.005 ;
    END
  END cfg_mgmt_read_data[18]
  PIN cfg_mgmt_read_data[19]
    DIRECTION OUTPUT ;
    USE SIGNAL ;
    PORT
      LAYER metal3 ;
      RECT 279.620 40.315 280.000 40.385 ;
    END
  END cfg_mgmt_read_data[19]
  PIN cfg_mgmt_read_data[20]
    DIRECTION OUTPUT ;
    USE SIGNAL ;
    PORT
      LAYER metal3 ;
      RECT 279.620 40.695 280.000 40.765 ;
    END
  END cfg_mgmt_read_data[20]
  PIN cfg_mgmt_read_data[21]
    DIRECTION OUTPUT ;
    USE SIGNAL ;
    PORT
      LAYER metal3 ;
      RECT 279.620 41.075 280.000 41.145 ;
    END
  END cfg_mgmt_read_data[21]
  PIN cfg_mgmt_read_data[22]
    DIRECTION OUTPUT ;
    USE SIGNAL ;
    PORT
      LAYER metal3 ;
      RECT 279.620 41.455 280.000 41.525 ;
    END
  END cfg_mgmt_read_data[22]
  PIN cfg_mgmt_read_data[23]
    DIRECTION OUTPUT ;
    USE SIGNAL ;
    PORT
      LAYER metal3 ;
      RECT 279.620 41.835 280.000 41.905 ;
    END
  END cfg_mgmt_read_data[23]
  PIN cfg_mgmt_read_data[24]
    DIRECTION OUTPUT ;
    USE SIGNAL ;
    PORT
      LAYER metal3 ;
      RECT 279.620 42.215 280.000 42.285 ;
    END
  END cfg_mgmt_read_data[24]
  PIN cfg_mgmt_read_data[25]
    DIRECTION OUTPUT ;
    USE SIGNAL ;
    PORT
      LAYER metal3 ;
      RECT 279.620 42.595 280.000 42.665 ;
    END
  END cfg_mgmt_read_data[25]
  PIN cfg_mgmt_read_data[26]
    DIRECTION OUTPUT ;
    USE SIGNAL ;
    PORT
      LAYER metal3 ;
      RECT 279.620 42.975 280.000 43.045 ;
    END
  END cfg_mgmt_read_data[26]
  PIN cfg_mgmt_read_data[27]
    DIRECTION OUTPUT ;
    USE SIGNAL ;
    PORT
      LAYER metal3 ;
      RECT 279.620 43.355 280.000 43.425 ;
    END
  END cfg_mgmt_read_data[27]
  PIN cfg_mgmt_read_data[28]
    DIRECTION OUTPUT ;
    USE SIGNAL ;
    PORT
      LAYER metal3 ;
      RECT 279.620 43.735 280.000 43.805 ;
    END
  END cfg_mgmt_read_data[28]
  PIN cfg_mgmt_read_data[29]
    DIRECTION OUTPUT ;
    USE SIGNAL ;
    PORT
      LAYER metal3 ;
      RECT 279.620 44.115 280.000 44.185 ;
    END
  END cfg_mgmt_read_data[29]
  PIN cfg_mgmt_read_data[30]
    DIRECTION OUTPUT ;
    USE SIGNAL ;
    PORT
      LAYER metal3 ;
      RECT 279.620 44.495 280.000 44.565 ;
    END
  END cfg_mgmt_read_data[30]
  PIN cfg_mgmt_read_data[31]
    DIRECTION OUTPUT ;
    USE SIGNAL ;
    PORT
      LAYER metal3 ;
      RECT 279.620 44.875 280.000 44.945 ;
    END
  END cfg_mgmt_read_data[31]
  PIN cfg_mgmt_read_write_done
    DIRECTION OUTPUT ;
    USE SIGNAL ;
    PORT
      LAYER metal3 ;
      RECT 279.620 45.255 280.000 45.325 ;
    END
  END cfg_mgmt_read_write_done
  PIN cfg_msg_received
    DIRECTION OUTPUT ;
    USE SIGNAL ;
    PORT
      LAYER metal3 ;
      RECT 279.620 45.635 280.000 45.705 ;
    END
  END cfg_msg_received
  PIN cfg_msg_received_data[0]
    DIRECTION OUTPUT ;
    USE SIGNAL ;
    PORT
      LAYER metal3 ;
      RECT 279.620 46.015 280.000 46.085 ;
    END
  END cfg_msg_received_data[0]
  PIN cfg_msg_received_data[1]
    DIRECTION OUTPUT ;
    USE SIGNAL ;
    PORT
      LAYER metal3 ;
      RECT 279.620 46.395 280.000 46.465 ;
    END
  END cfg_msg_received_data[1]
  PIN cfg_msg_received_data[2]
    DIRECTION OUTPUT ;
    USE SIGNAL ;
    PORT
      LAYER metal3 ;
      RECT 279.620 46.775 280.000 46.845 ;
    END
  END cfg_msg_received_data[2]
  PIN cfg_msg_received_data[3]
    DIRECTION OUTPUT ;
    USE SIGNAL ;
    PORT
      LAYER metal3 ;
      RECT 279.620 47.155 280.000 47.225 ;
    END
  END cfg_msg_received_data[3]
  PIN cfg_msg_received_data[4]
    DIRECTION OUTPUT ;
    USE SIGNAL ;
    PORT
      LAYER metal3 ;
      RECT 279.620 47.535 280.000 47.605 ;
    END
  END cfg_msg_received_data[4]
  PIN cfg_msg_received_data[5]
    DIRECTION OUTPUT ;
    USE SIGNAL ;
    PORT
      LAYER metal3 ;
      RECT 279.620 47.915 280.000 47.985 ;
    END
  END cfg_msg_received_data[5]
  PIN cfg_msg_received_data[6]
    DIRECTION OUTPUT ;
    USE SIGNAL ;
    PORT
      LAYER metal3 ;
      RECT 279.620 48.295 280.000 48.365 ;
    END
  END cfg_msg_received_data[6]
  PIN cfg_msg_received_data[7]
    DIRECTION OUTPUT ;
    USE SIGNAL ;
    PORT
      LAYER metal3 ;
      RECT 279.620 48.675 280.000 48.745 ;
    END
  END cfg_msg_received_data[7]
  PIN cfg_msg_received_type[0]
    DIRECTION OUTPUT ;
    USE SIGNAL ;
    PORT
      LAYER metal3 ;
      RECT 279.620 49.055 280.000 49.125 ;
    END
  END cfg_msg_received_type[0]
  PIN cfg_msg_received_type[1]
    DIRECTION OUTPUT ;
    USE SIGNAL ;
    PORT
      LAYER metal3 ;
      RECT 279.620 49.435 280.000 49.505 ;
    END
  END cfg_msg_received_type[1]
  PIN cfg_msg_received_type[2]
    DIRECTION OUTPUT ;
    USE SIGNAL ;
    PORT
      LAYER metal3 ;
      RECT 279.620 49.815 280.000 49.885 ;
    END
  END cfg_msg_received_type[2]
  PIN cfg_msg_received_type[3]
    DIRECTION OUTPUT ;
    USE SIGNAL ;
    PORT
      LAYER metal3 ;
      RECT 279.620 50.195 280.000 50.265 ;
    END
  END cfg_msg_received_type[3]
  PIN cfg_msg_received_type[4]
    DIRECTION OUTPUT ;
    USE SIGNAL ;
    PORT
      LAYER metal3 ;
      RECT 279.620 50.575 280.000 50.645 ;
    END
  END cfg_msg_received_type[4]
  PIN cfg_msg_transmit_done
    DIRECTION OUTPUT ;
    USE SIGNAL ;
    PORT
      LAYER metal3 ;
      RECT 279.620 50.955 280.000 51.025 ;
    END
  END cfg_msg_transmit_done
  PIN cfg_negotiated_width[0]
    DIRECTION OUTPUT ;
    USE SIGNAL ;
    PORT
      LAYER metal3 ;
      RECT 279.620 51.335 280.000 51.405 ;
    END
  END cfg_negotiated_width[0]
  PIN cfg_negotiated_width[1]
    DIRECTION OUTPUT ;
    USE SIGNAL ;
    PORT
      LAYER metal3 ;
      RECT 279.620 51.715 280.000 51.785 ;
    END
  END cfg_negotiated_width[1]
  PIN cfg_negotiated_width[2]
    DIRECTION OUTPUT ;
    USE SIGNAL ;
    PORT
      LAYER metal3 ;
      RECT 279.620 52.095 280.000 52.165 ;
    END
  END cfg_negotiated_width[2]
  PIN cfg_negotiated_width[3]
    DIRECTION OUTPUT ;
    USE SIGNAL ;
    PORT
      LAYER metal3 ;
      RECT 279.620 52.475 280.000 52.545 ;
    END
  END cfg_negotiated_width[3]
  PIN cfg_obff_enable[0]
    DIRECTION OUTPUT ;
    USE SIGNAL ;
    PORT
      LAYER metal3 ;
      RECT 279.620 52.855 280.000 52.925 ;
    END
  END cfg_obff_enable[0]
  PIN cfg_obff_enable[1]
    DIRECTION OUTPUT ;
    USE SIGNAL ;
    PORT
      LAYER metal3 ;
      RECT 279.620 53.235 280.000 53.305 ;
    END
  END cfg_obff_enable[1]
  PIN cfg_per_func_status_data[0]
    DIRECTION OUTPUT ;
    USE SIGNAL ;
    PORT
      LAYER metal3 ;
      RECT 279.620 53.615 280.000 53.685 ;
    END
  END cfg_per_func_status_data[0]
  PIN cfg_per_func_status_data[1]
    DIRECTION OUTPUT ;
    USE SIGNAL ;
    PORT
      LAYER metal3 ;
      RECT 279.620 53.995 280.000 54.065 ;
    END
  END cfg_per_func_status_data[1]
  PIN cfg_per_func_status_data[2]
    DIRECTION OUTPUT ;
    USE SIGNAL ;
    PORT
      LAYER metal3 ;
      RECT 279.620 54.375 280.000 54.445 ;
    END
  END cfg_per_func_status_data[2]
  PIN cfg_per_func_status_data[3]
    DIRECTION OUTPUT ;
    USE SIGNAL ;
    PORT
      LAYER metal3 ;
      RECT 279.620 54.755 280.000 54.825 ;
    END
  END cfg_per_func_status_data[3]
  PIN cfg_per_func_status_data[4]
    DIRECTION OUTPUT ;
    USE SIGNAL ;
    PORT
      LAYER metal3 ;
      RECT 279.620 55.135 280.000 55.205 ;
    END
  END cfg_per_func_status_data[4]
  PIN cfg_per_func_status_data[5]
    DIRECTION OUTPUT ;
    USE SIGNAL ;
    PORT
      LAYER metal3 ;
      RECT 279.620 55.515 280.000 55.585 ;
    END
  END cfg_per_func_status_data[5]
  PIN cfg_per_func_status_data[6]
    DIRECTION OUTPUT ;
    USE SIGNAL ;
    PORT
      LAYER metal3 ;
      RECT 279.620 55.895 280.000 55.965 ;
    END
  END cfg_per_func_status_data[6]
  PIN cfg_per_func_status_data[7]
    DIRECTION OUTPUT ;
    USE SIGNAL ;
    PORT
      LAYER metal3 ;
      RECT 279.620 56.275 280.000 56.345 ;
    END
  END cfg_per_func_status_data[7]
  PIN cfg_per_func_status_data[8]
    DIRECTION OUTPUT ;
    USE SIGNAL ;
    PORT
      LAYER metal3 ;
      RECT 279.620 56.655 280.000 56.725 ;
    END
  END cfg_per_func_status_data[8]
  PIN cfg_per_func_status_data[9]
    DIRECTION OUTPUT ;
    USE SIGNAL ;
    PORT
      LAYER metal3 ;
      RECT 279.620 57.035 280.000 57.105 ;
    END
  END cfg_per_func_status_data[9]
  PIN cfg_per_func_status_data[10]
    DIRECTION OUTPUT ;
    USE SIGNAL ;
    PORT
      LAYER metal3 ;
      RECT 279.620 57.415 280.000 57.485 ;
    END
  END cfg_per_func_status_data[10]
  PIN cfg_per_func_status_data[11]
    DIRECTION OUTPUT ;
    USE SIGNAL ;
    PORT
      LAYER metal3 ;
      RECT 279.620 57.795 280.000 57.865 ;
    END
  END cfg_per_func_status_data[11]
  PIN cfg_per_func_status_data[12]
    DIRECTION OUTPUT ;
    USE SIGNAL ;
    PORT
      LAYER metal3 ;
      RECT 279.620 58.175 280.000 58.245 ;
    END
  END cfg_per_func_status_data[12]
  PIN cfg_per_func_status_data[13]
    DIRECTION OUTPUT ;
    USE SIGNAL ;
    PORT
      LAYER metal3 ;
      RECT 279.620 58.555 280.000 58.625 ;
    END
  END cfg_per_func_status_data[13]
  PIN cfg_per_func_status_data[14]
    DIRECTION OUTPUT ;
    USE SIGNAL ;
    PORT
      LAYER metal3 ;
      RECT 279.620 58.935 280.000 59.005 ;
    END
  END cfg_per_func_status_data[14]
  PIN cfg_per_func_status_data[15]
    DIRECTION OUTPUT ;
    USE SIGNAL ;
    PORT
      LAYER metal3 ;
      RECT 279.620 59.315 280.000 59.385 ;
    END
  END cfg_per_func_status_data[15]
  PIN cfg_per_function_update_done
    DIRECTION OUTPUT ;
    USE SIGNAL ;
    PORT
      LAYER metal3 ;
      RECT 279.620 59.695 280.000 59.765 ;
    END
  END cfg_per_function_update_done
  PIN cfg_phy_link_down
    DIRECTION OUTPUT ;
    USE SIGNAL ;
    PORT
      LAYER metal3 ;
      RECT 279.620 60.075 280.000 60.145 ;
    END
  END cfg_phy_link_down
  PIN cfg_phy_link_status[0]
    DIRECTION OUTPUT ;
    USE SIGNAL ;
    PORT
      LAYER metal3 ;
      RECT 279.620 60.455 280.000 60.525 ;
    END
  END cfg_phy_link_status[0]
  PIN cfg_phy_link_status[1]
    DIRECTION OUTPUT ;
    USE SIGNAL ;
    PORT
      LAYER metal3 ;
      RECT 279.620 60.835 280.000 60.905 ;
    END
  END cfg_phy_link_status[1]
  PIN cfg_pl_status_change
    DIRECTION OUTPUT ;
    USE SIGNAL ;
    PORT
      LAYER metal3 ;
      RECT 279.620 61.215 280.000 61.285 ;
    END
  END cfg_pl_status_change
  PIN cfg_power_state_change_interrupt
    DIRECTION OUTPUT ;
    USE SIGNAL ;
    PORT
      LAYER metal3 ;
      RECT 279.620 61.595 280.000 61.665 ;
    END
  END cfg_power_state_change_interrupt
  PIN cfg_rcb_status[0]
    DIRECTION OUTPUT ;
    USE SIGNAL ;
    PORT
      LAYER metal3 ;
      RECT 279.620 61.975 280.000 62.045 ;
    END
  END cfg_rcb_status[0]
  PIN cfg_rcb_status[1]
    DIRECTION OUTPUT ;
    USE SIGNAL ;
    PORT
      LAYER metal3 ;
      RECT 279.620 62.355 280.000 62.425 ;
    END
  END cfg_rcb_status[1]
  PIN cfg_rcb_status[2]
    DIRECTION OUTPUT ;
    USE SIGNAL ;
    PORT
      LAYER metal3 ;
      RECT 279.620 62.735 280.000 62.805 ;
    END
  END cfg_rcb_status[2]
  PIN cfg_rcb_status[3]
    DIRECTION OUTPUT ;
    USE SIGNAL ;
    PORT
      LAYER metal3 ;
      RECT 279.620 63.115 280.000 63.185 ;
    END
  END cfg_rcb_status[3]
  PIN cfg_tph_requester_enable[0]
    DIRECTION OUTPUT ;
    USE SIGNAL ;
    PORT
      LAYER metal3 ;
      RECT 279.620 63.495 280.000 63.565 ;
    END
  END cfg_tph_requester_enable[0]
  PIN cfg_tph_requester_enable[1]
    DIRECTION OUTPUT ;
    USE SIGNAL ;
    PORT
      LAYER metal3 ;
      RECT 279.620 63.875 280.000 63.945 ;
    END
  END cfg_tph_requester_enable[1]
  PIN cfg_tph_requester_enable[2]
    DIRECTION OUTPUT ;
    USE SIGNAL ;
    PORT
      LAYER metal3 ;
      RECT 279.620 64.255 280.000 64.325 ;
    END
  END cfg_tph_requester_enable[2]
  PIN cfg_tph_requester_enable[3]
    DIRECTION OUTPUT ;
    USE SIGNAL ;
    PORT
      LAYER metal3 ;
      RECT 279.620 64.635 280.000 64.705 ;
    END
  END cfg_tph_requester_enable[3]
  PIN cfg_tph_st_mode[0]
    DIRECTION OUTPUT ;
    USE SIGNAL ;
    PORT
      LAYER metal3 ;
      RECT 279.620 65.015 280.000 65.085 ;
    END
  END cfg_tph_st_mode[0]
  PIN cfg_tph_st_mode[1]
    DIRECTION OUTPUT ;
    USE SIGNAL ;
    PORT
      LAYER metal3 ;
      RECT 279.620 65.395 280.000 65.465 ;
    END
  END cfg_tph_st_mode[1]
  PIN cfg_tph_st_mode[2]
    DIRECTION OUTPUT ;
    USE SIGNAL ;
    PORT
      LAYER metal3 ;
      RECT 279.620 65.775 280.000 65.845 ;
    END
  END cfg_tph_st_mode[2]
  PIN cfg_tph_st_mode[3]
    DIRECTION OUTPUT ;
    USE SIGNAL ;
    PORT
      LAYER metal3 ;
      RECT 279.620 66.155 280.000 66.225 ;
    END
  END cfg_tph_st_mode[3]
  PIN cfg_tph_st_mode[4]
    DIRECTION OUTPUT ;
    USE SIGNAL ;
    PORT
      LAYER metal3 ;
      RECT 279.620 66.535 280.000 66.605 ;
    END
  END cfg_tph_st_mode[4]
  PIN cfg_tph_st_mode[5]
    DIRECTION OUTPUT ;
    USE SIGNAL ;
    PORT
      LAYER metal3 ;
      RECT 279.620 66.915 280.000 66.985 ;
    END
  END cfg_tph_st_mode[5]
  PIN cfg_tph_st_mode[6]
    DIRECTION OUTPUT ;
    USE SIGNAL ;
    PORT
      LAYER metal3 ;
      RECT 279.620 67.295 280.000 67.365 ;
    END
  END cfg_tph_st_mode[6]
  PIN cfg_tph_st_mode[7]
    DIRECTION OUTPUT ;
    USE SIGNAL ;
    PORT
      LAYER metal3 ;
      RECT 279.620 67.675 280.000 67.745 ;
    END
  END cfg_tph_st_mode[7]
  PIN cfg_tph_st_mode[8]
    DIRECTION OUTPUT ;
    USE SIGNAL ;
    PORT
      LAYER metal3 ;
      RECT 279.620 68.055 280.000 68.125 ;
    END
  END cfg_tph_st_mode[8]
  PIN cfg_tph_st_mode[9]
    DIRECTION OUTPUT ;
    USE SIGNAL ;
    PORT
      LAYER metal3 ;
      RECT 279.620 68.435 280.000 68.505 ;
    END
  END cfg_tph_st_mode[9]
  PIN cfg_tph_st_mode[10]
    DIRECTION OUTPUT ;
    USE SIGNAL ;
    PORT
      LAYER metal3 ;
      RECT 279.620 68.815 280.000 68.885 ;
    END
  END cfg_tph_st_mode[10]
  PIN cfg_tph_st_mode[11]
    DIRECTION OUTPUT ;
    USE SIGNAL ;
    PORT
      LAYER metal3 ;
      RECT 279.620 69.195 280.000 69.265 ;
    END
  END cfg_tph_st_mode[11]
  PIN cfg_vf_flr_in_process[0]
    DIRECTION OUTPUT ;
    USE SIGNAL ;
    PORT
      LAYER metal3 ;
      RECT 279.620 69.575 280.000 69.645 ;
    END
  END cfg_vf_flr_in_process[0]
  PIN cfg_vf_flr_in_process[1]
    DIRECTION OUTPUT ;
    USE SIGNAL ;
    PORT
      LAYER metal3 ;
      RECT 279.620 69.955 280.000 70.025 ;
    END
  END cfg_vf_flr_in_process[1]
  PIN cfg_vf_flr_in_process[2]
    DIRECTION OUTPUT ;
    USE SIGNAL ;
    PORT
      LAYER metal3 ;
      RECT 279.620 70.335 280.000 70.405 ;
    END
  END cfg_vf_flr_in_process[2]
  PIN cfg_vf_flr_in_process[3]
    DIRECTION OUTPUT ;
    USE SIGNAL ;
    PORT
      LAYER metal3 ;
      RECT 279.620 70.715 280.000 70.785 ;
    END
  END cfg_vf_flr_in_process[3]
  PIN cfg_vf_flr_in_process[4]
    DIRECTION OUTPUT ;
    USE SIGNAL ;
    PORT
      LAYER metal3 ;
      RECT 279.620 71.095 280.000 71.165 ;
    END
  END cfg_vf_flr_in_process[4]
  PIN cfg_vf_flr_in_process[5]
    DIRECTION OUTPUT ;
    USE SIGNAL ;
    PORT
      LAYER metal3 ;
      RECT 279.620 71.475 280.000 71.545 ;
    END
  END cfg_vf_flr_in_process[5]
  PIN cfg_vf_flr_in_process[6]
    DIRECTION OUTPUT ;
    USE SIGNAL ;
    PORT
      LAYER metal3 ;
      RECT 279.620 71.855 280.000 71.925 ;
    END
  END cfg_vf_flr_in_process[6]
  PIN cfg_vf_flr_in_process[7]
    DIRECTION OUTPUT ;
    USE SIGNAL ;
    PORT
      LAYER metal3 ;
      RECT 279.620 72.235 280.000 72.305 ;
    END
  END cfg_vf_flr_in_process[7]
  PIN int_qpll1lock_out
    DIRECTION OUTPUT ;
    USE SIGNAL ;
    PORT
      LAYER metal3 ;
      RECT 279.620 72.615 280.000 72.685 ;
    END
  END int_qpll1lock_out
  PIN int_qpll1outclk_out
    DIRECTION OUTPUT ;
    USE SIGNAL ;
    PORT
      LAYER metal3 ;
      RECT 279.620 72.995 280.000 73.065 ;
    END
  END int_qpll1outclk_out
  PIN int_qpll1outrefclk_out
    DIRECTION OUTPUT ;
    USE SIGNAL ;
    PORT
      LAYER metal3 ;
      RECT 279.620 73.375 280.000 73.445 ;
    END
  END int_qpll1outrefclk_out
  PIN m_axis_cq_tdata[0]
    DIRECTION OUTPUT ;
    USE SIGNAL ;
    PORT
      LAYER metal3 ;
      RECT 279.620 73.755 280.000 73.825 ;
    END
  END m_axis_cq_tdata[0]
  PIN m_axis_cq_tdata[1]
    DIRECTION OUTPUT ;
    USE SIGNAL ;
    PORT
      LAYER metal3 ;
      RECT 279.620 74.135 280.000 74.205 ;
    END
  END m_axis_cq_tdata[1]
  PIN m_axis_cq_tdata[2]
    DIRECTION OUTPUT ;
    USE SIGNAL ;
    PORT
      LAYER metal3 ;
      RECT 279.620 74.515 280.000 74.585 ;
    END
  END m_axis_cq_tdata[2]
  PIN m_axis_cq_tdata[3]
    DIRECTION OUTPUT ;
    USE SIGNAL ;
    PORT
      LAYER metal3 ;
      RECT 279.620 74.895 280.000 74.965 ;
    END
  END m_axis_cq_tdata[3]
  PIN m_axis_cq_tdata[4]
    DIRECTION OUTPUT ;
    USE SIGNAL ;
    PORT
      LAYER metal3 ;
      RECT 279.620 75.275 280.000 75.345 ;
    END
  END m_axis_cq_tdata[4]
  PIN m_axis_cq_tdata[5]
    DIRECTION OUTPUT ;
    USE SIGNAL ;
    PORT
      LAYER metal3 ;
      RECT 279.620 75.655 280.000 75.725 ;
    END
  END m_axis_cq_tdata[5]
  PIN m_axis_cq_tdata[6]
    DIRECTION OUTPUT ;
    USE SIGNAL ;
    PORT
      LAYER metal3 ;
      RECT 279.620 76.035 280.000 76.105 ;
    END
  END m_axis_cq_tdata[6]
  PIN m_axis_cq_tdata[7]
    DIRECTION OUTPUT ;
    USE SIGNAL ;
    PORT
      LAYER metal3 ;
      RECT 279.620 76.415 280.000 76.485 ;
    END
  END m_axis_cq_tdata[7]
  PIN m_axis_cq_tdata[8]
    DIRECTION OUTPUT ;
    USE SIGNAL ;
    PORT
      LAYER metal3 ;
      RECT 279.620 76.795 280.000 76.865 ;
    END
  END m_axis_cq_tdata[8]
  PIN m_axis_cq_tdata[9]
    DIRECTION OUTPUT ;
    USE SIGNAL ;
    PORT
      LAYER metal3 ;
      RECT 279.620 77.175 280.000 77.245 ;
    END
  END m_axis_cq_tdata[9]
  PIN m_axis_cq_tdata[10]
    DIRECTION OUTPUT ;
    USE SIGNAL ;
    PORT
      LAYER metal3 ;
      RECT 279.620 77.555 280.000 77.625 ;
    END
  END m_axis_cq_tdata[10]
  PIN m_axis_cq_tdata[11]
    DIRECTION OUTPUT ;
    USE SIGNAL ;
    PORT
      LAYER metal3 ;
      RECT 279.620 77.935 280.000 78.005 ;
    END
  END m_axis_cq_tdata[11]
  PIN m_axis_cq_tdata[12]
    DIRECTION OUTPUT ;
    USE SIGNAL ;
    PORT
      LAYER metal3 ;
      RECT 279.620 78.315 280.000 78.385 ;
    END
  END m_axis_cq_tdata[12]
  PIN m_axis_cq_tdata[13]
    DIRECTION OUTPUT ;
    USE SIGNAL ;
    PORT
      LAYER metal3 ;
      RECT 279.620 78.695 280.000 78.765 ;
    END
  END m_axis_cq_tdata[13]
  PIN m_axis_cq_tdata[14]
    DIRECTION OUTPUT ;
    USE SIGNAL ;
    PORT
      LAYER metal3 ;
      RECT 279.620 79.075 280.000 79.145 ;
    END
  END m_axis_cq_tdata[14]
  PIN m_axis_cq_tdata[15]
    DIRECTION OUTPUT ;
    USE SIGNAL ;
    PORT
      LAYER metal3 ;
      RECT 279.620 79.455 280.000 79.525 ;
    END
  END m_axis_cq_tdata[15]
  PIN m_axis_cq_tdata[16]
    DIRECTION OUTPUT ;
    USE SIGNAL ;
    PORT
      LAYER metal3 ;
      RECT 279.620 79.835 280.000 79.905 ;
    END
  END m_axis_cq_tdata[16]
  PIN m_axis_cq_tdata[17]
    DIRECTION OUTPUT ;
    USE SIGNAL ;
    PORT
      LAYER metal3 ;
      RECT 279.620 80.215 280.000 80.285 ;
    END
  END m_axis_cq_tdata[17]
  PIN m_axis_cq_tdata[18]
    DIRECTION OUTPUT ;
    USE SIGNAL ;
    PORT
      LAYER metal3 ;
      RECT 279.620 80.595 280.000 80.665 ;
    END
  END m_axis_cq_tdata[18]
  PIN m_axis_cq_tdata[19]
    DIRECTION OUTPUT ;
    USE SIGNAL ;
    PORT
      LAYER metal3 ;
      RECT 279.620 80.975 280.000 81.045 ;
    END
  END m_axis_cq_tdata[19]
  PIN m_axis_cq_tdata[20]
    DIRECTION OUTPUT ;
    USE SIGNAL ;
    PORT
      LAYER metal3 ;
      RECT 279.620 81.355 280.000 81.425 ;
    END
  END m_axis_cq_tdata[20]
  PIN m_axis_cq_tdata[21]
    DIRECTION OUTPUT ;
    USE SIGNAL ;
    PORT
      LAYER metal3 ;
      RECT 279.620 81.735 280.000 81.805 ;
    END
  END m_axis_cq_tdata[21]
  PIN m_axis_cq_tdata[22]
    DIRECTION OUTPUT ;
    USE SIGNAL ;
    PORT
      LAYER metal3 ;
      RECT 279.620 82.115 280.000 82.185 ;
    END
  END m_axis_cq_tdata[22]
  PIN m_axis_cq_tdata[23]
    DIRECTION OUTPUT ;
    USE SIGNAL ;
    PORT
      LAYER metal3 ;
      RECT 279.620 82.495 280.000 82.565 ;
    END
  END m_axis_cq_tdata[23]
  PIN m_axis_cq_tdata[24]
    DIRECTION OUTPUT ;
    USE SIGNAL ;
    PORT
      LAYER metal3 ;
      RECT 279.620 82.875 280.000 82.945 ;
    END
  END m_axis_cq_tdata[24]
  PIN m_axis_cq_tdata[25]
    DIRECTION OUTPUT ;
    USE SIGNAL ;
    PORT
      LAYER metal3 ;
      RECT 279.620 83.255 280.000 83.325 ;
    END
  END m_axis_cq_tdata[25]
  PIN m_axis_cq_tdata[26]
    DIRECTION OUTPUT ;
    USE SIGNAL ;
    PORT
      LAYER metal3 ;
      RECT 279.620 83.635 280.000 83.705 ;
    END
  END m_axis_cq_tdata[26]
  PIN m_axis_cq_tdata[27]
    DIRECTION OUTPUT ;
    USE SIGNAL ;
    PORT
      LAYER metal3 ;
      RECT 279.620 84.015 280.000 84.085 ;
    END
  END m_axis_cq_tdata[27]
  PIN m_axis_cq_tdata[28]
    DIRECTION OUTPUT ;
    USE SIGNAL ;
    PORT
      LAYER metal3 ;
      RECT 279.620 84.395 280.000 84.465 ;
    END
  END m_axis_cq_tdata[28]
  PIN m_axis_cq_tdata[29]
    DIRECTION OUTPUT ;
    USE SIGNAL ;
    PORT
      LAYER metal3 ;
      RECT 279.620 84.775 280.000 84.845 ;
    END
  END m_axis_cq_tdata[29]
  PIN m_axis_cq_tdata[30]
    DIRECTION OUTPUT ;
    USE SIGNAL ;
    PORT
      LAYER metal3 ;
      RECT 279.620 85.155 280.000 85.225 ;
    END
  END m_axis_cq_tdata[30]
  PIN m_axis_cq_tdata[31]
    DIRECTION OUTPUT ;
    USE SIGNAL ;
    PORT
      LAYER metal3 ;
      RECT 279.620 85.535 280.000 85.605 ;
    END
  END m_axis_cq_tdata[31]
  PIN m_axis_cq_tdata[32]
    DIRECTION OUTPUT ;
    USE SIGNAL ;
    PORT
      LAYER metal3 ;
      RECT 279.620 85.915 280.000 85.985 ;
    END
  END m_axis_cq_tdata[32]
  PIN m_axis_cq_tdata[33]
    DIRECTION OUTPUT ;
    USE SIGNAL ;
    PORT
      LAYER metal3 ;
      RECT 279.620 86.295 280.000 86.365 ;
    END
  END m_axis_cq_tdata[33]
  PIN m_axis_cq_tdata[34]
    DIRECTION OUTPUT ;
    USE SIGNAL ;
    PORT
      LAYER metal3 ;
      RECT 279.620 86.675 280.000 86.745 ;
    END
  END m_axis_cq_tdata[34]
  PIN m_axis_cq_tdata[35]
    DIRECTION OUTPUT ;
    USE SIGNAL ;
    PORT
      LAYER metal3 ;
      RECT 279.620 87.055 280.000 87.125 ;
    END
  END m_axis_cq_tdata[35]
  PIN m_axis_cq_tdata[36]
    DIRECTION OUTPUT ;
    USE SIGNAL ;
    PORT
      LAYER metal3 ;
      RECT 279.620 87.435 280.000 87.505 ;
    END
  END m_axis_cq_tdata[36]
  PIN m_axis_cq_tdata[37]
    DIRECTION OUTPUT ;
    USE SIGNAL ;
    PORT
      LAYER metal3 ;
      RECT 279.620 87.815 280.000 87.885 ;
    END
  END m_axis_cq_tdata[37]
  PIN m_axis_cq_tdata[38]
    DIRECTION OUTPUT ;
    USE SIGNAL ;
    PORT
      LAYER metal3 ;
      RECT 279.620 88.195 280.000 88.265 ;
    END
  END m_axis_cq_tdata[38]
  PIN m_axis_cq_tdata[39]
    DIRECTION OUTPUT ;
    USE SIGNAL ;
    PORT
      LAYER metal3 ;
      RECT 279.620 88.575 280.000 88.645 ;
    END
  END m_axis_cq_tdata[39]
  PIN m_axis_cq_tdata[40]
    DIRECTION OUTPUT ;
    USE SIGNAL ;
    PORT
      LAYER metal3 ;
      RECT 279.620 88.955 280.000 89.025 ;
    END
  END m_axis_cq_tdata[40]
  PIN m_axis_cq_tdata[41]
    DIRECTION OUTPUT ;
    USE SIGNAL ;
    PORT
      LAYER metal3 ;
      RECT 279.620 89.335 280.000 89.405 ;
    END
  END m_axis_cq_tdata[41]
  PIN m_axis_cq_tdata[42]
    DIRECTION OUTPUT ;
    USE SIGNAL ;
    PORT
      LAYER metal3 ;
      RECT 279.620 89.715 280.000 89.785 ;
    END
  END m_axis_cq_tdata[42]
  PIN m_axis_cq_tdata[43]
    DIRECTION OUTPUT ;
    USE SIGNAL ;
    PORT
      LAYER metal3 ;
      RECT 279.620 90.095 280.000 90.165 ;
    END
  END m_axis_cq_tdata[43]
  PIN m_axis_cq_tdata[44]
    DIRECTION OUTPUT ;
    USE SIGNAL ;
    PORT
      LAYER metal3 ;
      RECT 279.620 90.475 280.000 90.545 ;
    END
  END m_axis_cq_tdata[44]
  PIN m_axis_cq_tdata[45]
    DIRECTION OUTPUT ;
    USE SIGNAL ;
    PORT
      LAYER metal3 ;
      RECT 279.620 90.855 280.000 90.925 ;
    END
  END m_axis_cq_tdata[45]
  PIN m_axis_cq_tdata[46]
    DIRECTION OUTPUT ;
    USE SIGNAL ;
    PORT
      LAYER metal3 ;
      RECT 279.620 91.235 280.000 91.305 ;
    END
  END m_axis_cq_tdata[46]
  PIN m_axis_cq_tdata[47]
    DIRECTION OUTPUT ;
    USE SIGNAL ;
    PORT
      LAYER metal3 ;
      RECT 279.620 91.615 280.000 91.685 ;
    END
  END m_axis_cq_tdata[47]
  PIN m_axis_cq_tdata[48]
    DIRECTION OUTPUT ;
    USE SIGNAL ;
    PORT
      LAYER metal3 ;
      RECT 279.620 91.995 280.000 92.065 ;
    END
  END m_axis_cq_tdata[48]
  PIN m_axis_cq_tdata[49]
    DIRECTION OUTPUT ;
    USE SIGNAL ;
    PORT
      LAYER metal3 ;
      RECT 279.620 92.375 280.000 92.445 ;
    END
  END m_axis_cq_tdata[49]
  PIN m_axis_cq_tdata[50]
    DIRECTION OUTPUT ;
    USE SIGNAL ;
    PORT
      LAYER metal3 ;
      RECT 279.620 92.755 280.000 92.825 ;
    END
  END m_axis_cq_tdata[50]
  PIN m_axis_cq_tdata[51]
    DIRECTION OUTPUT ;
    USE SIGNAL ;
    PORT
      LAYER metal3 ;
      RECT 279.620 93.135 280.000 93.205 ;
    END
  END m_axis_cq_tdata[51]
  PIN m_axis_cq_tdata[52]
    DIRECTION OUTPUT ;
    USE SIGNAL ;
    PORT
      LAYER metal3 ;
      RECT 279.620 93.515 280.000 93.585 ;
    END
  END m_axis_cq_tdata[52]
  PIN m_axis_cq_tdata[53]
    DIRECTION OUTPUT ;
    USE SIGNAL ;
    PORT
      LAYER metal3 ;
      RECT 279.620 93.895 280.000 93.965 ;
    END
  END m_axis_cq_tdata[53]
  PIN m_axis_cq_tdata[54]
    DIRECTION OUTPUT ;
    USE SIGNAL ;
    PORT
      LAYER metal3 ;
      RECT 279.620 94.275 280.000 94.345 ;
    END
  END m_axis_cq_tdata[54]
  PIN m_axis_cq_tdata[55]
    DIRECTION OUTPUT ;
    USE SIGNAL ;
    PORT
      LAYER metal3 ;
      RECT 279.620 94.655 280.000 94.725 ;
    END
  END m_axis_cq_tdata[55]
  PIN m_axis_cq_tdata[56]
    DIRECTION OUTPUT ;
    USE SIGNAL ;
    PORT
      LAYER metal3 ;
      RECT 279.620 95.035 280.000 95.105 ;
    END
  END m_axis_cq_tdata[56]
  PIN m_axis_cq_tdata[57]
    DIRECTION OUTPUT ;
    USE SIGNAL ;
    PORT
      LAYER metal3 ;
      RECT 279.620 95.415 280.000 95.485 ;
    END
  END m_axis_cq_tdata[57]
  PIN m_axis_cq_tdata[58]
    DIRECTION OUTPUT ;
    USE SIGNAL ;
    PORT
      LAYER metal3 ;
      RECT 279.620 95.795 280.000 95.865 ;
    END
  END m_axis_cq_tdata[58]
  PIN m_axis_cq_tdata[59]
    DIRECTION OUTPUT ;
    USE SIGNAL ;
    PORT
      LAYER metal3 ;
      RECT 279.620 96.175 280.000 96.245 ;
    END
  END m_axis_cq_tdata[59]
  PIN m_axis_cq_tdata[60]
    DIRECTION OUTPUT ;
    USE SIGNAL ;
    PORT
      LAYER metal3 ;
      RECT 279.620 96.555 280.000 96.625 ;
    END
  END m_axis_cq_tdata[60]
  PIN m_axis_cq_tdata[61]
    DIRECTION OUTPUT ;
    USE SIGNAL ;
    PORT
      LAYER metal3 ;
      RECT 279.620 96.935 280.000 97.005 ;
    END
  END m_axis_cq_tdata[61]
  PIN m_axis_cq_tdata[62]
    DIRECTION OUTPUT ;
    USE SIGNAL ;
    PORT
      LAYER metal3 ;
      RECT 279.620 97.315 280.000 97.385 ;
    END
  END m_axis_cq_tdata[62]
  PIN m_axis_cq_tdata[63]
    DIRECTION OUTPUT ;
    USE SIGNAL ;
    PORT
      LAYER metal3 ;
      RECT 279.620 97.695 280.000 97.765 ;
    END
  END m_axis_cq_tdata[63]
  PIN m_axis_cq_tdata[64]
    DIRECTION OUTPUT ;
    USE SIGNAL ;
    PORT
      LAYER metal3 ;
      RECT 279.620 98.075 280.000 98.145 ;
    END
  END m_axis_cq_tdata[64]
  PIN m_axis_cq_tdata[65]
    DIRECTION OUTPUT ;
    USE SIGNAL ;
    PORT
      LAYER metal3 ;
      RECT 279.620 98.455 280.000 98.525 ;
    END
  END m_axis_cq_tdata[65]
  PIN m_axis_cq_tdata[66]
    DIRECTION OUTPUT ;
    USE SIGNAL ;
    PORT
      LAYER metal3 ;
      RECT 279.620 98.835 280.000 98.905 ;
    END
  END m_axis_cq_tdata[66]
  PIN m_axis_cq_tdata[67]
    DIRECTION OUTPUT ;
    USE SIGNAL ;
    PORT
      LAYER metal3 ;
      RECT 279.620 99.215 280.000 99.285 ;
    END
  END m_axis_cq_tdata[67]
  PIN m_axis_cq_tdata[68]
    DIRECTION OUTPUT ;
    USE SIGNAL ;
    PORT
      LAYER metal3 ;
      RECT 279.620 99.595 280.000 99.665 ;
    END
  END m_axis_cq_tdata[68]
  PIN m_axis_cq_tdata[69]
    DIRECTION OUTPUT ;
    USE SIGNAL ;
    PORT
      LAYER metal3 ;
      RECT 279.620 99.975 280.000 100.045 ;
    END
  END m_axis_cq_tdata[69]
  PIN m_axis_cq_tdata[70]
    DIRECTION OUTPUT ;
    USE SIGNAL ;
    PORT
      LAYER metal3 ;
      RECT 279.620 100.355 280.000 100.425 ;
    END
  END m_axis_cq_tdata[70]
  PIN m_axis_cq_tdata[71]
    DIRECTION OUTPUT ;
    USE SIGNAL ;
    PORT
      LAYER metal3 ;
      RECT 279.620 100.735 280.000 100.805 ;
    END
  END m_axis_cq_tdata[71]
  PIN m_axis_cq_tdata[72]
    DIRECTION OUTPUT ;
    USE SIGNAL ;
    PORT
      LAYER metal3 ;
      RECT 279.620 101.115 280.000 101.185 ;
    END
  END m_axis_cq_tdata[72]
  PIN m_axis_cq_tdata[73]
    DIRECTION OUTPUT ;
    USE SIGNAL ;
    PORT
      LAYER metal3 ;
      RECT 279.620 101.495 280.000 101.565 ;
    END
  END m_axis_cq_tdata[73]
  PIN m_axis_cq_tdata[74]
    DIRECTION OUTPUT ;
    USE SIGNAL ;
    PORT
      LAYER metal3 ;
      RECT 279.620 101.875 280.000 101.945 ;
    END
  END m_axis_cq_tdata[74]
  PIN m_axis_cq_tdata[75]
    DIRECTION OUTPUT ;
    USE SIGNAL ;
    PORT
      LAYER metal3 ;
      RECT 279.620 102.255 280.000 102.325 ;
    END
  END m_axis_cq_tdata[75]
  PIN m_axis_cq_tdata[76]
    DIRECTION OUTPUT ;
    USE SIGNAL ;
    PORT
      LAYER metal3 ;
      RECT 279.620 102.635 280.000 102.705 ;
    END
  END m_axis_cq_tdata[76]
  PIN m_axis_cq_tdata[77]
    DIRECTION OUTPUT ;
    USE SIGNAL ;
    PORT
      LAYER metal3 ;
      RECT 279.620 103.015 280.000 103.085 ;
    END
  END m_axis_cq_tdata[77]
  PIN m_axis_cq_tdata[78]
    DIRECTION OUTPUT ;
    USE SIGNAL ;
    PORT
      LAYER metal3 ;
      RECT 279.620 103.395 280.000 103.465 ;
    END
  END m_axis_cq_tdata[78]
  PIN m_axis_cq_tdata[79]
    DIRECTION OUTPUT ;
    USE SIGNAL ;
    PORT
      LAYER metal3 ;
      RECT 279.620 103.775 280.000 103.845 ;
    END
  END m_axis_cq_tdata[79]
  PIN m_axis_cq_tdata[80]
    DIRECTION OUTPUT ;
    USE SIGNAL ;
    PORT
      LAYER metal3 ;
      RECT 279.620 104.155 280.000 104.225 ;
    END
  END m_axis_cq_tdata[80]
  PIN m_axis_cq_tdata[81]
    DIRECTION OUTPUT ;
    USE SIGNAL ;
    PORT
      LAYER metal3 ;
      RECT 279.620 104.535 280.000 104.605 ;
    END
  END m_axis_cq_tdata[81]
  PIN m_axis_cq_tdata[82]
    DIRECTION OUTPUT ;
    USE SIGNAL ;
    PORT
      LAYER metal3 ;
      RECT 279.620 104.915 280.000 104.985 ;
    END
  END m_axis_cq_tdata[82]
  PIN m_axis_cq_tdata[83]
    DIRECTION OUTPUT ;
    USE SIGNAL ;
    PORT
      LAYER metal3 ;
      RECT 279.620 105.295 280.000 105.365 ;
    END
  END m_axis_cq_tdata[83]
  PIN m_axis_cq_tdata[84]
    DIRECTION OUTPUT ;
    USE SIGNAL ;
    PORT
      LAYER metal3 ;
      RECT 279.620 105.675 280.000 105.745 ;
    END
  END m_axis_cq_tdata[84]
  PIN m_axis_cq_tdata[85]
    DIRECTION OUTPUT ;
    USE SIGNAL ;
    PORT
      LAYER metal3 ;
      RECT 279.620 106.055 280.000 106.125 ;
    END
  END m_axis_cq_tdata[85]
  PIN m_axis_cq_tdata[86]
    DIRECTION OUTPUT ;
    USE SIGNAL ;
    PORT
      LAYER metal3 ;
      RECT 279.620 106.435 280.000 106.505 ;
    END
  END m_axis_cq_tdata[86]
  PIN m_axis_cq_tdata[87]
    DIRECTION OUTPUT ;
    USE SIGNAL ;
    PORT
      LAYER metal3 ;
      RECT 279.620 106.815 280.000 106.885 ;
    END
  END m_axis_cq_tdata[87]
  PIN m_axis_cq_tdata[88]
    DIRECTION OUTPUT ;
    USE SIGNAL ;
    PORT
      LAYER metal3 ;
      RECT 279.620 107.195 280.000 107.265 ;
    END
  END m_axis_cq_tdata[88]
  PIN m_axis_cq_tdata[89]
    DIRECTION OUTPUT ;
    USE SIGNAL ;
    PORT
      LAYER metal3 ;
      RECT 279.620 107.575 280.000 107.645 ;
    END
  END m_axis_cq_tdata[89]
  PIN m_axis_cq_tdata[90]
    DIRECTION OUTPUT ;
    USE SIGNAL ;
    PORT
      LAYER metal3 ;
      RECT 279.620 107.955 280.000 108.025 ;
    END
  END m_axis_cq_tdata[90]
  PIN m_axis_cq_tdata[91]
    DIRECTION OUTPUT ;
    USE SIGNAL ;
    PORT
      LAYER metal3 ;
      RECT 279.620 108.335 280.000 108.405 ;
    END
  END m_axis_cq_tdata[91]
  PIN m_axis_cq_tdata[92]
    DIRECTION OUTPUT ;
    USE SIGNAL ;
    PORT
      LAYER metal3 ;
      RECT 279.620 108.715 280.000 108.785 ;
    END
  END m_axis_cq_tdata[92]
  PIN m_axis_cq_tdata[93]
    DIRECTION OUTPUT ;
    USE SIGNAL ;
    PORT
      LAYER metal3 ;
      RECT 279.620 109.095 280.000 109.165 ;
    END
  END m_axis_cq_tdata[93]
  PIN m_axis_cq_tdata[94]
    DIRECTION OUTPUT ;
    USE SIGNAL ;
    PORT
      LAYER metal3 ;
      RECT 279.620 109.475 280.000 109.545 ;
    END
  END m_axis_cq_tdata[94]
  PIN m_axis_cq_tdata[95]
    DIRECTION OUTPUT ;
    USE SIGNAL ;
    PORT
      LAYER metal3 ;
      RECT 279.620 109.855 280.000 109.925 ;
    END
  END m_axis_cq_tdata[95]
  PIN m_axis_cq_tdata[96]
    DIRECTION OUTPUT ;
    USE SIGNAL ;
    PORT
      LAYER metal3 ;
      RECT 279.620 110.235 280.000 110.305 ;
    END
  END m_axis_cq_tdata[96]
  PIN m_axis_cq_tdata[97]
    DIRECTION OUTPUT ;
    USE SIGNAL ;
    PORT
      LAYER metal3 ;
      RECT 279.620 110.615 280.000 110.685 ;
    END
  END m_axis_cq_tdata[97]
  PIN m_axis_cq_tdata[98]
    DIRECTION OUTPUT ;
    USE SIGNAL ;
    PORT
      LAYER metal3 ;
      RECT 279.620 110.995 280.000 111.065 ;
    END
  END m_axis_cq_tdata[98]
  PIN m_axis_cq_tdata[99]
    DIRECTION OUTPUT ;
    USE SIGNAL ;
    PORT
      LAYER metal3 ;
      RECT 279.620 111.375 280.000 111.445 ;
    END
  END m_axis_cq_tdata[99]
  PIN m_axis_cq_tdata[100]
    DIRECTION OUTPUT ;
    USE SIGNAL ;
    PORT
      LAYER metal3 ;
      RECT 279.620 111.755 280.000 111.825 ;
    END
  END m_axis_cq_tdata[100]
  PIN m_axis_cq_tdata[101]
    DIRECTION OUTPUT ;
    USE SIGNAL ;
    PORT
      LAYER metal3 ;
      RECT 279.620 112.135 280.000 112.205 ;
    END
  END m_axis_cq_tdata[101]
  PIN m_axis_cq_tdata[102]
    DIRECTION OUTPUT ;
    USE SIGNAL ;
    PORT
      LAYER metal3 ;
      RECT 279.620 112.515 280.000 112.585 ;
    END
  END m_axis_cq_tdata[102]
  PIN m_axis_cq_tdata[103]
    DIRECTION OUTPUT ;
    USE SIGNAL ;
    PORT
      LAYER metal3 ;
      RECT 279.620 112.895 280.000 112.965 ;
    END
  END m_axis_cq_tdata[103]
  PIN m_axis_cq_tdata[104]
    DIRECTION OUTPUT ;
    USE SIGNAL ;
    PORT
      LAYER metal3 ;
      RECT 279.620 113.275 280.000 113.345 ;
    END
  END m_axis_cq_tdata[104]
  PIN m_axis_cq_tdata[105]
    DIRECTION OUTPUT ;
    USE SIGNAL ;
    PORT
      LAYER metal3 ;
      RECT 279.620 113.655 280.000 113.725 ;
    END
  END m_axis_cq_tdata[105]
  PIN m_axis_cq_tdata[106]
    DIRECTION OUTPUT ;
    USE SIGNAL ;
    PORT
      LAYER metal3 ;
      RECT 279.620 114.035 280.000 114.105 ;
    END
  END m_axis_cq_tdata[106]
  PIN m_axis_cq_tdata[107]
    DIRECTION OUTPUT ;
    USE SIGNAL ;
    PORT
      LAYER metal3 ;
      RECT 279.620 114.415 280.000 114.485 ;
    END
  END m_axis_cq_tdata[107]
  PIN m_axis_cq_tdata[108]
    DIRECTION OUTPUT ;
    USE SIGNAL ;
    PORT
      LAYER metal3 ;
      RECT 279.620 114.795 280.000 114.865 ;
    END
  END m_axis_cq_tdata[108]
  PIN m_axis_cq_tdata[109]
    DIRECTION OUTPUT ;
    USE SIGNAL ;
    PORT
      LAYER metal3 ;
      RECT 279.620 115.175 280.000 115.245 ;
    END
  END m_axis_cq_tdata[109]
  PIN m_axis_cq_tdata[110]
    DIRECTION OUTPUT ;
    USE SIGNAL ;
    PORT
      LAYER metal3 ;
      RECT 279.620 115.555 280.000 115.625 ;
    END
  END m_axis_cq_tdata[110]
  PIN m_axis_cq_tdata[111]
    DIRECTION OUTPUT ;
    USE SIGNAL ;
    PORT
      LAYER metal3 ;
      RECT 279.620 115.935 280.000 116.005 ;
    END
  END m_axis_cq_tdata[111]
  PIN m_axis_cq_tdata[112]
    DIRECTION OUTPUT ;
    USE SIGNAL ;
    PORT
      LAYER metal3 ;
      RECT 279.620 116.315 280.000 116.385 ;
    END
  END m_axis_cq_tdata[112]
  PIN m_axis_cq_tdata[113]
    DIRECTION OUTPUT ;
    USE SIGNAL ;
    PORT
      LAYER metal3 ;
      RECT 279.620 116.695 280.000 116.765 ;
    END
  END m_axis_cq_tdata[113]
  PIN m_axis_cq_tdata[114]
    DIRECTION OUTPUT ;
    USE SIGNAL ;
    PORT
      LAYER metal3 ;
      RECT 279.620 117.075 280.000 117.145 ;
    END
  END m_axis_cq_tdata[114]
  PIN m_axis_cq_tdata[115]
    DIRECTION OUTPUT ;
    USE SIGNAL ;
    PORT
      LAYER metal3 ;
      RECT 279.620 117.455 280.000 117.525 ;
    END
  END m_axis_cq_tdata[115]
  PIN m_axis_cq_tdata[116]
    DIRECTION OUTPUT ;
    USE SIGNAL ;
    PORT
      LAYER metal3 ;
      RECT 279.620 117.835 280.000 117.905 ;
    END
  END m_axis_cq_tdata[116]
  PIN m_axis_cq_tdata[117]
    DIRECTION OUTPUT ;
    USE SIGNAL ;
    PORT
      LAYER metal3 ;
      RECT 279.620 118.215 280.000 118.285 ;
    END
  END m_axis_cq_tdata[117]
  PIN m_axis_cq_tdata[118]
    DIRECTION OUTPUT ;
    USE SIGNAL ;
    PORT
      LAYER metal3 ;
      RECT 279.620 118.595 280.000 118.665 ;
    END
  END m_axis_cq_tdata[118]
  PIN m_axis_cq_tdata[119]
    DIRECTION OUTPUT ;
    USE SIGNAL ;
    PORT
      LAYER metal3 ;
      RECT 279.620 118.975 280.000 119.045 ;
    END
  END m_axis_cq_tdata[119]
  PIN m_axis_cq_tdata[120]
    DIRECTION OUTPUT ;
    USE SIGNAL ;
    PORT
      LAYER metal3 ;
      RECT 279.620 119.355 280.000 119.425 ;
    END
  END m_axis_cq_tdata[120]
  PIN m_axis_cq_tdata[121]
    DIRECTION OUTPUT ;
    USE SIGNAL ;
    PORT
      LAYER metal3 ;
      RECT 279.620 119.735 280.000 119.805 ;
    END
  END m_axis_cq_tdata[121]
  PIN m_axis_cq_tdata[122]
    DIRECTION OUTPUT ;
    USE SIGNAL ;
    PORT
      LAYER metal3 ;
      RECT 279.620 120.115 280.000 120.185 ;
    END
  END m_axis_cq_tdata[122]
  PIN m_axis_cq_tdata[123]
    DIRECTION OUTPUT ;
    USE SIGNAL ;
    PORT
      LAYER metal3 ;
      RECT 279.620 120.495 280.000 120.565 ;
    END
  END m_axis_cq_tdata[123]
  PIN m_axis_cq_tdata[124]
    DIRECTION OUTPUT ;
    USE SIGNAL ;
    PORT
      LAYER metal3 ;
      RECT 279.620 120.875 280.000 120.945 ;
    END
  END m_axis_cq_tdata[124]
  PIN m_axis_cq_tdata[125]
    DIRECTION OUTPUT ;
    USE SIGNAL ;
    PORT
      LAYER metal3 ;
      RECT 279.620 121.255 280.000 121.325 ;
    END
  END m_axis_cq_tdata[125]
  PIN m_axis_cq_tdata[126]
    DIRECTION OUTPUT ;
    USE SIGNAL ;
    PORT
      LAYER metal3 ;
      RECT 279.620 121.635 280.000 121.705 ;
    END
  END m_axis_cq_tdata[126]
  PIN m_axis_cq_tdata[127]
    DIRECTION OUTPUT ;
    USE SIGNAL ;
    PORT
      LAYER metal3 ;
      RECT 279.620 122.015 280.000 122.085 ;
    END
  END m_axis_cq_tdata[127]
  PIN m_axis_cq_tkeep[0]
    DIRECTION OUTPUT ;
    USE SIGNAL ;
    PORT
      LAYER metal3 ;
      RECT 279.620 122.395 280.000 122.465 ;
    END
  END m_axis_cq_tkeep[0]
  PIN m_axis_cq_tkeep[1]
    DIRECTION OUTPUT ;
    USE SIGNAL ;
    PORT
      LAYER metal3 ;
      RECT 279.620 122.775 280.000 122.845 ;
    END
  END m_axis_cq_tkeep[1]
  PIN m_axis_cq_tkeep[2]
    DIRECTION OUTPUT ;
    USE SIGNAL ;
    PORT
      LAYER metal3 ;
      RECT 279.620 123.155 280.000 123.225 ;
    END
  END m_axis_cq_tkeep[2]
  PIN m_axis_cq_tkeep[3]
    DIRECTION OUTPUT ;
    USE SIGNAL ;
    PORT
      LAYER metal3 ;
      RECT 279.620 123.535 280.000 123.605 ;
    END
  END m_axis_cq_tkeep[3]
  PIN m_axis_cq_tlast
    DIRECTION OUTPUT ;
    USE SIGNAL ;
    PORT
      LAYER metal3 ;
      RECT 279.620 123.915 280.000 123.985 ;
    END
  END m_axis_cq_tlast
  PIN m_axis_cq_tuser[0]
    DIRECTION OUTPUT ;
    USE SIGNAL ;
    PORT
      LAYER metal3 ;
      RECT 279.620 124.295 280.000 124.365 ;
    END
  END m_axis_cq_tuser[0]
  PIN m_axis_cq_tuser[1]
    DIRECTION OUTPUT ;
    USE SIGNAL ;
    PORT
      LAYER metal3 ;
      RECT 279.620 124.675 280.000 124.745 ;
    END
  END m_axis_cq_tuser[1]
  PIN m_axis_cq_tuser[2]
    DIRECTION OUTPUT ;
    USE SIGNAL ;
    PORT
      LAYER metal3 ;
      RECT 279.620 125.055 280.000 125.125 ;
    END
  END m_axis_cq_tuser[2]
  PIN m_axis_cq_tuser[3]
    DIRECTION OUTPUT ;
    USE SIGNAL ;
    PORT
      LAYER metal3 ;
      RECT 279.620 125.435 280.000 125.505 ;
    END
  END m_axis_cq_tuser[3]
  PIN m_axis_cq_tuser[4]
    DIRECTION OUTPUT ;
    USE SIGNAL ;
    PORT
      LAYER metal3 ;
      RECT 279.620 125.815 280.000 125.885 ;
    END
  END m_axis_cq_tuser[4]
  PIN m_axis_cq_tuser[5]
    DIRECTION OUTPUT ;
    USE SIGNAL ;
    PORT
      LAYER metal3 ;
      RECT 279.620 126.195 280.000 126.265 ;
    END
  END m_axis_cq_tuser[5]
  PIN m_axis_cq_tuser[6]
    DIRECTION OUTPUT ;
    USE SIGNAL ;
    PORT
      LAYER metal3 ;
      RECT 279.620 126.575 280.000 126.645 ;
    END
  END m_axis_cq_tuser[6]
  PIN m_axis_cq_tuser[7]
    DIRECTION OUTPUT ;
    USE SIGNAL ;
    PORT
      LAYER metal3 ;
      RECT 279.620 126.955 280.000 127.025 ;
    END
  END m_axis_cq_tuser[7]
  PIN m_axis_cq_tuser[8]
    DIRECTION OUTPUT ;
    USE SIGNAL ;
    PORT
      LAYER metal3 ;
      RECT 279.620 127.335 280.000 127.405 ;
    END
  END m_axis_cq_tuser[8]
  PIN m_axis_cq_tuser[9]
    DIRECTION OUTPUT ;
    USE SIGNAL ;
    PORT
      LAYER metal3 ;
      RECT 279.620 127.715 280.000 127.785 ;
    END
  END m_axis_cq_tuser[9]
  PIN m_axis_cq_tuser[10]
    DIRECTION OUTPUT ;
    USE SIGNAL ;
    PORT
      LAYER metal3 ;
      RECT 279.620 128.095 280.000 128.165 ;
    END
  END m_axis_cq_tuser[10]
  PIN m_axis_cq_tuser[11]
    DIRECTION OUTPUT ;
    USE SIGNAL ;
    PORT
      LAYER metal3 ;
      RECT 279.620 128.475 280.000 128.545 ;
    END
  END m_axis_cq_tuser[11]
  PIN m_axis_cq_tuser[12]
    DIRECTION OUTPUT ;
    USE SIGNAL ;
    PORT
      LAYER metal3 ;
      RECT 279.620 128.855 280.000 128.925 ;
    END
  END m_axis_cq_tuser[12]
  PIN m_axis_cq_tuser[13]
    DIRECTION OUTPUT ;
    USE SIGNAL ;
    PORT
      LAYER metal3 ;
      RECT 279.620 129.235 280.000 129.305 ;
    END
  END m_axis_cq_tuser[13]
  PIN m_axis_cq_tuser[14]
    DIRECTION OUTPUT ;
    USE SIGNAL ;
    PORT
      LAYER metal3 ;
      RECT 279.620 129.615 280.000 129.685 ;
    END
  END m_axis_cq_tuser[14]
  PIN m_axis_cq_tuser[15]
    DIRECTION OUTPUT ;
    USE SIGNAL ;
    PORT
      LAYER metal3 ;
      RECT 279.620 129.995 280.000 130.065 ;
    END
  END m_axis_cq_tuser[15]
  PIN m_axis_cq_tuser[16]
    DIRECTION OUTPUT ;
    USE SIGNAL ;
    PORT
      LAYER metal3 ;
      RECT 279.620 130.375 280.000 130.445 ;
    END
  END m_axis_cq_tuser[16]
  PIN m_axis_cq_tuser[17]
    DIRECTION OUTPUT ;
    USE SIGNAL ;
    PORT
      LAYER metal3 ;
      RECT 279.620 130.755 280.000 130.825 ;
    END
  END m_axis_cq_tuser[17]
  PIN m_axis_cq_tuser[18]
    DIRECTION OUTPUT ;
    USE SIGNAL ;
    PORT
      LAYER metal3 ;
      RECT 279.620 131.135 280.000 131.205 ;
    END
  END m_axis_cq_tuser[18]
  PIN m_axis_cq_tuser[19]
    DIRECTION OUTPUT ;
    USE SIGNAL ;
    PORT
      LAYER metal3 ;
      RECT 279.620 131.515 280.000 131.585 ;
    END
  END m_axis_cq_tuser[19]
  PIN m_axis_cq_tuser[20]
    DIRECTION OUTPUT ;
    USE SIGNAL ;
    PORT
      LAYER metal3 ;
      RECT 279.620 131.895 280.000 131.965 ;
    END
  END m_axis_cq_tuser[20]
  PIN m_axis_cq_tuser[21]
    DIRECTION OUTPUT ;
    USE SIGNAL ;
    PORT
      LAYER metal3 ;
      RECT 279.620 132.275 280.000 132.345 ;
    END
  END m_axis_cq_tuser[21]
  PIN m_axis_cq_tuser[22]
    DIRECTION OUTPUT ;
    USE SIGNAL ;
    PORT
      LAYER metal3 ;
      RECT 279.620 132.655 280.000 132.725 ;
    END
  END m_axis_cq_tuser[22]
  PIN m_axis_cq_tuser[23]
    DIRECTION OUTPUT ;
    USE SIGNAL ;
    PORT
      LAYER metal3 ;
      RECT 279.620 133.035 280.000 133.105 ;
    END
  END m_axis_cq_tuser[23]
  PIN m_axis_cq_tuser[24]
    DIRECTION OUTPUT ;
    USE SIGNAL ;
    PORT
      LAYER metal3 ;
      RECT 279.620 133.415 280.000 133.485 ;
    END
  END m_axis_cq_tuser[24]
  PIN m_axis_cq_tuser[25]
    DIRECTION OUTPUT ;
    USE SIGNAL ;
    PORT
      LAYER metal3 ;
      RECT 279.620 133.795 280.000 133.865 ;
    END
  END m_axis_cq_tuser[25]
  PIN m_axis_cq_tuser[26]
    DIRECTION OUTPUT ;
    USE SIGNAL ;
    PORT
      LAYER metal3 ;
      RECT 279.620 134.175 280.000 134.245 ;
    END
  END m_axis_cq_tuser[26]
  PIN m_axis_cq_tuser[27]
    DIRECTION OUTPUT ;
    USE SIGNAL ;
    PORT
      LAYER metal3 ;
      RECT 279.620 134.555 280.000 134.625 ;
    END
  END m_axis_cq_tuser[27]
  PIN m_axis_cq_tuser[28]
    DIRECTION OUTPUT ;
    USE SIGNAL ;
    PORT
      LAYER metal3 ;
      RECT 279.620 134.935 280.000 135.005 ;
    END
  END m_axis_cq_tuser[28]
  PIN m_axis_cq_tuser[29]
    DIRECTION OUTPUT ;
    USE SIGNAL ;
    PORT
      LAYER metal3 ;
      RECT 279.620 135.315 280.000 135.385 ;
    END
  END m_axis_cq_tuser[29]
  PIN m_axis_cq_tuser[30]
    DIRECTION OUTPUT ;
    USE SIGNAL ;
    PORT
      LAYER metal3 ;
      RECT 279.620 135.695 280.000 135.765 ;
    END
  END m_axis_cq_tuser[30]
  PIN m_axis_cq_tuser[31]
    DIRECTION OUTPUT ;
    USE SIGNAL ;
    PORT
      LAYER metal3 ;
      RECT 279.620 136.075 280.000 136.145 ;
    END
  END m_axis_cq_tuser[31]
  PIN m_axis_cq_tuser[32]
    DIRECTION OUTPUT ;
    USE SIGNAL ;
    PORT
      LAYER metal3 ;
      RECT 279.620 136.455 280.000 136.525 ;
    END
  END m_axis_cq_tuser[32]
  PIN m_axis_cq_tuser[33]
    DIRECTION OUTPUT ;
    USE SIGNAL ;
    PORT
      LAYER metal3 ;
      RECT 279.620 136.835 280.000 136.905 ;
    END
  END m_axis_cq_tuser[33]
  PIN m_axis_cq_tuser[34]
    DIRECTION OUTPUT ;
    USE SIGNAL ;
    PORT
      LAYER metal3 ;
      RECT 279.620 137.215 280.000 137.285 ;
    END
  END m_axis_cq_tuser[34]
  PIN m_axis_cq_tuser[35]
    DIRECTION OUTPUT ;
    USE SIGNAL ;
    PORT
      LAYER metal3 ;
      RECT 279.620 137.595 280.000 137.665 ;
    END
  END m_axis_cq_tuser[35]
  PIN m_axis_cq_tuser[36]
    DIRECTION OUTPUT ;
    USE SIGNAL ;
    PORT
      LAYER metal3 ;
      RECT 279.620 137.975 280.000 138.045 ;
    END
  END m_axis_cq_tuser[36]
  PIN m_axis_cq_tuser[37]
    DIRECTION OUTPUT ;
    USE SIGNAL ;
    PORT
      LAYER metal3 ;
      RECT 279.620 138.355 280.000 138.425 ;
    END
  END m_axis_cq_tuser[37]
  PIN m_axis_cq_tuser[38]
    DIRECTION OUTPUT ;
    USE SIGNAL ;
    PORT
      LAYER metal3 ;
      RECT 279.620 138.735 280.000 138.805 ;
    END
  END m_axis_cq_tuser[38]
  PIN m_axis_cq_tuser[39]
    DIRECTION OUTPUT ;
    USE SIGNAL ;
    PORT
      LAYER metal3 ;
      RECT 279.620 139.115 280.000 139.185 ;
    END
  END m_axis_cq_tuser[39]
  PIN m_axis_cq_tuser[40]
    DIRECTION OUTPUT ;
    USE SIGNAL ;
    PORT
      LAYER metal3 ;
      RECT 279.620 139.495 280.000 139.565 ;
    END
  END m_axis_cq_tuser[40]
  PIN m_axis_cq_tuser[41]
    DIRECTION OUTPUT ;
    USE SIGNAL ;
    PORT
      LAYER metal3 ;
      RECT 279.620 139.875 280.000 139.945 ;
    END
  END m_axis_cq_tuser[41]
  PIN m_axis_cq_tuser[42]
    DIRECTION OUTPUT ;
    USE SIGNAL ;
    PORT
      LAYER metal3 ;
      RECT 279.620 140.255 280.000 140.325 ;
    END
  END m_axis_cq_tuser[42]
  PIN m_axis_cq_tuser[43]
    DIRECTION OUTPUT ;
    USE SIGNAL ;
    PORT
      LAYER metal3 ;
      RECT 279.620 140.635 280.000 140.705 ;
    END
  END m_axis_cq_tuser[43]
  PIN m_axis_cq_tuser[44]
    DIRECTION OUTPUT ;
    USE SIGNAL ;
    PORT
      LAYER metal3 ;
      RECT 279.620 141.015 280.000 141.085 ;
    END
  END m_axis_cq_tuser[44]
  PIN m_axis_cq_tuser[45]
    DIRECTION OUTPUT ;
    USE SIGNAL ;
    PORT
      LAYER metal3 ;
      RECT 279.620 141.395 280.000 141.465 ;
    END
  END m_axis_cq_tuser[45]
  PIN m_axis_cq_tuser[46]
    DIRECTION OUTPUT ;
    USE SIGNAL ;
    PORT
      LAYER metal3 ;
      RECT 279.620 141.775 280.000 141.845 ;
    END
  END m_axis_cq_tuser[46]
  PIN m_axis_cq_tuser[47]
    DIRECTION OUTPUT ;
    USE SIGNAL ;
    PORT
      LAYER metal3 ;
      RECT 279.620 142.155 280.000 142.225 ;
    END
  END m_axis_cq_tuser[47]
  PIN m_axis_cq_tuser[48]
    DIRECTION OUTPUT ;
    USE SIGNAL ;
    PORT
      LAYER metal3 ;
      RECT 279.620 142.535 280.000 142.605 ;
    END
  END m_axis_cq_tuser[48]
  PIN m_axis_cq_tuser[49]
    DIRECTION OUTPUT ;
    USE SIGNAL ;
    PORT
      LAYER metal3 ;
      RECT 279.620 142.915 280.000 142.985 ;
    END
  END m_axis_cq_tuser[49]
  PIN m_axis_cq_tuser[50]
    DIRECTION OUTPUT ;
    USE SIGNAL ;
    PORT
      LAYER metal3 ;
      RECT 279.620 143.295 280.000 143.365 ;
    END
  END m_axis_cq_tuser[50]
  PIN m_axis_cq_tuser[51]
    DIRECTION OUTPUT ;
    USE SIGNAL ;
    PORT
      LAYER metal3 ;
      RECT 279.620 143.675 280.000 143.745 ;
    END
  END m_axis_cq_tuser[51]
  PIN m_axis_cq_tuser[52]
    DIRECTION OUTPUT ;
    USE SIGNAL ;
    PORT
      LAYER metal3 ;
      RECT 279.620 144.055 280.000 144.125 ;
    END
  END m_axis_cq_tuser[52]
  PIN m_axis_cq_tuser[53]
    DIRECTION OUTPUT ;
    USE SIGNAL ;
    PORT
      LAYER metal3 ;
      RECT 279.620 144.435 280.000 144.505 ;
    END
  END m_axis_cq_tuser[53]
  PIN m_axis_cq_tuser[54]
    DIRECTION OUTPUT ;
    USE SIGNAL ;
    PORT
      LAYER metal3 ;
      RECT 279.620 144.815 280.000 144.885 ;
    END
  END m_axis_cq_tuser[54]
  PIN m_axis_cq_tuser[55]
    DIRECTION OUTPUT ;
    USE SIGNAL ;
    PORT
      LAYER metal3 ;
      RECT 279.620 145.195 280.000 145.265 ;
    END
  END m_axis_cq_tuser[55]
  PIN m_axis_cq_tuser[56]
    DIRECTION OUTPUT ;
    USE SIGNAL ;
    PORT
      LAYER metal3 ;
      RECT 279.620 145.575 280.000 145.645 ;
    END
  END m_axis_cq_tuser[56]
  PIN m_axis_cq_tuser[57]
    DIRECTION OUTPUT ;
    USE SIGNAL ;
    PORT
      LAYER metal3 ;
      RECT 279.620 145.955 280.000 146.025 ;
    END
  END m_axis_cq_tuser[57]
  PIN m_axis_cq_tuser[58]
    DIRECTION OUTPUT ;
    USE SIGNAL ;
    PORT
      LAYER metal3 ;
      RECT 279.620 146.335 280.000 146.405 ;
    END
  END m_axis_cq_tuser[58]
  PIN m_axis_cq_tuser[59]
    DIRECTION OUTPUT ;
    USE SIGNAL ;
    PORT
      LAYER metal3 ;
      RECT 279.620 146.715 280.000 146.785 ;
    END
  END m_axis_cq_tuser[59]
  PIN m_axis_cq_tuser[60]
    DIRECTION OUTPUT ;
    USE SIGNAL ;
    PORT
      LAYER metal3 ;
      RECT 279.620 147.095 280.000 147.165 ;
    END
  END m_axis_cq_tuser[60]
  PIN m_axis_cq_tuser[61]
    DIRECTION OUTPUT ;
    USE SIGNAL ;
    PORT
      LAYER metal3 ;
      RECT 279.620 147.475 280.000 147.545 ;
    END
  END m_axis_cq_tuser[61]
  PIN m_axis_cq_tuser[62]
    DIRECTION OUTPUT ;
    USE SIGNAL ;
    PORT
      LAYER metal3 ;
      RECT 279.620 147.855 280.000 147.925 ;
    END
  END m_axis_cq_tuser[62]
  PIN m_axis_cq_tuser[63]
    DIRECTION OUTPUT ;
    USE SIGNAL ;
    PORT
      LAYER metal3 ;
      RECT 279.620 148.235 280.000 148.305 ;
    END
  END m_axis_cq_tuser[63]
  PIN m_axis_cq_tuser[64]
    DIRECTION OUTPUT ;
    USE SIGNAL ;
    PORT
      LAYER metal3 ;
      RECT 279.620 148.615 280.000 148.685 ;
    END
  END m_axis_cq_tuser[64]
  PIN m_axis_cq_tuser[65]
    DIRECTION OUTPUT ;
    USE SIGNAL ;
    PORT
      LAYER metal3 ;
      RECT 279.620 148.995 280.000 149.065 ;
    END
  END m_axis_cq_tuser[65]
  PIN m_axis_cq_tuser[66]
    DIRECTION OUTPUT ;
    USE SIGNAL ;
    PORT
      LAYER metal3 ;
      RECT 279.620 149.375 280.000 149.445 ;
    END
  END m_axis_cq_tuser[66]
  PIN m_axis_cq_tuser[67]
    DIRECTION OUTPUT ;
    USE SIGNAL ;
    PORT
      LAYER metal3 ;
      RECT 279.620 149.755 280.000 149.825 ;
    END
  END m_axis_cq_tuser[67]
  PIN m_axis_cq_tuser[68]
    DIRECTION OUTPUT ;
    USE SIGNAL ;
    PORT
      LAYER metal3 ;
      RECT 279.620 150.135 280.000 150.205 ;
    END
  END m_axis_cq_tuser[68]
  PIN m_axis_cq_tuser[69]
    DIRECTION OUTPUT ;
    USE SIGNAL ;
    PORT
      LAYER metal3 ;
      RECT 279.620 150.515 280.000 150.585 ;
    END
  END m_axis_cq_tuser[69]
  PIN m_axis_cq_tuser[70]
    DIRECTION OUTPUT ;
    USE SIGNAL ;
    PORT
      LAYER metal3 ;
      RECT 279.620 150.895 280.000 150.965 ;
    END
  END m_axis_cq_tuser[70]
  PIN m_axis_cq_tuser[71]
    DIRECTION OUTPUT ;
    USE SIGNAL ;
    PORT
      LAYER metal3 ;
      RECT 279.620 151.275 280.000 151.345 ;
    END
  END m_axis_cq_tuser[71]
  PIN m_axis_cq_tuser[72]
    DIRECTION OUTPUT ;
    USE SIGNAL ;
    PORT
      LAYER metal3 ;
      RECT 279.620 151.655 280.000 151.725 ;
    END
  END m_axis_cq_tuser[72]
  PIN m_axis_cq_tuser[73]
    DIRECTION OUTPUT ;
    USE SIGNAL ;
    PORT
      LAYER metal3 ;
      RECT 279.620 152.035 280.000 152.105 ;
    END
  END m_axis_cq_tuser[73]
  PIN m_axis_cq_tuser[74]
    DIRECTION OUTPUT ;
    USE SIGNAL ;
    PORT
      LAYER metal3 ;
      RECT 279.620 152.415 280.000 152.485 ;
    END
  END m_axis_cq_tuser[74]
  PIN m_axis_cq_tuser[75]
    DIRECTION OUTPUT ;
    USE SIGNAL ;
    PORT
      LAYER metal3 ;
      RECT 279.620 152.795 280.000 152.865 ;
    END
  END m_axis_cq_tuser[75]
  PIN m_axis_cq_tuser[76]
    DIRECTION OUTPUT ;
    USE SIGNAL ;
    PORT
      LAYER metal3 ;
      RECT 279.620 153.175 280.000 153.245 ;
    END
  END m_axis_cq_tuser[76]
  PIN m_axis_cq_tuser[77]
    DIRECTION OUTPUT ;
    USE SIGNAL ;
    PORT
      LAYER metal3 ;
      RECT 279.620 153.555 280.000 153.625 ;
    END
  END m_axis_cq_tuser[77]
  PIN m_axis_cq_tuser[78]
    DIRECTION OUTPUT ;
    USE SIGNAL ;
    PORT
      LAYER metal3 ;
      RECT 279.620 153.935 280.000 154.005 ;
    END
  END m_axis_cq_tuser[78]
  PIN m_axis_cq_tuser[79]
    DIRECTION OUTPUT ;
    USE SIGNAL ;
    PORT
      LAYER metal3 ;
      RECT 279.620 154.315 280.000 154.385 ;
    END
  END m_axis_cq_tuser[79]
  PIN m_axis_cq_tuser[80]
    DIRECTION OUTPUT ;
    USE SIGNAL ;
    PORT
      LAYER metal3 ;
      RECT 279.620 154.695 280.000 154.765 ;
    END
  END m_axis_cq_tuser[80]
  PIN m_axis_cq_tuser[81]
    DIRECTION OUTPUT ;
    USE SIGNAL ;
    PORT
      LAYER metal3 ;
      RECT 279.620 155.075 280.000 155.145 ;
    END
  END m_axis_cq_tuser[81]
  PIN m_axis_cq_tuser[82]
    DIRECTION OUTPUT ;
    USE SIGNAL ;
    PORT
      LAYER metal3 ;
      RECT 279.620 155.455 280.000 155.525 ;
    END
  END m_axis_cq_tuser[82]
  PIN m_axis_cq_tuser[83]
    DIRECTION OUTPUT ;
    USE SIGNAL ;
    PORT
      LAYER metal3 ;
      RECT 279.620 155.835 280.000 155.905 ;
    END
  END m_axis_cq_tuser[83]
  PIN m_axis_cq_tuser[84]
    DIRECTION OUTPUT ;
    USE SIGNAL ;
    PORT
      LAYER metal3 ;
      RECT 279.620 156.215 280.000 156.285 ;
    END
  END m_axis_cq_tuser[84]
  PIN m_axis_cq_tuser[85]
    DIRECTION OUTPUT ;
    USE SIGNAL ;
    PORT
      LAYER metal3 ;
      RECT 279.620 156.595 280.000 156.665 ;
    END
  END m_axis_cq_tuser[85]
  PIN m_axis_cq_tuser[86]
    DIRECTION OUTPUT ;
    USE SIGNAL ;
    PORT
      LAYER metal3 ;
      RECT 279.620 156.975 280.000 157.045 ;
    END
  END m_axis_cq_tuser[86]
  PIN m_axis_cq_tuser[87]
    DIRECTION OUTPUT ;
    USE SIGNAL ;
    PORT
      LAYER metal3 ;
      RECT 279.620 157.355 280.000 157.425 ;
    END
  END m_axis_cq_tuser[87]
  PIN m_axis_cq_tvalid
    DIRECTION OUTPUT ;
    USE SIGNAL ;
    PORT
      LAYER metal3 ;
      RECT 279.620 157.735 280.000 157.805 ;
    END
  END m_axis_cq_tvalid
  PIN m_axis_rc_tdata[0]
    DIRECTION OUTPUT ;
    USE SIGNAL ;
    PORT
      LAYER metal3 ;
      RECT 279.620 158.115 280.000 158.185 ;
    END
  END m_axis_rc_tdata[0]
  PIN m_axis_rc_tdata[1]
    DIRECTION OUTPUT ;
    USE SIGNAL ;
    PORT
      LAYER metal3 ;
      RECT 279.620 158.495 280.000 158.565 ;
    END
  END m_axis_rc_tdata[1]
  PIN m_axis_rc_tdata[2]
    DIRECTION OUTPUT ;
    USE SIGNAL ;
    PORT
      LAYER metal3 ;
      RECT 279.620 158.875 280.000 158.945 ;
    END
  END m_axis_rc_tdata[2]
  PIN m_axis_rc_tdata[3]
    DIRECTION OUTPUT ;
    USE SIGNAL ;
    PORT
      LAYER metal3 ;
      RECT 279.620 159.255 280.000 159.325 ;
    END
  END m_axis_rc_tdata[3]
  PIN m_axis_rc_tdata[4]
    DIRECTION OUTPUT ;
    USE SIGNAL ;
    PORT
      LAYER metal3 ;
      RECT 279.620 159.635 280.000 159.705 ;
    END
  END m_axis_rc_tdata[4]
  PIN m_axis_rc_tdata[5]
    DIRECTION OUTPUT ;
    USE SIGNAL ;
    PORT
      LAYER metal3 ;
      RECT 279.620 160.015 280.000 160.085 ;
    END
  END m_axis_rc_tdata[5]
  PIN m_axis_rc_tdata[6]
    DIRECTION OUTPUT ;
    USE SIGNAL ;
    PORT
      LAYER metal3 ;
      RECT 279.620 160.395 280.000 160.465 ;
    END
  END m_axis_rc_tdata[6]
  PIN m_axis_rc_tdata[7]
    DIRECTION OUTPUT ;
    USE SIGNAL ;
    PORT
      LAYER metal3 ;
      RECT 279.620 160.775 280.000 160.845 ;
    END
  END m_axis_rc_tdata[7]
  PIN m_axis_rc_tdata[8]
    DIRECTION OUTPUT ;
    USE SIGNAL ;
    PORT
      LAYER metal3 ;
      RECT 279.620 161.155 280.000 161.225 ;
    END
  END m_axis_rc_tdata[8]
  PIN m_axis_rc_tdata[9]
    DIRECTION OUTPUT ;
    USE SIGNAL ;
    PORT
      LAYER metal3 ;
      RECT 279.620 161.535 280.000 161.605 ;
    END
  END m_axis_rc_tdata[9]
  PIN m_axis_rc_tdata[10]
    DIRECTION OUTPUT ;
    USE SIGNAL ;
    PORT
      LAYER metal3 ;
      RECT 279.620 161.915 280.000 161.985 ;
    END
  END m_axis_rc_tdata[10]
  PIN m_axis_rc_tdata[11]
    DIRECTION OUTPUT ;
    USE SIGNAL ;
    PORT
      LAYER metal3 ;
      RECT 279.620 162.295 280.000 162.365 ;
    END
  END m_axis_rc_tdata[11]
  PIN m_axis_rc_tdata[12]
    DIRECTION OUTPUT ;
    USE SIGNAL ;
    PORT
      LAYER metal3 ;
      RECT 279.620 162.675 280.000 162.745 ;
    END
  END m_axis_rc_tdata[12]
  PIN m_axis_rc_tdata[13]
    DIRECTION OUTPUT ;
    USE SIGNAL ;
    PORT
      LAYER metal3 ;
      RECT 279.620 163.055 280.000 163.125 ;
    END
  END m_axis_rc_tdata[13]
  PIN m_axis_rc_tdata[14]
    DIRECTION OUTPUT ;
    USE SIGNAL ;
    PORT
      LAYER metal3 ;
      RECT 279.620 163.435 280.000 163.505 ;
    END
  END m_axis_rc_tdata[14]
  PIN m_axis_rc_tdata[15]
    DIRECTION OUTPUT ;
    USE SIGNAL ;
    PORT
      LAYER metal3 ;
      RECT 279.620 163.815 280.000 163.885 ;
    END
  END m_axis_rc_tdata[15]
  PIN m_axis_rc_tdata[16]
    DIRECTION OUTPUT ;
    USE SIGNAL ;
    PORT
      LAYER metal3 ;
      RECT 279.620 164.195 280.000 164.265 ;
    END
  END m_axis_rc_tdata[16]
  PIN m_axis_rc_tdata[17]
    DIRECTION OUTPUT ;
    USE SIGNAL ;
    PORT
      LAYER metal3 ;
      RECT 279.620 164.575 280.000 164.645 ;
    END
  END m_axis_rc_tdata[17]
  PIN m_axis_rc_tdata[18]
    DIRECTION OUTPUT ;
    USE SIGNAL ;
    PORT
      LAYER metal3 ;
      RECT 279.620 164.955 280.000 165.025 ;
    END
  END m_axis_rc_tdata[18]
  PIN m_axis_rc_tdata[19]
    DIRECTION OUTPUT ;
    USE SIGNAL ;
    PORT
      LAYER metal3 ;
      RECT 279.620 165.335 280.000 165.405 ;
    END
  END m_axis_rc_tdata[19]
  PIN m_axis_rc_tdata[20]
    DIRECTION OUTPUT ;
    USE SIGNAL ;
    PORT
      LAYER metal3 ;
      RECT 279.620 165.715 280.000 165.785 ;
    END
  END m_axis_rc_tdata[20]
  PIN m_axis_rc_tdata[21]
    DIRECTION OUTPUT ;
    USE SIGNAL ;
    PORT
      LAYER metal3 ;
      RECT 279.620 166.095 280.000 166.165 ;
    END
  END m_axis_rc_tdata[21]
  PIN m_axis_rc_tdata[22]
    DIRECTION OUTPUT ;
    USE SIGNAL ;
    PORT
      LAYER metal3 ;
      RECT 279.620 166.475 280.000 166.545 ;
    END
  END m_axis_rc_tdata[22]
  PIN m_axis_rc_tdata[23]
    DIRECTION OUTPUT ;
    USE SIGNAL ;
    PORT
      LAYER metal3 ;
      RECT 279.620 166.855 280.000 166.925 ;
    END
  END m_axis_rc_tdata[23]
  PIN m_axis_rc_tdata[24]
    DIRECTION OUTPUT ;
    USE SIGNAL ;
    PORT
      LAYER metal3 ;
      RECT 279.620 167.235 280.000 167.305 ;
    END
  END m_axis_rc_tdata[24]
  PIN m_axis_rc_tdata[25]
    DIRECTION OUTPUT ;
    USE SIGNAL ;
    PORT
      LAYER metal3 ;
      RECT 279.620 167.615 280.000 167.685 ;
    END
  END m_axis_rc_tdata[25]
  PIN m_axis_rc_tdata[26]
    DIRECTION OUTPUT ;
    USE SIGNAL ;
    PORT
      LAYER metal3 ;
      RECT 279.620 167.995 280.000 168.065 ;
    END
  END m_axis_rc_tdata[26]
  PIN m_axis_rc_tdata[27]
    DIRECTION OUTPUT ;
    USE SIGNAL ;
    PORT
      LAYER metal3 ;
      RECT 279.620 168.375 280.000 168.445 ;
    END
  END m_axis_rc_tdata[27]
  PIN m_axis_rc_tdata[28]
    DIRECTION OUTPUT ;
    USE SIGNAL ;
    PORT
      LAYER metal3 ;
      RECT 279.620 168.755 280.000 168.825 ;
    END
  END m_axis_rc_tdata[28]
  PIN m_axis_rc_tdata[29]
    DIRECTION OUTPUT ;
    USE SIGNAL ;
    PORT
      LAYER metal3 ;
      RECT 279.620 169.135 280.000 169.205 ;
    END
  END m_axis_rc_tdata[29]
  PIN m_axis_rc_tdata[30]
    DIRECTION OUTPUT ;
    USE SIGNAL ;
    PORT
      LAYER metal3 ;
      RECT 279.620 169.515 280.000 169.585 ;
    END
  END m_axis_rc_tdata[30]
  PIN m_axis_rc_tdata[31]
    DIRECTION OUTPUT ;
    USE SIGNAL ;
    PORT
      LAYER metal3 ;
      RECT 279.620 169.895 280.000 169.965 ;
    END
  END m_axis_rc_tdata[31]
  PIN m_axis_rc_tdata[32]
    DIRECTION OUTPUT ;
    USE SIGNAL ;
    PORT
      LAYER metal3 ;
      RECT 279.620 170.275 280.000 170.345 ;
    END
  END m_axis_rc_tdata[32]
  PIN m_axis_rc_tdata[33]
    DIRECTION OUTPUT ;
    USE SIGNAL ;
    PORT
      LAYER metal3 ;
      RECT 279.620 170.655 280.000 170.725 ;
    END
  END m_axis_rc_tdata[33]
  PIN m_axis_rc_tdata[34]
    DIRECTION OUTPUT ;
    USE SIGNAL ;
    PORT
      LAYER metal3 ;
      RECT 279.620 171.035 280.000 171.105 ;
    END
  END m_axis_rc_tdata[34]
  PIN m_axis_rc_tdata[35]
    DIRECTION OUTPUT ;
    USE SIGNAL ;
    PORT
      LAYER metal3 ;
      RECT 279.620 171.415 280.000 171.485 ;
    END
  END m_axis_rc_tdata[35]
  PIN m_axis_rc_tdata[36]
    DIRECTION OUTPUT ;
    USE SIGNAL ;
    PORT
      LAYER metal3 ;
      RECT 279.620 171.795 280.000 171.865 ;
    END
  END m_axis_rc_tdata[36]
  PIN m_axis_rc_tdata[37]
    DIRECTION OUTPUT ;
    USE SIGNAL ;
    PORT
      LAYER metal3 ;
      RECT 279.620 172.175 280.000 172.245 ;
    END
  END m_axis_rc_tdata[37]
  PIN m_axis_rc_tdata[38]
    DIRECTION OUTPUT ;
    USE SIGNAL ;
    PORT
      LAYER metal3 ;
      RECT 279.620 172.555 280.000 172.625 ;
    END
  END m_axis_rc_tdata[38]
  PIN m_axis_rc_tdata[39]
    DIRECTION OUTPUT ;
    USE SIGNAL ;
    PORT
      LAYER metal3 ;
      RECT 279.620 172.935 280.000 173.005 ;
    END
  END m_axis_rc_tdata[39]
  PIN m_axis_rc_tdata[40]
    DIRECTION OUTPUT ;
    USE SIGNAL ;
    PORT
      LAYER metal3 ;
      RECT 279.620 173.315 280.000 173.385 ;
    END
  END m_axis_rc_tdata[40]
  PIN m_axis_rc_tdata[41]
    DIRECTION OUTPUT ;
    USE SIGNAL ;
    PORT
      LAYER metal3 ;
      RECT 279.620 173.695 280.000 173.765 ;
    END
  END m_axis_rc_tdata[41]
  PIN m_axis_rc_tdata[42]
    DIRECTION OUTPUT ;
    USE SIGNAL ;
    PORT
      LAYER metal3 ;
      RECT 279.620 174.075 280.000 174.145 ;
    END
  END m_axis_rc_tdata[42]
  PIN m_axis_rc_tdata[43]
    DIRECTION OUTPUT ;
    USE SIGNAL ;
    PORT
      LAYER metal3 ;
      RECT 279.620 174.455 280.000 174.525 ;
    END
  END m_axis_rc_tdata[43]
  PIN m_axis_rc_tdata[44]
    DIRECTION OUTPUT ;
    USE SIGNAL ;
    PORT
      LAYER metal3 ;
      RECT 279.620 174.835 280.000 174.905 ;
    END
  END m_axis_rc_tdata[44]
  PIN m_axis_rc_tdata[45]
    DIRECTION OUTPUT ;
    USE SIGNAL ;
    PORT
      LAYER metal3 ;
      RECT 279.620 175.215 280.000 175.285 ;
    END
  END m_axis_rc_tdata[45]
  PIN m_axis_rc_tdata[46]
    DIRECTION OUTPUT ;
    USE SIGNAL ;
    PORT
      LAYER metal3 ;
      RECT 279.620 175.595 280.000 175.665 ;
    END
  END m_axis_rc_tdata[46]
  PIN m_axis_rc_tdata[47]
    DIRECTION OUTPUT ;
    USE SIGNAL ;
    PORT
      LAYER metal3 ;
      RECT 279.620 175.975 280.000 176.045 ;
    END
  END m_axis_rc_tdata[47]
  PIN m_axis_rc_tdata[48]
    DIRECTION OUTPUT ;
    USE SIGNAL ;
    PORT
      LAYER metal3 ;
      RECT 279.620 176.355 280.000 176.425 ;
    END
  END m_axis_rc_tdata[48]
  PIN m_axis_rc_tdata[49]
    DIRECTION OUTPUT ;
    USE SIGNAL ;
    PORT
      LAYER metal3 ;
      RECT 279.620 176.735 280.000 176.805 ;
    END
  END m_axis_rc_tdata[49]
  PIN m_axis_rc_tdata[50]
    DIRECTION OUTPUT ;
    USE SIGNAL ;
    PORT
      LAYER metal3 ;
      RECT 279.620 177.115 280.000 177.185 ;
    END
  END m_axis_rc_tdata[50]
  PIN m_axis_rc_tdata[51]
    DIRECTION OUTPUT ;
    USE SIGNAL ;
    PORT
      LAYER metal3 ;
      RECT 279.620 177.495 280.000 177.565 ;
    END
  END m_axis_rc_tdata[51]
  PIN m_axis_rc_tdata[52]
    DIRECTION OUTPUT ;
    USE SIGNAL ;
    PORT
      LAYER metal3 ;
      RECT 279.620 177.875 280.000 177.945 ;
    END
  END m_axis_rc_tdata[52]
  PIN m_axis_rc_tdata[53]
    DIRECTION OUTPUT ;
    USE SIGNAL ;
    PORT
      LAYER metal3 ;
      RECT 279.620 178.255 280.000 178.325 ;
    END
  END m_axis_rc_tdata[53]
  PIN m_axis_rc_tdata[54]
    DIRECTION OUTPUT ;
    USE SIGNAL ;
    PORT
      LAYER metal3 ;
      RECT 279.620 178.635 280.000 178.705 ;
    END
  END m_axis_rc_tdata[54]
  PIN m_axis_rc_tdata[55]
    DIRECTION OUTPUT ;
    USE SIGNAL ;
    PORT
      LAYER metal3 ;
      RECT 279.620 179.015 280.000 179.085 ;
    END
  END m_axis_rc_tdata[55]
  PIN m_axis_rc_tdata[56]
    DIRECTION OUTPUT ;
    USE SIGNAL ;
    PORT
      LAYER metal3 ;
      RECT 279.620 179.395 280.000 179.465 ;
    END
  END m_axis_rc_tdata[56]
  PIN m_axis_rc_tdata[57]
    DIRECTION OUTPUT ;
    USE SIGNAL ;
    PORT
      LAYER metal3 ;
      RECT 279.620 179.775 280.000 179.845 ;
    END
  END m_axis_rc_tdata[57]
  PIN m_axis_rc_tdata[58]
    DIRECTION OUTPUT ;
    USE SIGNAL ;
    PORT
      LAYER metal3 ;
      RECT 279.620 180.155 280.000 180.225 ;
    END
  END m_axis_rc_tdata[58]
  PIN m_axis_rc_tdata[59]
    DIRECTION OUTPUT ;
    USE SIGNAL ;
    PORT
      LAYER metal3 ;
      RECT 279.620 180.535 280.000 180.605 ;
    END
  END m_axis_rc_tdata[59]
  PIN m_axis_rc_tdata[60]
    DIRECTION OUTPUT ;
    USE SIGNAL ;
    PORT
      LAYER metal3 ;
      RECT 279.620 180.915 280.000 180.985 ;
    END
  END m_axis_rc_tdata[60]
  PIN m_axis_rc_tdata[61]
    DIRECTION OUTPUT ;
    USE SIGNAL ;
    PORT
      LAYER metal3 ;
      RECT 279.620 181.295 280.000 181.365 ;
    END
  END m_axis_rc_tdata[61]
  PIN m_axis_rc_tdata[62]
    DIRECTION OUTPUT ;
    USE SIGNAL ;
    PORT
      LAYER metal3 ;
      RECT 279.620 181.675 280.000 181.745 ;
    END
  END m_axis_rc_tdata[62]
  PIN m_axis_rc_tdata[63]
    DIRECTION OUTPUT ;
    USE SIGNAL ;
    PORT
      LAYER metal3 ;
      RECT 279.620 182.055 280.000 182.125 ;
    END
  END m_axis_rc_tdata[63]
  PIN m_axis_rc_tdata[64]
    DIRECTION OUTPUT ;
    USE SIGNAL ;
    PORT
      LAYER metal3 ;
      RECT 279.620 182.435 280.000 182.505 ;
    END
  END m_axis_rc_tdata[64]
  PIN m_axis_rc_tdata[65]
    DIRECTION OUTPUT ;
    USE SIGNAL ;
    PORT
      LAYER metal3 ;
      RECT 279.620 182.815 280.000 182.885 ;
    END
  END m_axis_rc_tdata[65]
  PIN m_axis_rc_tdata[66]
    DIRECTION OUTPUT ;
    USE SIGNAL ;
    PORT
      LAYER metal3 ;
      RECT 279.620 183.195 280.000 183.265 ;
    END
  END m_axis_rc_tdata[66]
  PIN m_axis_rc_tdata[67]
    DIRECTION OUTPUT ;
    USE SIGNAL ;
    PORT
      LAYER metal3 ;
      RECT 279.620 183.575 280.000 183.645 ;
    END
  END m_axis_rc_tdata[67]
  PIN m_axis_rc_tdata[68]
    DIRECTION OUTPUT ;
    USE SIGNAL ;
    PORT
      LAYER metal3 ;
      RECT 279.620 183.955 280.000 184.025 ;
    END
  END m_axis_rc_tdata[68]
  PIN m_axis_rc_tdata[69]
    DIRECTION OUTPUT ;
    USE SIGNAL ;
    PORT
      LAYER metal3 ;
      RECT 279.620 184.335 280.000 184.405 ;
    END
  END m_axis_rc_tdata[69]
  PIN m_axis_rc_tdata[70]
    DIRECTION OUTPUT ;
    USE SIGNAL ;
    PORT
      LAYER metal3 ;
      RECT 279.620 184.715 280.000 184.785 ;
    END
  END m_axis_rc_tdata[70]
  PIN m_axis_rc_tdata[71]
    DIRECTION OUTPUT ;
    USE SIGNAL ;
    PORT
      LAYER metal3 ;
      RECT 279.620 185.095 280.000 185.165 ;
    END
  END m_axis_rc_tdata[71]
  PIN m_axis_rc_tdata[72]
    DIRECTION OUTPUT ;
    USE SIGNAL ;
    PORT
      LAYER metal3 ;
      RECT 279.620 185.475 280.000 185.545 ;
    END
  END m_axis_rc_tdata[72]
  PIN m_axis_rc_tdata[73]
    DIRECTION OUTPUT ;
    USE SIGNAL ;
    PORT
      LAYER metal3 ;
      RECT 279.620 185.855 280.000 185.925 ;
    END
  END m_axis_rc_tdata[73]
  PIN m_axis_rc_tdata[74]
    DIRECTION OUTPUT ;
    USE SIGNAL ;
    PORT
      LAYER metal3 ;
      RECT 279.620 186.235 280.000 186.305 ;
    END
  END m_axis_rc_tdata[74]
  PIN m_axis_rc_tdata[75]
    DIRECTION OUTPUT ;
    USE SIGNAL ;
    PORT
      LAYER metal3 ;
      RECT 279.620 186.615 280.000 186.685 ;
    END
  END m_axis_rc_tdata[75]
  PIN m_axis_rc_tdata[76]
    DIRECTION OUTPUT ;
    USE SIGNAL ;
    PORT
      LAYER metal3 ;
      RECT 279.620 186.995 280.000 187.065 ;
    END
  END m_axis_rc_tdata[76]
  PIN m_axis_rc_tdata[77]
    DIRECTION OUTPUT ;
    USE SIGNAL ;
    PORT
      LAYER metal3 ;
      RECT 279.620 187.375 280.000 187.445 ;
    END
  END m_axis_rc_tdata[77]
  PIN m_axis_rc_tdata[78]
    DIRECTION OUTPUT ;
    USE SIGNAL ;
    PORT
      LAYER metal3 ;
      RECT 279.620 187.755 280.000 187.825 ;
    END
  END m_axis_rc_tdata[78]
  PIN m_axis_rc_tdata[79]
    DIRECTION OUTPUT ;
    USE SIGNAL ;
    PORT
      LAYER metal3 ;
      RECT 279.620 188.135 280.000 188.205 ;
    END
  END m_axis_rc_tdata[79]
  PIN m_axis_rc_tdata[80]
    DIRECTION OUTPUT ;
    USE SIGNAL ;
    PORT
      LAYER metal3 ;
      RECT 279.620 188.515 280.000 188.585 ;
    END
  END m_axis_rc_tdata[80]
  PIN m_axis_rc_tdata[81]
    DIRECTION OUTPUT ;
    USE SIGNAL ;
    PORT
      LAYER metal3 ;
      RECT 279.620 188.895 280.000 188.965 ;
    END
  END m_axis_rc_tdata[81]
  PIN m_axis_rc_tdata[82]
    DIRECTION OUTPUT ;
    USE SIGNAL ;
    PORT
      LAYER metal3 ;
      RECT 279.620 189.275 280.000 189.345 ;
    END
  END m_axis_rc_tdata[82]
  PIN m_axis_rc_tdata[83]
    DIRECTION OUTPUT ;
    USE SIGNAL ;
    PORT
      LAYER metal3 ;
      RECT 279.620 189.655 280.000 189.725 ;
    END
  END m_axis_rc_tdata[83]
  PIN m_axis_rc_tdata[84]
    DIRECTION OUTPUT ;
    USE SIGNAL ;
    PORT
      LAYER metal3 ;
      RECT 279.620 190.035 280.000 190.105 ;
    END
  END m_axis_rc_tdata[84]
  PIN m_axis_rc_tdata[85]
    DIRECTION OUTPUT ;
    USE SIGNAL ;
    PORT
      LAYER metal3 ;
      RECT 279.620 190.415 280.000 190.485 ;
    END
  END m_axis_rc_tdata[85]
  PIN m_axis_rc_tdata[86]
    DIRECTION OUTPUT ;
    USE SIGNAL ;
    PORT
      LAYER metal3 ;
      RECT 279.620 190.795 280.000 190.865 ;
    END
  END m_axis_rc_tdata[86]
  PIN m_axis_rc_tdata[87]
    DIRECTION OUTPUT ;
    USE SIGNAL ;
    PORT
      LAYER metal3 ;
      RECT 279.620 191.175 280.000 191.245 ;
    END
  END m_axis_rc_tdata[87]
  PIN m_axis_rc_tdata[88]
    DIRECTION OUTPUT ;
    USE SIGNAL ;
    PORT
      LAYER metal3 ;
      RECT 279.620 191.555 280.000 191.625 ;
    END
  END m_axis_rc_tdata[88]
  PIN m_axis_rc_tdata[89]
    DIRECTION OUTPUT ;
    USE SIGNAL ;
    PORT
      LAYER metal3 ;
      RECT 279.620 191.935 280.000 192.005 ;
    END
  END m_axis_rc_tdata[89]
  PIN m_axis_rc_tdata[90]
    DIRECTION OUTPUT ;
    USE SIGNAL ;
    PORT
      LAYER metal3 ;
      RECT 279.620 192.315 280.000 192.385 ;
    END
  END m_axis_rc_tdata[90]
  PIN m_axis_rc_tdata[91]
    DIRECTION OUTPUT ;
    USE SIGNAL ;
    PORT
      LAYER metal3 ;
      RECT 279.620 192.695 280.000 192.765 ;
    END
  END m_axis_rc_tdata[91]
  PIN m_axis_rc_tdata[92]
    DIRECTION OUTPUT ;
    USE SIGNAL ;
    PORT
      LAYER metal3 ;
      RECT 279.620 193.075 280.000 193.145 ;
    END
  END m_axis_rc_tdata[92]
  PIN m_axis_rc_tdata[93]
    DIRECTION OUTPUT ;
    USE SIGNAL ;
    PORT
      LAYER metal3 ;
      RECT 279.620 193.455 280.000 193.525 ;
    END
  END m_axis_rc_tdata[93]
  PIN m_axis_rc_tdata[94]
    DIRECTION OUTPUT ;
    USE SIGNAL ;
    PORT
      LAYER metal3 ;
      RECT 279.620 193.835 280.000 193.905 ;
    END
  END m_axis_rc_tdata[94]
  PIN m_axis_rc_tdata[95]
    DIRECTION OUTPUT ;
    USE SIGNAL ;
    PORT
      LAYER metal3 ;
      RECT 279.620 194.215 280.000 194.285 ;
    END
  END m_axis_rc_tdata[95]
  PIN m_axis_rc_tdata[96]
    DIRECTION OUTPUT ;
    USE SIGNAL ;
    PORT
      LAYER metal3 ;
      RECT 279.620 194.595 280.000 194.665 ;
    END
  END m_axis_rc_tdata[96]
  PIN m_axis_rc_tdata[97]
    DIRECTION OUTPUT ;
    USE SIGNAL ;
    PORT
      LAYER metal3 ;
      RECT 279.620 194.975 280.000 195.045 ;
    END
  END m_axis_rc_tdata[97]
  PIN m_axis_rc_tdata[98]
    DIRECTION OUTPUT ;
    USE SIGNAL ;
    PORT
      LAYER metal3 ;
      RECT 279.620 195.355 280.000 195.425 ;
    END
  END m_axis_rc_tdata[98]
  PIN m_axis_rc_tdata[99]
    DIRECTION OUTPUT ;
    USE SIGNAL ;
    PORT
      LAYER metal3 ;
      RECT 279.620 195.735 280.000 195.805 ;
    END
  END m_axis_rc_tdata[99]
  PIN m_axis_rc_tdata[100]
    DIRECTION OUTPUT ;
    USE SIGNAL ;
    PORT
      LAYER metal3 ;
      RECT 279.620 196.115 280.000 196.185 ;
    END
  END m_axis_rc_tdata[100]
  PIN m_axis_rc_tdata[101]
    DIRECTION OUTPUT ;
    USE SIGNAL ;
    PORT
      LAYER metal3 ;
      RECT 279.620 196.495 280.000 196.565 ;
    END
  END m_axis_rc_tdata[101]
  PIN m_axis_rc_tdata[102]
    DIRECTION OUTPUT ;
    USE SIGNAL ;
    PORT
      LAYER metal3 ;
      RECT 279.620 196.875 280.000 196.945 ;
    END
  END m_axis_rc_tdata[102]
  PIN m_axis_rc_tdata[103]
    DIRECTION OUTPUT ;
    USE SIGNAL ;
    PORT
      LAYER metal3 ;
      RECT 279.620 197.255 280.000 197.325 ;
    END
  END m_axis_rc_tdata[103]
  PIN m_axis_rc_tdata[104]
    DIRECTION OUTPUT ;
    USE SIGNAL ;
    PORT
      LAYER metal3 ;
      RECT 279.620 197.635 280.000 197.705 ;
    END
  END m_axis_rc_tdata[104]
  PIN m_axis_rc_tdata[105]
    DIRECTION OUTPUT ;
    USE SIGNAL ;
    PORT
      LAYER metal3 ;
      RECT 279.620 198.015 280.000 198.085 ;
    END
  END m_axis_rc_tdata[105]
  PIN m_axis_rc_tdata[106]
    DIRECTION OUTPUT ;
    USE SIGNAL ;
    PORT
      LAYER metal3 ;
      RECT 279.620 198.395 280.000 198.465 ;
    END
  END m_axis_rc_tdata[106]
  PIN m_axis_rc_tdata[107]
    DIRECTION OUTPUT ;
    USE SIGNAL ;
    PORT
      LAYER metal3 ;
      RECT 279.620 198.775 280.000 198.845 ;
    END
  END m_axis_rc_tdata[107]
  PIN m_axis_rc_tdata[108]
    DIRECTION OUTPUT ;
    USE SIGNAL ;
    PORT
      LAYER metal3 ;
      RECT 279.620 199.155 280.000 199.225 ;
    END
  END m_axis_rc_tdata[108]
  PIN m_axis_rc_tdata[109]
    DIRECTION OUTPUT ;
    USE SIGNAL ;
    PORT
      LAYER metal3 ;
      RECT 279.620 199.535 280.000 199.605 ;
    END
  END m_axis_rc_tdata[109]
  PIN m_axis_rc_tdata[110]
    DIRECTION OUTPUT ;
    USE SIGNAL ;
    PORT
      LAYER metal3 ;
      RECT 279.620 199.915 280.000 199.985 ;
    END
  END m_axis_rc_tdata[110]
  PIN m_axis_rc_tdata[111]
    DIRECTION OUTPUT ;
    USE SIGNAL ;
    PORT
      LAYER metal3 ;
      RECT 279.620 200.295 280.000 200.365 ;
    END
  END m_axis_rc_tdata[111]
  PIN m_axis_rc_tdata[112]
    DIRECTION OUTPUT ;
    USE SIGNAL ;
    PORT
      LAYER metal3 ;
      RECT 279.620 200.675 280.000 200.745 ;
    END
  END m_axis_rc_tdata[112]
  PIN m_axis_rc_tdata[113]
    DIRECTION OUTPUT ;
    USE SIGNAL ;
    PORT
      LAYER metal3 ;
      RECT 279.620 201.055 280.000 201.125 ;
    END
  END m_axis_rc_tdata[113]
  PIN m_axis_rc_tdata[114]
    DIRECTION OUTPUT ;
    USE SIGNAL ;
    PORT
      LAYER metal3 ;
      RECT 279.620 201.435 280.000 201.505 ;
    END
  END m_axis_rc_tdata[114]
  PIN m_axis_rc_tdata[115]
    DIRECTION OUTPUT ;
    USE SIGNAL ;
    PORT
      LAYER metal3 ;
      RECT 279.620 201.815 280.000 201.885 ;
    END
  END m_axis_rc_tdata[115]
  PIN m_axis_rc_tdata[116]
    DIRECTION OUTPUT ;
    USE SIGNAL ;
    PORT
      LAYER metal3 ;
      RECT 279.620 202.195 280.000 202.265 ;
    END
  END m_axis_rc_tdata[116]
  PIN m_axis_rc_tdata[117]
    DIRECTION OUTPUT ;
    USE SIGNAL ;
    PORT
      LAYER metal3 ;
      RECT 279.620 202.575 280.000 202.645 ;
    END
  END m_axis_rc_tdata[117]
  PIN m_axis_rc_tdata[118]
    DIRECTION OUTPUT ;
    USE SIGNAL ;
    PORT
      LAYER metal3 ;
      RECT 279.620 202.955 280.000 203.025 ;
    END
  END m_axis_rc_tdata[118]
  PIN m_axis_rc_tdata[119]
    DIRECTION OUTPUT ;
    USE SIGNAL ;
    PORT
      LAYER metal3 ;
      RECT 279.620 203.335 280.000 203.405 ;
    END
  END m_axis_rc_tdata[119]
  PIN m_axis_rc_tdata[120]
    DIRECTION OUTPUT ;
    USE SIGNAL ;
    PORT
      LAYER metal3 ;
      RECT 279.620 203.715 280.000 203.785 ;
    END
  END m_axis_rc_tdata[120]
  PIN m_axis_rc_tdata[121]
    DIRECTION OUTPUT ;
    USE SIGNAL ;
    PORT
      LAYER metal3 ;
      RECT 279.620 204.095 280.000 204.165 ;
    END
  END m_axis_rc_tdata[121]
  PIN m_axis_rc_tdata[122]
    DIRECTION OUTPUT ;
    USE SIGNAL ;
    PORT
      LAYER metal3 ;
      RECT 279.620 204.475 280.000 204.545 ;
    END
  END m_axis_rc_tdata[122]
  PIN m_axis_rc_tdata[123]
    DIRECTION OUTPUT ;
    USE SIGNAL ;
    PORT
      LAYER metal3 ;
      RECT 279.620 204.855 280.000 204.925 ;
    END
  END m_axis_rc_tdata[123]
  PIN m_axis_rc_tdata[124]
    DIRECTION OUTPUT ;
    USE SIGNAL ;
    PORT
      LAYER metal3 ;
      RECT 279.620 205.235 280.000 205.305 ;
    END
  END m_axis_rc_tdata[124]
  PIN m_axis_rc_tdata[125]
    DIRECTION OUTPUT ;
    USE SIGNAL ;
    PORT
      LAYER metal3 ;
      RECT 279.620 205.615 280.000 205.685 ;
    END
  END m_axis_rc_tdata[125]
  PIN m_axis_rc_tdata[126]
    DIRECTION OUTPUT ;
    USE SIGNAL ;
    PORT
      LAYER metal3 ;
      RECT 279.620 205.995 280.000 206.065 ;
    END
  END m_axis_rc_tdata[126]
  PIN m_axis_rc_tdata[127]
    DIRECTION OUTPUT ;
    USE SIGNAL ;
    PORT
      LAYER metal3 ;
      RECT 279.620 206.375 280.000 206.445 ;
    END
  END m_axis_rc_tdata[127]
  PIN m_axis_rc_tkeep[0]
    DIRECTION OUTPUT ;
    USE SIGNAL ;
    PORT
      LAYER metal3 ;
      RECT 279.620 206.755 280.000 206.825 ;
    END
  END m_axis_rc_tkeep[0]
  PIN m_axis_rc_tkeep[1]
    DIRECTION OUTPUT ;
    USE SIGNAL ;
    PORT
      LAYER metal3 ;
      RECT 279.620 207.135 280.000 207.205 ;
    END
  END m_axis_rc_tkeep[1]
  PIN m_axis_rc_tkeep[2]
    DIRECTION OUTPUT ;
    USE SIGNAL ;
    PORT
      LAYER metal3 ;
      RECT 279.620 207.515 280.000 207.585 ;
    END
  END m_axis_rc_tkeep[2]
  PIN m_axis_rc_tkeep[3]
    DIRECTION OUTPUT ;
    USE SIGNAL ;
    PORT
      LAYER metal3 ;
      RECT 279.620 207.895 280.000 207.965 ;
    END
  END m_axis_rc_tkeep[3]
  PIN m_axis_rc_tlast
    DIRECTION OUTPUT ;
    USE SIGNAL ;
    PORT
      LAYER metal3 ;
      RECT 279.620 208.275 280.000 208.345 ;
    END
  END m_axis_rc_tlast
  PIN m_axis_rc_tuser[0]
    DIRECTION OUTPUT ;
    USE SIGNAL ;
    PORT
      LAYER metal3 ;
      RECT 279.620 208.655 280.000 208.725 ;
    END
  END m_axis_rc_tuser[0]
  PIN m_axis_rc_tuser[1]
    DIRECTION OUTPUT ;
    USE SIGNAL ;
    PORT
      LAYER metal3 ;
      RECT 279.620 209.035 280.000 209.105 ;
    END
  END m_axis_rc_tuser[1]
  PIN m_axis_rc_tuser[2]
    DIRECTION OUTPUT ;
    USE SIGNAL ;
    PORT
      LAYER metal3 ;
      RECT 279.620 209.415 280.000 209.485 ;
    END
  END m_axis_rc_tuser[2]
  PIN m_axis_rc_tuser[3]
    DIRECTION OUTPUT ;
    USE SIGNAL ;
    PORT
      LAYER metal3 ;
      RECT 279.620 209.795 280.000 209.865 ;
    END
  END m_axis_rc_tuser[3]
  PIN m_axis_rc_tuser[4]
    DIRECTION OUTPUT ;
    USE SIGNAL ;
    PORT
      LAYER metal3 ;
      RECT 279.620 210.175 280.000 210.245 ;
    END
  END m_axis_rc_tuser[4]
  PIN m_axis_rc_tuser[5]
    DIRECTION OUTPUT ;
    USE SIGNAL ;
    PORT
      LAYER metal3 ;
      RECT 279.620 210.555 280.000 210.625 ;
    END
  END m_axis_rc_tuser[5]
  PIN m_axis_rc_tuser[6]
    DIRECTION OUTPUT ;
    USE SIGNAL ;
    PORT
      LAYER metal3 ;
      RECT 279.620 210.935 280.000 211.005 ;
    END
  END m_axis_rc_tuser[6]
  PIN m_axis_rc_tuser[7]
    DIRECTION OUTPUT ;
    USE SIGNAL ;
    PORT
      LAYER metal3 ;
      RECT 279.620 211.315 280.000 211.385 ;
    END
  END m_axis_rc_tuser[7]
  PIN m_axis_rc_tuser[8]
    DIRECTION OUTPUT ;
    USE SIGNAL ;
    PORT
      LAYER metal3 ;
      RECT 279.620 211.695 280.000 211.765 ;
    END
  END m_axis_rc_tuser[8]
  PIN m_axis_rc_tuser[9]
    DIRECTION OUTPUT ;
    USE SIGNAL ;
    PORT
      LAYER metal3 ;
      RECT 279.620 212.075 280.000 212.145 ;
    END
  END m_axis_rc_tuser[9]
  PIN m_axis_rc_tuser[10]
    DIRECTION OUTPUT ;
    USE SIGNAL ;
    PORT
      LAYER metal3 ;
      RECT 279.620 212.455 280.000 212.525 ;
    END
  END m_axis_rc_tuser[10]
  PIN m_axis_rc_tuser[11]
    DIRECTION OUTPUT ;
    USE SIGNAL ;
    PORT
      LAYER metal3 ;
      RECT 279.620 212.835 280.000 212.905 ;
    END
  END m_axis_rc_tuser[11]
  PIN m_axis_rc_tuser[12]
    DIRECTION OUTPUT ;
    USE SIGNAL ;
    PORT
      LAYER metal3 ;
      RECT 279.620 213.215 280.000 213.285 ;
    END
  END m_axis_rc_tuser[12]
  PIN m_axis_rc_tuser[13]
    DIRECTION OUTPUT ;
    USE SIGNAL ;
    PORT
      LAYER metal3 ;
      RECT 279.620 213.595 280.000 213.665 ;
    END
  END m_axis_rc_tuser[13]
  PIN m_axis_rc_tuser[14]
    DIRECTION OUTPUT ;
    USE SIGNAL ;
    PORT
      LAYER metal3 ;
      RECT 279.620 213.975 280.000 214.045 ;
    END
  END m_axis_rc_tuser[14]
  PIN m_axis_rc_tuser[15]
    DIRECTION OUTPUT ;
    USE SIGNAL ;
    PORT
      LAYER metal3 ;
      RECT 279.620 214.355 280.000 214.425 ;
    END
  END m_axis_rc_tuser[15]
  PIN m_axis_rc_tuser[16]
    DIRECTION OUTPUT ;
    USE SIGNAL ;
    PORT
      LAYER metal3 ;
      RECT 279.620 214.735 280.000 214.805 ;
    END
  END m_axis_rc_tuser[16]
  PIN m_axis_rc_tuser[17]
    DIRECTION OUTPUT ;
    USE SIGNAL ;
    PORT
      LAYER metal3 ;
      RECT 279.620 215.115 280.000 215.185 ;
    END
  END m_axis_rc_tuser[17]
  PIN m_axis_rc_tuser[18]
    DIRECTION OUTPUT ;
    USE SIGNAL ;
    PORT
      LAYER metal3 ;
      RECT 279.620 215.495 280.000 215.565 ;
    END
  END m_axis_rc_tuser[18]
  PIN m_axis_rc_tuser[19]
    DIRECTION OUTPUT ;
    USE SIGNAL ;
    PORT
      LAYER metal3 ;
      RECT 279.620 215.875 280.000 215.945 ;
    END
  END m_axis_rc_tuser[19]
  PIN m_axis_rc_tuser[20]
    DIRECTION OUTPUT ;
    USE SIGNAL ;
    PORT
      LAYER metal3 ;
      RECT 279.620 216.255 280.000 216.325 ;
    END
  END m_axis_rc_tuser[20]
  PIN m_axis_rc_tuser[21]
    DIRECTION OUTPUT ;
    USE SIGNAL ;
    PORT
      LAYER metal3 ;
      RECT 279.620 216.635 280.000 216.705 ;
    END
  END m_axis_rc_tuser[21]
  PIN m_axis_rc_tuser[22]
    DIRECTION OUTPUT ;
    USE SIGNAL ;
    PORT
      LAYER metal3 ;
      RECT 279.620 217.015 280.000 217.085 ;
    END
  END m_axis_rc_tuser[22]
  PIN m_axis_rc_tuser[23]
    DIRECTION OUTPUT ;
    USE SIGNAL ;
    PORT
      LAYER metal3 ;
      RECT 279.620 217.395 280.000 217.465 ;
    END
  END m_axis_rc_tuser[23]
  PIN m_axis_rc_tuser[24]
    DIRECTION OUTPUT ;
    USE SIGNAL ;
    PORT
      LAYER metal3 ;
      RECT 279.620 217.775 280.000 217.845 ;
    END
  END m_axis_rc_tuser[24]
  PIN m_axis_rc_tuser[25]
    DIRECTION OUTPUT ;
    USE SIGNAL ;
    PORT
      LAYER metal3 ;
      RECT 279.620 218.155 280.000 218.225 ;
    END
  END m_axis_rc_tuser[25]
  PIN m_axis_rc_tuser[26]
    DIRECTION OUTPUT ;
    USE SIGNAL ;
    PORT
      LAYER metal3 ;
      RECT 279.620 218.535 280.000 218.605 ;
    END
  END m_axis_rc_tuser[26]
  PIN m_axis_rc_tuser[27]
    DIRECTION OUTPUT ;
    USE SIGNAL ;
    PORT
      LAYER metal3 ;
      RECT 279.620 218.915 280.000 218.985 ;
    END
  END m_axis_rc_tuser[27]
  PIN m_axis_rc_tuser[28]
    DIRECTION OUTPUT ;
    USE SIGNAL ;
    PORT
      LAYER metal3 ;
      RECT 279.620 219.295 280.000 219.365 ;
    END
  END m_axis_rc_tuser[28]
  PIN m_axis_rc_tuser[29]
    DIRECTION OUTPUT ;
    USE SIGNAL ;
    PORT
      LAYER metal3 ;
      RECT 279.620 219.675 280.000 219.745 ;
    END
  END m_axis_rc_tuser[29]
  PIN m_axis_rc_tuser[30]
    DIRECTION OUTPUT ;
    USE SIGNAL ;
    PORT
      LAYER metal3 ;
      RECT 279.620 220.055 280.000 220.125 ;
    END
  END m_axis_rc_tuser[30]
  PIN m_axis_rc_tuser[31]
    DIRECTION OUTPUT ;
    USE SIGNAL ;
    PORT
      LAYER metal3 ;
      RECT 279.620 220.435 280.000 220.505 ;
    END
  END m_axis_rc_tuser[31]
  PIN m_axis_rc_tuser[32]
    DIRECTION OUTPUT ;
    USE SIGNAL ;
    PORT
      LAYER metal3 ;
      RECT 279.620 220.815 280.000 220.885 ;
    END
  END m_axis_rc_tuser[32]
  PIN m_axis_rc_tuser[33]
    DIRECTION OUTPUT ;
    USE SIGNAL ;
    PORT
      LAYER metal3 ;
      RECT 279.620 221.195 280.000 221.265 ;
    END
  END m_axis_rc_tuser[33]
  PIN m_axis_rc_tuser[34]
    DIRECTION OUTPUT ;
    USE SIGNAL ;
    PORT
      LAYER metal3 ;
      RECT 279.620 221.575 280.000 221.645 ;
    END
  END m_axis_rc_tuser[34]
  PIN m_axis_rc_tuser[35]
    DIRECTION OUTPUT ;
    USE SIGNAL ;
    PORT
      LAYER metal3 ;
      RECT 279.620 221.955 280.000 222.025 ;
    END
  END m_axis_rc_tuser[35]
  PIN m_axis_rc_tuser[36]
    DIRECTION OUTPUT ;
    USE SIGNAL ;
    PORT
      LAYER metal3 ;
      RECT 279.620 222.335 280.000 222.405 ;
    END
  END m_axis_rc_tuser[36]
  PIN m_axis_rc_tuser[37]
    DIRECTION OUTPUT ;
    USE SIGNAL ;
    PORT
      LAYER metal3 ;
      RECT 279.620 222.715 280.000 222.785 ;
    END
  END m_axis_rc_tuser[37]
  PIN m_axis_rc_tuser[38]
    DIRECTION OUTPUT ;
    USE SIGNAL ;
    PORT
      LAYER metal3 ;
      RECT 279.620 223.095 280.000 223.165 ;
    END
  END m_axis_rc_tuser[38]
  PIN m_axis_rc_tuser[39]
    DIRECTION OUTPUT ;
    USE SIGNAL ;
    PORT
      LAYER metal3 ;
      RECT 279.620 223.475 280.000 223.545 ;
    END
  END m_axis_rc_tuser[39]
  PIN m_axis_rc_tuser[40]
    DIRECTION OUTPUT ;
    USE SIGNAL ;
    PORT
      LAYER metal3 ;
      RECT 279.620 223.855 280.000 223.925 ;
    END
  END m_axis_rc_tuser[40]
  PIN m_axis_rc_tuser[41]
    DIRECTION OUTPUT ;
    USE SIGNAL ;
    PORT
      LAYER metal3 ;
      RECT 279.620 224.235 280.000 224.305 ;
    END
  END m_axis_rc_tuser[41]
  PIN m_axis_rc_tuser[42]
    DIRECTION OUTPUT ;
    USE SIGNAL ;
    PORT
      LAYER metal3 ;
      RECT 279.620 224.615 280.000 224.685 ;
    END
  END m_axis_rc_tuser[42]
  PIN m_axis_rc_tuser[43]
    DIRECTION OUTPUT ;
    USE SIGNAL ;
    PORT
      LAYER metal3 ;
      RECT 279.620 224.995 280.000 225.065 ;
    END
  END m_axis_rc_tuser[43]
  PIN m_axis_rc_tuser[44]
    DIRECTION OUTPUT ;
    USE SIGNAL ;
    PORT
      LAYER metal3 ;
      RECT 279.620 225.375 280.000 225.445 ;
    END
  END m_axis_rc_tuser[44]
  PIN m_axis_rc_tuser[45]
    DIRECTION OUTPUT ;
    USE SIGNAL ;
    PORT
      LAYER metal3 ;
      RECT 279.620 225.755 280.000 225.825 ;
    END
  END m_axis_rc_tuser[45]
  PIN m_axis_rc_tuser[46]
    DIRECTION OUTPUT ;
    USE SIGNAL ;
    PORT
      LAYER metal3 ;
      RECT 279.620 226.135 280.000 226.205 ;
    END
  END m_axis_rc_tuser[46]
  PIN m_axis_rc_tuser[47]
    DIRECTION OUTPUT ;
    USE SIGNAL ;
    PORT
      LAYER metal3 ;
      RECT 279.620 226.515 280.000 226.585 ;
    END
  END m_axis_rc_tuser[47]
  PIN m_axis_rc_tuser[48]
    DIRECTION OUTPUT ;
    USE SIGNAL ;
    PORT
      LAYER metal3 ;
      RECT 279.620 226.895 280.000 226.965 ;
    END
  END m_axis_rc_tuser[48]
  PIN m_axis_rc_tuser[49]
    DIRECTION OUTPUT ;
    USE SIGNAL ;
    PORT
      LAYER metal3 ;
      RECT 279.620 227.275 280.000 227.345 ;
    END
  END m_axis_rc_tuser[49]
  PIN m_axis_rc_tuser[50]
    DIRECTION OUTPUT ;
    USE SIGNAL ;
    PORT
      LAYER metal3 ;
      RECT 279.620 227.655 280.000 227.725 ;
    END
  END m_axis_rc_tuser[50]
  PIN m_axis_rc_tuser[51]
    DIRECTION OUTPUT ;
    USE SIGNAL ;
    PORT
      LAYER metal3 ;
      RECT 279.620 228.035 280.000 228.105 ;
    END
  END m_axis_rc_tuser[51]
  PIN m_axis_rc_tuser[52]
    DIRECTION OUTPUT ;
    USE SIGNAL ;
    PORT
      LAYER metal3 ;
      RECT 279.620 228.415 280.000 228.485 ;
    END
  END m_axis_rc_tuser[52]
  PIN m_axis_rc_tuser[53]
    DIRECTION OUTPUT ;
    USE SIGNAL ;
    PORT
      LAYER metal3 ;
      RECT 279.620 228.795 280.000 228.865 ;
    END
  END m_axis_rc_tuser[53]
  PIN m_axis_rc_tuser[54]
    DIRECTION OUTPUT ;
    USE SIGNAL ;
    PORT
      LAYER metal3 ;
      RECT 279.620 229.175 280.000 229.245 ;
    END
  END m_axis_rc_tuser[54]
  PIN m_axis_rc_tuser[55]
    DIRECTION OUTPUT ;
    USE SIGNAL ;
    PORT
      LAYER metal3 ;
      RECT 279.620 229.555 280.000 229.625 ;
    END
  END m_axis_rc_tuser[55]
  PIN m_axis_rc_tuser[56]
    DIRECTION OUTPUT ;
    USE SIGNAL ;
    PORT
      LAYER metal3 ;
      RECT 279.620 229.935 280.000 230.005 ;
    END
  END m_axis_rc_tuser[56]
  PIN m_axis_rc_tuser[57]
    DIRECTION OUTPUT ;
    USE SIGNAL ;
    PORT
      LAYER metal3 ;
      RECT 279.620 230.315 280.000 230.385 ;
    END
  END m_axis_rc_tuser[57]
  PIN m_axis_rc_tuser[58]
    DIRECTION OUTPUT ;
    USE SIGNAL ;
    PORT
      LAYER metal3 ;
      RECT 279.620 230.695 280.000 230.765 ;
    END
  END m_axis_rc_tuser[58]
  PIN m_axis_rc_tuser[59]
    DIRECTION OUTPUT ;
    USE SIGNAL ;
    PORT
      LAYER metal3 ;
      RECT 279.620 231.075 280.000 231.145 ;
    END
  END m_axis_rc_tuser[59]
  PIN m_axis_rc_tuser[60]
    DIRECTION OUTPUT ;
    USE SIGNAL ;
    PORT
      LAYER metal3 ;
      RECT 279.620 231.455 280.000 231.525 ;
    END
  END m_axis_rc_tuser[60]
  PIN m_axis_rc_tuser[61]
    DIRECTION OUTPUT ;
    USE SIGNAL ;
    PORT
      LAYER metal3 ;
      RECT 279.620 231.835 280.000 231.905 ;
    END
  END m_axis_rc_tuser[61]
  PIN m_axis_rc_tuser[62]
    DIRECTION OUTPUT ;
    USE SIGNAL ;
    PORT
      LAYER metal3 ;
      RECT 279.620 232.215 280.000 232.285 ;
    END
  END m_axis_rc_tuser[62]
  PIN m_axis_rc_tuser[63]
    DIRECTION OUTPUT ;
    USE SIGNAL ;
    PORT
      LAYER metal3 ;
      RECT 279.620 232.595 280.000 232.665 ;
    END
  END m_axis_rc_tuser[63]
  PIN m_axis_rc_tuser[64]
    DIRECTION OUTPUT ;
    USE SIGNAL ;
    PORT
      LAYER metal3 ;
      RECT 279.620 232.975 280.000 233.045 ;
    END
  END m_axis_rc_tuser[64]
  PIN m_axis_rc_tuser[65]
    DIRECTION OUTPUT ;
    USE SIGNAL ;
    PORT
      LAYER metal3 ;
      RECT 279.620 233.355 280.000 233.425 ;
    END
  END m_axis_rc_tuser[65]
  PIN m_axis_rc_tuser[66]
    DIRECTION OUTPUT ;
    USE SIGNAL ;
    PORT
      LAYER metal3 ;
      RECT 279.620 233.735 280.000 233.805 ;
    END
  END m_axis_rc_tuser[66]
  PIN m_axis_rc_tuser[67]
    DIRECTION OUTPUT ;
    USE SIGNAL ;
    PORT
      LAYER metal3 ;
      RECT 279.620 234.115 280.000 234.185 ;
    END
  END m_axis_rc_tuser[67]
  PIN m_axis_rc_tuser[68]
    DIRECTION OUTPUT ;
    USE SIGNAL ;
    PORT
      LAYER metal3 ;
      RECT 279.620 234.495 280.000 234.565 ;
    END
  END m_axis_rc_tuser[68]
  PIN m_axis_rc_tuser[69]
    DIRECTION OUTPUT ;
    USE SIGNAL ;
    PORT
      LAYER metal3 ;
      RECT 279.620 234.875 280.000 234.945 ;
    END
  END m_axis_rc_tuser[69]
  PIN m_axis_rc_tuser[70]
    DIRECTION OUTPUT ;
    USE SIGNAL ;
    PORT
      LAYER metal3 ;
      RECT 279.620 235.255 280.000 235.325 ;
    END
  END m_axis_rc_tuser[70]
  PIN m_axis_rc_tuser[71]
    DIRECTION OUTPUT ;
    USE SIGNAL ;
    PORT
      LAYER metal3 ;
      RECT 279.620 235.635 280.000 235.705 ;
    END
  END m_axis_rc_tuser[71]
  PIN m_axis_rc_tuser[72]
    DIRECTION OUTPUT ;
    USE SIGNAL ;
    PORT
      LAYER metal3 ;
      RECT 279.620 236.015 280.000 236.085 ;
    END
  END m_axis_rc_tuser[72]
  PIN m_axis_rc_tuser[73]
    DIRECTION OUTPUT ;
    USE SIGNAL ;
    PORT
      LAYER metal3 ;
      RECT 279.620 236.395 280.000 236.465 ;
    END
  END m_axis_rc_tuser[73]
  PIN m_axis_rc_tuser[74]
    DIRECTION OUTPUT ;
    USE SIGNAL ;
    PORT
      LAYER metal3 ;
      RECT 279.620 236.775 280.000 236.845 ;
    END
  END m_axis_rc_tuser[74]
  PIN m_axis_rc_tvalid
    DIRECTION OUTPUT ;
    USE SIGNAL ;
    PORT
      LAYER metal3 ;
      RECT 279.620 237.155 280.000 237.225 ;
    END
  END m_axis_rc_tvalid
  PIN pci_exp_txn
    DIRECTION OUTPUT ;
    USE SIGNAL ;
    PORT
      LAYER metal3 ;
      RECT 279.620 237.535 280.000 237.605 ;
    END
  END pci_exp_txn
  PIN pci_exp_txp
    DIRECTION OUTPUT ;
    USE SIGNAL ;
    PORT
      LAYER metal3 ;
      RECT 279.620 237.915 280.000 237.985 ;
    END
  END pci_exp_txp
  PIN pcie_perstn0_out
    DIRECTION OUTPUT ;
    USE SIGNAL ;
    PORT
      LAYER metal3 ;
      RECT 279.620 238.295 280.000 238.365 ;
    END
  END pcie_perstn0_out
  PIN pcie_perstn1_out
    DIRECTION OUTPUT ;
    USE SIGNAL ;
    PORT
      LAYER metal3 ;
      RECT 279.620 238.675 280.000 238.745 ;
    END
  END pcie_perstn1_out
  PIN pcie_rq_tag_av[0]
    DIRECTION OUTPUT ;
    USE SIGNAL ;
    PORT
      LAYER metal3 ;
      RECT 279.620 239.055 280.000 239.125 ;
    END
  END pcie_rq_tag_av[0]
  PIN pcie_rq_tag_av[1]
    DIRECTION OUTPUT ;
    USE SIGNAL ;
    PORT
      LAYER metal3 ;
      RECT 279.620 239.435 280.000 239.505 ;
    END
  END pcie_rq_tag_av[1]
  PIN pcie_rq_tag_av[2]
    DIRECTION OUTPUT ;
    USE SIGNAL ;
    PORT
      LAYER metal3 ;
      RECT 279.620 239.815 280.000 239.885 ;
    END
  END pcie_rq_tag_av[2]
  PIN pcie_rq_tag_av[3]
    DIRECTION OUTPUT ;
    USE SIGNAL ;
    PORT
      LAYER metal3 ;
      RECT 279.620 240.195 280.000 240.265 ;
    END
  END pcie_rq_tag_av[3]
  PIN pcie_tfc_npd_av[0]
    DIRECTION OUTPUT ;
    USE SIGNAL ;
    PORT
      LAYER metal3 ;
      RECT 279.620 240.575 280.000 240.645 ;
    END
  END pcie_tfc_npd_av[0]
  PIN pcie_tfc_npd_av[1]
    DIRECTION OUTPUT ;
    USE SIGNAL ;
    PORT
      LAYER metal3 ;
      RECT 279.620 240.955 280.000 241.025 ;
    END
  END pcie_tfc_npd_av[1]
  PIN pcie_tfc_npd_av[2]
    DIRECTION OUTPUT ;
    USE SIGNAL ;
    PORT
      LAYER metal3 ;
      RECT 279.620 241.335 280.000 241.405 ;
    END
  END pcie_tfc_npd_av[2]
  PIN pcie_tfc_npd_av[3]
    DIRECTION OUTPUT ;
    USE SIGNAL ;
    PORT
      LAYER metal3 ;
      RECT 279.620 241.715 280.000 241.785 ;
    END
  END pcie_tfc_npd_av[3]
  PIN pcie_tfc_nph_av[0]
    DIRECTION OUTPUT ;
    USE SIGNAL ;
    PORT
      LAYER metal3 ;
      RECT 279.620 242.095 280.000 242.165 ;
    END
  END pcie_tfc_nph_av[0]
  PIN pcie_tfc_nph_av[1]
    DIRECTION OUTPUT ;
    USE SIGNAL ;
    PORT
      LAYER metal3 ;
      RECT 279.620 242.475 280.000 242.545 ;
    END
  END pcie_tfc_nph_av[1]
  PIN pcie_tfc_nph_av[2]
    DIRECTION OUTPUT ;
    USE SIGNAL ;
    PORT
      LAYER metal3 ;
      RECT 279.620 242.855 280.000 242.925 ;
    END
  END pcie_tfc_nph_av[2]
  PIN pcie_tfc_nph_av[3]
    DIRECTION OUTPUT ;
    USE SIGNAL ;
    PORT
      LAYER metal3 ;
      RECT 279.620 243.235 280.000 243.305 ;
    END
  END pcie_tfc_nph_av[3]
  PIN phy_rdy_out
    DIRECTION OUTPUT ;
    USE SIGNAL ;
    PORT
      LAYER metal3 ;
      RECT 279.620 243.615 280.000 243.685 ;
    END
  END phy_rdy_out
  PIN s_axis_cc_tready[0]
    DIRECTION OUTPUT ;
    USE SIGNAL ;
    PORT
      LAYER metal3 ;
      RECT 279.620 243.995 280.000 244.065 ;
    END
  END s_axis_cc_tready[0]
  PIN s_axis_cc_tready[1]
    DIRECTION OUTPUT ;
    USE SIGNAL ;
    PORT
      LAYER metal3 ;
      RECT 279.620 244.375 280.000 244.445 ;
    END
  END s_axis_cc_tready[1]
  PIN s_axis_cc_tready[2]
    DIRECTION OUTPUT ;
    USE SIGNAL ;
    PORT
      LAYER metal3 ;
      RECT 279.620 244.755 280.000 244.825 ;
    END
  END s_axis_cc_tready[2]
  PIN s_axis_cc_tready[3]
    DIRECTION OUTPUT ;
    USE SIGNAL ;
    PORT
      LAYER metal3 ;
      RECT 279.620 245.135 280.000 245.205 ;
    END
  END s_axis_cc_tready[3]
  PIN s_axis_rq_tready[0]
    DIRECTION OUTPUT ;
    USE SIGNAL ;
    PORT
      LAYER metal3 ;
      RECT 279.620 245.515 280.000 245.585 ;
    END
  END s_axis_rq_tready[0]
  PIN s_axis_rq_tready[1]
    DIRECTION OUTPUT ;
    USE SIGNAL ;
    PORT
      LAYER metal3 ;
      RECT 279.620 245.895 280.000 245.965 ;
    END
  END s_axis_rq_tready[1]
  PIN s_axis_rq_tready[2]
    DIRECTION OUTPUT ;
    USE SIGNAL ;
    PORT
      LAYER metal3 ;
      RECT 279.620 246.275 280.000 246.345 ;
    END
  END s_axis_rq_tready[2]
  PIN s_axis_rq_tready[3]
    DIRECTION OUTPUT ;
    USE SIGNAL ;
    PORT
      LAYER metal3 ;
      RECT 279.620 246.655 280.000 246.725 ;
    END
  END s_axis_rq_tready[3]
  PIN user_clk
    DIRECTION OUTPUT ;
    USE SIGNAL ;
    PORT
      LAYER metal3 ;
      RECT 279.620 247.035 280.000 247.105 ;
    END
  END user_clk
  PIN user_lnk_up
    DIRECTION OUTPUT ;
    USE SIGNAL ;
    PORT
      LAYER metal3 ;
      RECT 279.620 247.415 280.000 247.485 ;
    END
  END user_lnk_up
  PIN user_reset
    DIRECTION OUTPUT ;
    USE SIGNAL ;
    PORT
      LAYER metal3 ;
      RECT 279.620 247.795 280.000 247.865 ;
    END
  END user_reset
END pcie_us

END LIBRARY
